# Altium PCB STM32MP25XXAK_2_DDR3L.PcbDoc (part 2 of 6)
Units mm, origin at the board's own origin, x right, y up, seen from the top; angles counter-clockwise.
Board outline 120 x 79.6 mm, 4 copper layers (Top Layer, Signal Layer 1, Signal Layer 2, Bottom Layer), stack 1.614 mm thick; 247 components, 155 nets, 1312 pads, 792 vias.
Unrouted connection lines stored in the file: 6.

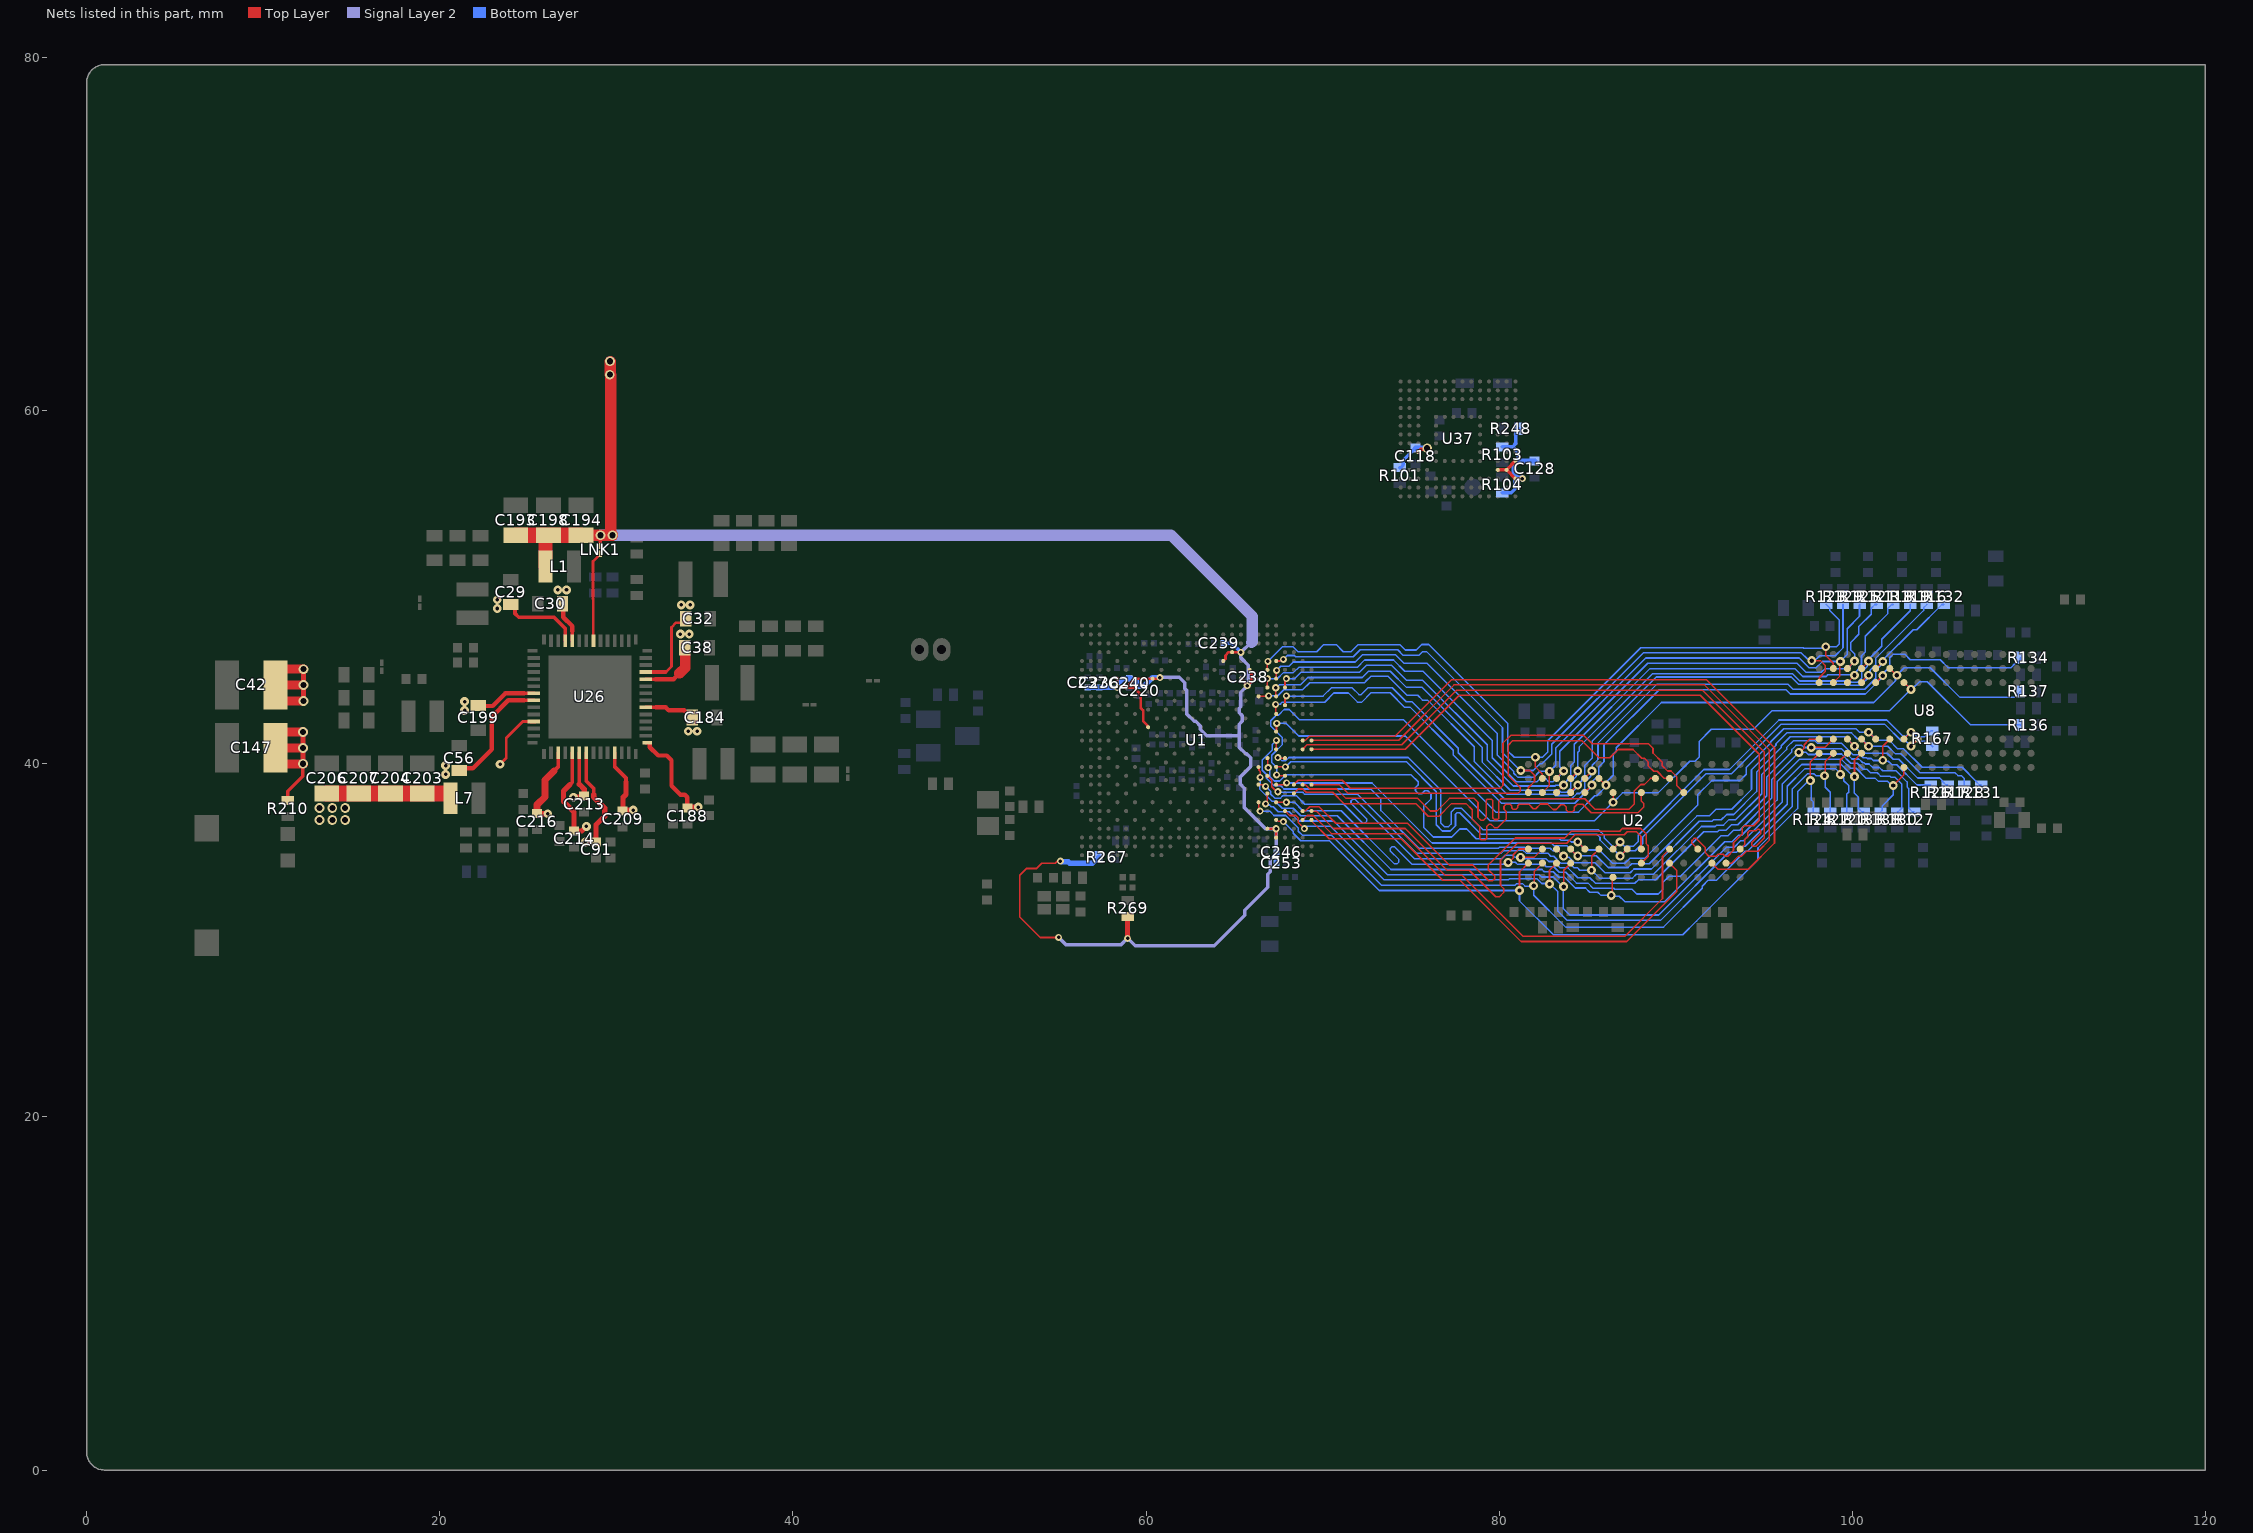
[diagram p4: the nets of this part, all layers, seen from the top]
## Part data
B2: library part MCD-03492, "Switch tactile, SPST-NO, 50mA, 12V, 6x3.8mm", Manufacturer="WURTH ELEKTRONIC", Manufacturer_Part_Number=434121025816, Package=6x3.8mm
C9 C118 C130: library part MCD-00006, "Capacitor, MLCC, 100nF, 16V, X7R, +/-10%, 0402, T=0.5mm", Alternate_Manufacturer=MURATA, Alternate_Manufacturer_Part_Number=GCM155R71C104KA55D, Manufacturer=YAGEO, Manufacturer_Part_Number=CC0402KRX7R7BB104, Package=0402
C22 C23 C24 C26 C27 C28 C34 C35 C36 C37 C41 C183 C200 C202: library part MCD-00100, "Capacitor, MLCC, 22uF, 6V3, X5R, +/-20%, 0603, T=0,8mm", Alternate_Manufacturer=N/A, Manufacturer=MURATA, Manufacturer_Part_Number=GRM188R60J226MEA0J, Package=0603
C29 C30 C32 C38 C56 C184 C199: library part MCD-00099, "Capacitor, MLCC, 10uF, 10V, X5R, +/-10%, 0603, T=0,8mm", Alternate_Manufacturer=N/A, Manufacturer=MURATA, Manufacturer_Part_Number=GRM188R61A106KE69D, Package=0603
C33: library part MCD-00011, "Capacitor, MLCC, 10nF, 16V, X7R, 10%, 0402, T=0.5mm", Manufacturer=YAGEO, Manufacturer_Part_Number=CC0402KRX7R7BB103, Package=C0402
C39 C40: library part MCD-03140, "Capacitor, MLCC, 10uF, 6.3V, X5R, +/-20%, 0402, T=0.5mm", Manufacturer=MURATA, Manufacturer_Part_Number=GRM155R60J106ME05D, Package=0402
C42 C147: library part MCD-01796, "Capacitor, Tantalum, 100uF, 6V3, 40mR, +/-20%,  Type_B (3528 metric), T=1.9mm", Manufacturer=AVX, Manufacturer_Part_Number=TCJB107M006R0040, Package="3528 (metric)"
C43 C188 C213 C216: library part MCD-00095, "Capacitor, MLCC, 1uF, 25V, X5R, +/-10%, 0402, T=0.5mm", Manufacturer=MURATA, Manufacturer_Part_Number=GRM155R61E105KA12, Package=0402
C44 C45 C46 C47 C48 C49 C50 C51 C52 C53 C54 C55 C57 C58 C59 C60 C62 C63 C64 C65 C66 C67 C68 C69 C70 C71 C72 C73 C74 C75 C76 C77 C82 C83: library part MCD-02377, "Capacitor, MLCC, 1uF, 6.3V, X5R, +/-20%, 0201, T=0,3mm", Manufacturer=MURATA, Manufacturer_Part_Number=GRM033R60J105MEA2, Package=0201
C61 C91 C189 C190 C208 C209 C214 C215 C217: library part MCD-01356, "Capacitor, MLCC, 4.7uF, 6V3, X5R, +/-20%, 0402, T=0.5mm", Manufacturer=MURATA, Manufacturer_Part_Number=GRM155R60J475ME47, Package=0402
C81 C86 C90 C92: library part MCD-00674, "Capacitor, MLCC, 6.8pF, 50V, NPO, +-0.25pF, 0402, T=0.5mm", Alternate_Manufacturer=N/A, Manufacturer=YAGEO, Manufacturer_Part_Number=CC0402CRNPO9BN6R8, Package=0402
C87: library part MCD-00006, "Capacitor,100nF,16V,X7R,10%,0402", Alternate_Manufacturer=MURATA, Alternate_Manufacturer_Part_Number=GCM155R71C104KA55D, Manufacturer=YAGEO, Manufacturer_Part_Number=CC0402KRX7R7BB104, Package=0402
C88: library part MCD-01823, "Capacitor, MLCC, 2.2uF, 6V3, X5R,+/-10%, 0402, T=0.5mm", Alternate_Manufacturer=N/A, Manufacturer=MURATA, Manufacturer_Part_Number=GRM155R60J225KE95D, Package=0402
C100 C101 C109 C110: library part MCD-00099, "Capacitor, MLCC, 10uF, 10V, X5R, +/-10%, 0603, T=0.8mm", Alternate_Manufacturer=N/A, Manufacturer=MURATA, Manufacturer_Part_Number=GRM188R61A106KE69D, Package=0603
C102 C103 C104 C105 C106 C107 C108 C111 C112 C113 C114 C115 C116 C119 C120 C121 C122 C125 C126 C127 C129 C131 C132 C133 C134 C135 C136 C137 C138 C139 C140 C146 C167 C177: library part MCD-00006, "Capacitor, MLCC, 100nF, 16V, X7R, +/-10%, 0402, T=0.5mm", Alternate_Manufacturer=MURATA, Alternate_Manufacturer_Part_Number=GCM155R71C104KA55D, Manufacturer=YAGEO, Manufacturer_Part_Number=CC0402KRX7R7BB104, Package=C0402
C117 C128 C148: library part MCD-02606, "Capacitor, MLCC, 2.2uF, 6.3V, X5R, +/-10%, 0402, T=0.5mm", Manufacturer=YAGEO, Manufacturer_Part_Number=CC0402KRX5R5BB225, Package=0402
C123 C124: library part MCD-00100, "Capacitor, MLCC, 22uF, 6V3, X5R, +/-20%, 0603, T=0,8mm", Manufacturer=MURATA, Manufacturer_Part_Number=GRM188R60J226MEA0J, Package=C0603
C151 C250 C252 C260: library part MCD-02377, "Capacitor, MLCC, 1uF, 6.3V, X5R, +/-20%, 0201, T=0,3mm", Alternate_Manufacturer=N/A, Manufacturer=MURATA, Manufacturer_Part_Number=GRM033R60J105MEA2, Package=0201
C185 C186 C187 C193 C194 C198 C203 C204 C206 C207: library part MCD-03139, "Capacitor, MLCC, 22uF, 10V, X5R, +/-20%, 0805, T=1,25mm", Manufacturer=MURATA, Manufacturer_Part_Number=GRM21BR61A226ME51L, Package=0805
C192 C195 C196 C197 C201 C205 C220 C234 C236 C237 C238 C239 C240 C244 C246 C248 C251 C253: library part MCD-01535, "Capacitor, MLCC,100nF, 10V, X7R, +/-10%, 0201, T=0.3mm", Alternate_Manufacturer=N/A, Manufacturer=MURATA, Manufacturer_Part_Number=GRM033R61A104KE15, Package=0201
C219: library part MCD-02198, "Capacitor, MLCC, 10nF, 50V, X7R, +/-10%, 0402, T=0.5mm", Manufacturer=YAGEO, Manufacturer_Part_Number=CC0402KRX7R9BB103, Package=0402
C225: library part MCD-01534, "Capacitor, MLCC, 4,7uF, 6V3, X5R, +/-20%, 0201, T=0.5mm", Alternate_Manufacturer=N/A, Manufacturer=MURATA, Manufacturer_Part_Number=GRM035R60J475ME15, Package=0201
C235: library part MCD-02235, "Capacitor, MLCC, 2.2uF, 10V, X5R,+/-10%, 0201, T=0.5mm", Manufacturer=MURATA, Manufacturer_Part_Number=GRM033R61A225KE47D, Package=0201
CN12: library part MCD-00655, "Header 2 circuits, 1.25mm Pitch ,  Vertical, with Friction Lock", Alternate_Manufacturer=N/A, Manufacturer=MOLEX, Manufacturer_Part_Number=53047-0210
D6: library part MCD-03280, "Diode, Schottky, Dual Common Cathode, 0V3, 300mA, 40V, SOT-23", Manufacturer=STMICROELECTRONICS, Manufacturer_Part_Number=BAT54CFILM, Package=SOT-23
D7: library part MCD-00034, Manufacturer=STMICROELECTRONICS, Manufacturer_HQ_COO=EU
L1 L6: library part MCD-03143, "Inductor, 2.2uH, +/-20%, Itemp= 1700mA, Isat= 2400mA, 0R140, 0806, T=1mm", Manufacturer=MURATA, Manufacturer_Part_Number=DFE201610E-2R2M{}P2, Package=0806
L2 L4: library part MCD-03142, "Inductor, 0.68uH, +/-20%, Itemp= 3900mA, Isat= 5400mA, 0R031, 1008, T=1.2mm", Manufacturer=MURATA, Manufacturer_Part_Number=DFE252012F-R68M{}P2, Package=1008
L3 L5 L7: library part MCD-03141, "Inductor, 0.68uH, +/-20%, Itemp= 3100mA, Isat= 4300mA, 0R043, 0806, T=1mm", Manufacturer=MURATA, Manufacturer_Part_Number=DFE201610E-R68M{}P2, Package=0806
LD11: library part MCD-00588, "LED Green, 0603 SMD, Forward Voltage Typ=2V, Max=2.5V", Alternate_Manufacturer="VISHAY SEMICONDUCTOR OPTO DIVISION", Alternate_Manufacturer_Part_Number=VLMTG1300-GS08, Manufacturer="OSRAM OPTO SEMICONDUCTORS", Manufacturer_Part_Number="LG Q396-PS-35", Package="LED 0603"
LNK1 LNK2 LNK4 LNK7 LNK8 LNK11: library part MCD-02777, "Track link on PCB 200um width for layout routing", Manufacturer=N/A
R1: library part MCD-02253, "Resistor, 240R, 0201, +/-1%, 1/20W", Alternate_Manufacturer=N/A, Manufacturer=YAGEO, Manufacturer_Part_Number=RC0201FR-07240RL, Package=0201
R11: library part MCD-00056, "Resistor, 0R, 0603, +/-5%, 1/10W", Manufacturer=YAGEO, Manufacturer_Part_Number=RC0603JR-070RL, Package=0603
R27 R272: library part MCD-00053, "Resistor,10K,0402,1%,1/16W", Alternate_Manufacturer=N/A, Manufacturer=YAGEO, Manufacturer_Part_Number=RC0402FR-0710KL, Package=0402
R46 R57 R59 R60 R61 R64 R75 R81 R267 R269 R286: library part MCD-00052, "Resistor,0R,0402,5%,1/16W", Alternate_Manufacturer=N/A, Manufacturer=YAGEO, Manufacturer_Part_Number=RC0402JR-070RL, Package=0402
R66: library part MCD-00058, "Resistor, 20R, 0402, +/-1%, 1/16W", Alternate_Manufacturer=N/A, Manufacturer=YAGEO, Manufacturer_Part_Number=RC0402FR-0720RL, Package=0402
R67: library part MCD-00052, "Resistor, 0R, 0402, +/-5%, 1/16W", Manufacturer=YAGEO, Manufacturer_Part_Number=RC0402JR-070RL, Package=0402
R101 R103 R104 R248: library part MCD-00053, "Resistor,10K,0402,1%,1/16W", Manufacturer=YAGEO, Manufacturer_Part_Number=RC0402FR-0710KL, Package=0402
R116 R117 R118 R119 R120 R121 R122 R123 R124 R125 R126 R127 R128 R129 R130 R131 R132 R133 R134 R135 R136 R137 R138 R139 R140: library part MCD-00054, "Resistor, 56R, 0402, +/-1%, 1/16W", Alternate_Manufacturer=N/A, Manufacturer=YAGEO, Manufacturer_Part_Number=RC0402FR-0756RL, Package=0402
R141 R142 R143 R144 R146 R147 R148 R149: library part MCD-00061, "Resistor, 1K, 0402, +/-1%,1/16W", Manufacturer=YAGEO, Manufacturer_Part_Number=RC0402FR-071KL, Package=0402
R145 R150: library part MCD-00120, "Resistor,240R,0402,1%,1/16W", Manufacturer=YAGEO, Manufacturer_Part_Number=RC0402FR-07240RL, Package=R0402
R156: library part MCD-00053, "Resistor,10K,0402,1%,1/16W", Manufacturer=YAGEO, Manufacturer_Part_Number=RC0402FR-0710KL, Package=R0402
R167: library part MCD-01819, "Resistor,100R,0402,0,5%,1/16W,±100ppm/°C", Manufacturer=YAGEO, Manufacturer_Part_Number=RC0402DR-07100RL, Package=R0402
R210: library part MCD-00441, "Resistor,270R,0402,1%,1/16W", Manufacturer=YAGEO, Manufacturer_Part_Number=RC0402FR-07270RL, Package=0402
R260 R261: library part MCD-00068, "Resistor,1K5,0402,1%,1/16W", Manufacturer=YAGEO, Manufacturer_Part_Number=RC0402FR-071K5L, Package=0402
TP21: library part MCD-00074, "Test Point 1mm", Manufacturer=n/a
U1: library part MCD-03375, "MPU , 2xCortex-A35@1.5GHz, Cortex-M33@400MHz, TFBGA 14x14, pitch 0.5, 648KB SRAM, With Crypto", Manufacturer=STMICROELECTRONICS, Package=TFBGA
U2 U8: library part MCD-01811, "Memory,DDR3L,4Gb,256Mbx16,933Mhz,1V35,TFBGA", Manufacturer=NANYA
U26: library part MCD-03000, "STPMIC2", Manufacturer=STMICROELECTRONICS, Package=VQFN
U37: library part MCD-02799, "Memory, eMMC, 4GB, 15nm ,WFBGA , 153 pins", Manufacturer=KIOXIA, Manufacturer_Part_Number=THGBMTG5D1LBAIL, Package=WFBGA153
X1: library part MCD-01479, "Crystal, 32.768kHz, 6pF, +/-20ppm, 80K, 2.05x1.2mm", Manufacturer=NDK, Manufacturer_Part_Number=NX2012SA-32.768KHZ-EXS00A-MU00527, Package=2.05x1.2mm
X2: library part MCD-02344, "Crystal, 40MHz, 6pF, +/-20ppm, 80R, 1.6x1.2mm", Manufacturer=NDK, Manufacturer_Part_Number=NX1612SA-40MHZ-EXS00A-CS13836, Package=1.6x1.2mm

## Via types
v1: diameter 0.55, hole 0.35, Top Layer to Bottom Layer, 275 vias
v2: diameter 0.4, hole 0.2, Top Layer to Bottom Layer, tented both sides, 246 vias
v3: diameter 0.5, hole 0.2, Top Layer to Bottom Layer, 146 vias
v4: diameter 0.5, hole 0.25, Top Layer to Bottom Layer, 125 vias

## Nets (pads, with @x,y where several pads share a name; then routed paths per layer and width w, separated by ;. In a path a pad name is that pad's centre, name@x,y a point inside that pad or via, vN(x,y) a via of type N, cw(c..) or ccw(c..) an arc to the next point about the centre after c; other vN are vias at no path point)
1V8: C118.2 C128.2 C193.2 C194.2 C198.2 C220.2 C236.2 C237.2 C238.2 C239.2 C240.2 C246.2 C253.2 L1.2 LNK1.2 R101.2 R103.2 R104.2 R248.2 R267.2 R269.1 U1.1E1 U1.AD22 U1.AE23 U1.D18 U1.E17 U1.F20 U1.G5 U1.G7 U1.G9 U1.G19 U1.H6 U37.C6 U37.M4 U37.N4 U37.P3 U37.P5 | length 137.4
  Top Layer w0.1: v2(55.049,30.165) 54.012,30.165 52.854,31.323 52.854,33.688 53.244,34.078 53.813,34.078 54.103,34.368 54.86,34.368 54.967,34.474 55.127,34.474 v2(55.146,34.494)
  Top Layer w0.15: U1.G5@58.375,44.825 v2(58.375,44.325) U1.H6@58.875,44.325 ; U1.1E1@60.125,42.075 60.125,42.097 60.085,42.137 60.085,42.17 59.835,42.42 59.835,43.035 59.702,43.168 59.702,43.926 59.304,44.325 U1.H6@58.875,44.325 ; v2@60.792,44.887 v2(60.79,44.885) 60.73,44.825 U1.G9@60.375,44.825 U1.G7@59.375,44.825 U1.H6@58.875,44.325 ; U1.E17@64.375,45.825 64.375,45.828 64.5,45.953 64.5,46.139 64.683,46.322 U1.D18@64.872,46.322 ; U1.D18@64.853,46.325 U1.D18@64.875,46.325 65.372,46.325 v2(65.378,46.319) ; U1.G19@65.378,44.822 65.735,44.465 v2(65.735,44.426) 65.735,44.412 65.973,44.651 65.973,45.205 65.875,45.303 U1.F20@65.875,45.325 ; U1.AD22@66.875,36.325 v2(67.375,36.325) U1.AE23@67.375,35.825 ; U37.P3@80.925,56.155 v2(81.325,56.155)
  Top Layer w0.2: LNK1.2@29.1,52.348 v1(29.1,52.95) ; U37.C6@75.425,57.655 75.602,57.832 75.877,57.832 v1(75.925,57.88) ; U37.M4@79.925,56.655 U37.N4@80.425,56.655 ; U37.P3@80.925,56.155 U37.N4@80.425,56.655 ; U37.P5@80.925,57.155 U37.N4@80.425,56.655
  Top Layer w0.3: R269.1@58.956,31.358 58.956,30.117 v2(58.962,30.112)
  Top Layer w0.64: C194.2@28,52.95 v1(29.1,52.95) v1(29.78,52.95) 29.674,53.056 v1@29.674,62.004 ; v1@29.66,62.075 v1@29.66,62.782
  Top Layer w0.8: L1.2@25.995,51.175 25.995,52.9 26.045,52.95 C198.2@26.15,52.95
  Top Layer w0.9: C193.2@24.3,52.95 C198.2@26.045,52.95 ; C198.2@26.15,52.95 C194.2@28,52.95
  Signal Layer 2 w0.2: v2(55.049,30.165) 55.449,29.766 58.598,29.766 v2@58.944,30.112 ; v2(58.962,30.112) 59.386,29.688 63.861,29.688 65.603,31.43 65.603,31.711 66.9,33.008 66.9,33.754 67.041,33.895 67.041,34.559 67.375,34.893 v2(67.375,36.325) ; v2(60.79,44.885) 60.811,44.906 61.89,44.906 62.2,44.596 62.2,44.264 62.32,44.144 62.32,42.814 62.725,42.409 62.81,42.409 63.077,42.143 ; 63.075,42.156 63.077,42.155 63.077,42.143 ; 65.285,41.575 65.285,40.928 65.64,40.572 65.694,40.572 65.93,40.336 65.93,39.851 65.349,39.271 65.349,38.835 65.569,38.615 65.569,37.527 65.566,37.525 66.77,36.322 v2@67.372,36.322 ; v2@65.674,44.353 65.773,44.452 65.773,44.591 65.794,44.612 65.794,45.583 65.378,45.999 v2(65.378,46.319) 65.927,46.868 65.981,46.868 ; v2@65.734,44.411 65.375,44.053 65.375,43.231 65.284,43.14 65.284,42.894 65.44,42.738 65.44,42.406 65.285,42.251 65.285,41.593 63.445,41.593 63.077,41.961 63.077,42.143
  Signal Layer 2 w0.64: v1@29.1,52.955 v1@29.78,52.955 ; v1(29.78,52.95) 61.405,52.95 ; 61.411,52.956 66.023,48.344 66.023,46.91 65.981,46.868
  Bottom Layer w0.15: v2(67.375,36.325) 67.375,34.827 67.391,34.811
  Bottom Layer w0.2: C239.2@64.4,46.837 64.86,46.837 v2(65.378,46.319) ; v2@65.735,44.411 65.958,44.635 65.958,44.819 C238.2@66.033,44.894 ; R101.2@74.375,56.775 74.425,56.775 74.58,56.93 74.58,57.2 75.08,57.7 75.08,57.725 75.235,57.88 C118.2@75.26,57.88 ; R103.2@80.171,57.961 80.769,57.961 ; R104.2@80.175,55.355 80.69,55.355 80.885,55.55 80.885,55.998 81.061,56.174 ; 81.075,57.136 81.075,57.655 80.769,57.961 ; R248.2@81.107,58.98 80.952,58.825 80.952,58.144 80.769,57.961
  Bottom Layer w0.25: C253.2@67.391,34.385 67.391,34.811 C246.2@67.391,34.986
  Bottom Layer w0.3: v2(55.146,34.494) 55.165,34.474 55.236,34.474 55.259,34.452 55.612,34.452 55.689,34.375 56.975,34.375 57.123,34.523 57.218,34.523 57.323,34.628 R267.2@57.323,34.723 ; C237.2@56.696,44.325 C236.2@57.35,44.325 v2@58.386,44.325 ; v2(58.375,44.325) 58.394,44.344 58.394,44.53 58.689,44.825 59.025,44.825 C240.2@59.025,44.85 ; C240.2@58.984,44.85 59.125,44.85 59.15,44.825 59.19,44.825 59.3,44.715 59.399,44.715 59.54,44.574 59.54,44.475 C220.2@59.609,44.406 59.634,44.431 59.911,44.431 60.372,44.892 60.783,44.892 v2(60.79,44.885) ; C118.2@75.26,57.88 v1(75.925,57.88) ; v2(81.325,56.155) 81.306,56.174 81.061,56.174 80.867,56.368 80.867,56.928 81.075,57.136 81.306,57.136 81.325,57.155 C128.2@82.015,57.155
  other v1: 29.631,62.047 29.642,62.8
1V8_FB: LNK1.1 U26.35 | length 5.1
  Top Layer w0.15: U26.35@28.7,46.97 28.7,49.311 28.675,49.336 28.675,51.473 LNK1.1@29.1,51.898
3V3: C203.2 C204.2 C206.2 C207.2 C216.2 L7.2 U26.3 U26.53 | length 15.3
  Top Layer w0.15: v3(23.41,39.977) 23.762,40.329 23.762,41.465 24.697,42.4 U26.53@25.33,42.4 ; U26.53@25.12,42.369 25.419,42.369 U26.53@25.45,42.4
  Top Layer w0.21: 26.473,39.598 26.7,39.825 U26.3@26.7,40.63
  Top Layer w0.3: C216.2@25.475,37.175 C216.2@25.5,37.175 v3@26.085,37.175
  Top Layer w0.4: C216.2@25.5,37.175 25.514,37.189 25.514,37.685 25.96,38.131 25.96,39.085 26.473,39.598
  Top Layer w0.9: C206.2@13.587,38.323 C203.2@19,38.323 20.362,38.323 L7.2@20.387,38.298
  other v1: 13.187,36.823 13.912,36.823 14.637,36.823 13.187,37.498 13.912,37.498 14.637,37.498
  other v3: 26.11,37.175
5V_HDMI: C91.1 U26.7 | length 6.1
  Top Layer w0.21: U26.7@28.3,40.63 28.3,39.025 28.715,38.61 28.715,38.253
  Top Layer w0.3: v3(28.24,35.58) C91.1@28.85,35.58 ; 28.715,38.253 28.715,38.118 29.335,37.498 29.335,37.035 28.85,36.55 C91.1@28.85,35.73
5V_STLK: C29.2 C30.2 C32.2 C38.2 C42.1 C56.2 C147.1 C184.2 C188.2 C199.2 C209.2 C213.2 R210.1 U26.6 U26.11 U26.15 U26.20 U26.24 U26.25 U26.38 U26.39 U26.49 U26.50 | length 56.6
  Top Layer w0.15: 32.8,45.2 33.125,45.525 33.125,47.731 33.388,47.994 33.819,47.994 C32.2@33.925,48.1
  Top Layer w0.2: R210.1@11.386,37.915 11.386,38.449 12.244,39.307 v1@12.244,39.994
  Top Layer w0.21: C29.2@24.025,49.05 24.262,48.813 24.262,48.513 24.475,48.3 26.464,48.3 27.1,47.664 U26.39@27.1,46.97 ; 24.775,43.6 U26.50@25.33,43.6 ; 24.775,44 U26.49@25.33,44 ; U26.38@27.5,46.97 27.5,47.525 ; 27.9,38.85 U26.6@27.9,40.63 ; U26.11@29.9,40.63 29.9,39.843 30.54,39.203 30.54,38.975 ; U26.15@31.67,41.2 U26.15@31.745,41.2 U26.15@31.785,41.2 ; U26.20@31.67,43.2 32.225,43.2 ; U26.24@31.67,44.8 32.207,44.8 ; U26.25@31.67,45.2 32.8,45.2
  Top Layer w0.25: C56.2@21.1,39.75 21.875,39.75 22.95,40.825 22.95,42.669 23.881,43.6 24.775,43.6 ; C199.2@22.175,43.275 22.991,43.275 23.716,44 24.775,44 ; C30.2@26.925,49.075 26.994,49.006 26.994,48.308 27.5,47.802 27.5,47.525 ; 31.895,41.095 31.895,40.947 32.371,40.472 32.853,40.472 33.125,40.2 33.125,38.759 33.634,38.25 33.879,38.25 34.025,38.104 C188.2@34.025,37.55 ; 32.207,44.8 33.25,44.8 33.575,45.125 ; 32.225,43.2 32.788,43.2 32.963,43.025 33.847,43.025 33.972,42.9 34.05,42.9 34.247,42.703 C184.2@34.247,42.625
  Top Layer w0.3: v1@12.25,40 12.25,40.902 12.25,40.906 v1@12.25,41.8 ; v1@12.275,43.563 12.275,44.463 v1@12.275,45.363 ; v3(27.565,38.11) 28.175,38.11 28.174,38.111 28.174,38.576 27.9,38.85 ; C209.2@30.35,37.38 C209.2@30.375,37.38 ; 30.54,38.975 30.54,38.269 30.375,38.104 C209.2@30.375,37.38 ; v3(30.96,37.38) C209.2@30.375,37.38 ; C188.2@34.025,37.55 v3(34.635,37.55)
  Top Layer w0.5: C147.1@10.686,39.994 12.244,39.994 v1@12.269,39.994 ; C147.1@10.686,40.906 12.25,40.906 v1@12.269,40.906 ; C147.1@10.686,41.806 v1@12.269,41.806 ; C42.1@10.686,43.557 v1@12.269,43.557 ; C42.1@10.686,44.468 v1@12.269,44.468 ; C42.1@10.686,45.368 v1@12.269,45.368
  Top Layer w0.6: 33.575,45.125 33.9,45.45 C38.2@33.9,46.175
  other v1: 12.251,40.002 12.251,40.902 12.251,41.802 12.276,43.565 12.276,44.465 12.276,45.365
  other v3: 20.325,39.4 20.325,39.9 34.075,41.85 34.575,41.85 21.4,43.025 21.4,43.525 33.625,47.35 34.125,47.35 23.25,48.8 33.675,49 34.175,49 23.25,49.3 26.675,49.85 27.175,49.85
5V_VCONN: C214.1 U26.5 | length 5.7
  Top Layer w0.21: 27.378,38.827 27.5,38.95 U26.5@27.5,40.63
  Top Layer w0.3: 27.378,38.827 27.01,38.46 27.01,37.865 27.6,37.275 C214.1@27.6,36.2 28.04,36.2 v3(28.3,36.46)
DDR_A0: R116.1 U1.J21 U2.N3 U8.N3 | length 49.2
  Top Layer w0.09: U1.J21@66.375,43.825 66.387,43.837 66.937,43.837 v2(66.95,43.85) ; U2.N3@84.057,38.377 84.057,38.425 v4@84.442,38.81 ; U8.N3@100.532,44.602 100.532,44.65 v4@100.932,45.05
  Bottom Layer w0.09: v2(66.95,43.85) 67.467,43.85 67.807,44.19 68.871,44.19 69.28,44.6 72.37,44.6 72.477,44.707 72.725,44.954 73.717,44.954 74.79,43.881 75.388,43.881 75.656,43.613 75.944,43.613 78.595,40.963 78.595,40.131 79.028,39.698 80.448,38.278 83.108,38.278 83.176,38.21 83.93,38.21 84.457,38.736 84.457,38.795 84.457,38.816 84.681,39.04 84.681,39.199 84.857,39.375 84.857,39.906 85.278,40.327 85.278,41.29 88.906,44.918 96.55,44.918 96.957,44.511 99.824,44.511 99.893,44.443 100.462,44.443 100.932,44.913 v4(100.932,45.02) 101.01,45.098 101.01,45.301 101.328,45.618 101.328,45.954 101.328,45.971 104.045,48.688 104.045,48.837 R116.1@104.233,49.025
  other v4: 84.459,38.795
DDR_A1: R117.1 U1.R23 U2.P7 U8.P7 | length 50.5
  Top Layer w0.09: U1.R23@67.375,40.825 67.378,40.828 v2@67.378,41.323 ; U2.P7@83.257,35.177 v4@83.657,34.777 ; U8.P7@99.732,41.402 v4(100.132,41)
  Bottom Layer w0.09: v2@67.378,41.327 67.142,41.09 67.142,40.776 66.58,40.215 66.58,39.642 66.817,39.406 66.817,39.202 67.252,38.766 67.628,38.766 67.819,38.575 72.734,38.575 73.309,38 73.309,37.36 75.444,35.225 79.969,35.225 80.03,35.285 81.455,35.285 81.515,35.225 82.903,35.225 83.058,35.07 83.362,35.07 v4(83.657,34.775) 83.721,34.71 83.958,34.71 84.276,34.392 85.431,34.392 85.993,33.83 87.431,33.83 87.644,34.043 88.628,34.043 91.337,36.752 92.064,36.752 92.142,36.831 92.591,36.831 92.893,37.133 93.285,37.133 94.586,38.433 94.586,39.531 95.986,40.931 95.986,41.032 96.494,41.54 99.591,41.54 v4(100.132,41) ; v4@100.131,40.998 100.131,40.979 100.395,40.715 100.626,40.715 100.738,40.602 101.985,40.602 102.328,40.259 102.646,40.259 103.707,39.198 104.958,39.198 105.103,39.053 105.103,39.01 105.313,38.8 R117.1@105.408,38.8
  other v2: 67.381,41.327
DDR_A2: R118.1 U1.H24 U2.P3 U8.P3 | length 46.5
  Top Layer w0.09: U1.H24@67.875,44.325 67.875,44.666 67.95,44.741 v2(67.95,44.825) ; U2.P3@83.257,38.377 83.657,38.776 v4(83.657,38.795) v4@83.657,38.825 ; U8.P3@99.732,44.602 100.132,45.001 v4(100.132,45.02) v4@100.132,45.05
  Bottom Layer w0.09: v2(67.95,44.825) 68.417,44.825 68.781,45.19 72.098,45.19 72.503,45.594 73.897,45.594 74.745,44.746 75.654,44.746 79.323,41.078 79.323,40.223 80.798,38.748 83.169,38.748 83.208,38.787 83.649,38.787 v4(83.657,38.795) ; v4@83.656,38.823 83.656,38.858 84.062,39.263 84.062,39.905 84.256,40.1 84.256,41.104 ; 84.255,41.104 88.549,45.398 96.749,45.398 97.197,44.95 98.53,44.95 98.624,45.044 100.128,45.044 100.128,45.127 100.252,45.251 100.252,45.264 100.373,45.385 100.373,45.484 100.527,45.638 100.527,46.124 ; 100.526,46.124 100.735,46.333 100.735,47.228 102.027,48.52 102.027,48.815 102.237,49.025 R118.1@102.332,49.025
DDR_A3: R119.1 U1.J23 U2.N2 U8.N2 | length 48
  Top Layer w0.09: v2@67.357,44.29 67.357,43.843 U1.J23@67.375,43.825 ; U2.N2@84.064,39.175 84.457,39.568 v4(84.457,39.595) ; U8.N2@100.532,45.402 100.932,45.801 v4@100.932,45.818
  Bottom Layer w0.09: v2(67.35,44.31) 67.388,44.31 67.558,44.48 68.75,44.48 69.16,44.89 72.25,44.89 72.605,45.244 73.837,45.244 73.841,45.241 74.753,44.329 75.637,44.329 ; 75.638,44.329 75.641,44.326 79.028,40.939 79.037,40.931 79.037,40.1 80.629,38.508 83.385,38.508 83.394,38.499 83.494,38.4 83.822,38.4 83.829,38.4 84.064,38.635 84.064,38.986 84.382,39.305 84.382,39.521 v4(84.457,39.595) ; v4@84.459,39.597 84.459,40.652 84.532,40.725 84.532,40.95 88.677,45.095 88.828,45.095 88.831,45.098 90.8,45.098 96.625,45.098 ; 96.625,45.097 96.629,45.095 97.032,44.691 99.899,44.691 ; 99.899,44.691 99.903,44.688 99.969,44.623 100.296,44.623 100.302,44.623 100.534,44.854 100.534,45.192 100.857,45.515 100.857,45.737 v4@100.932,45.811 ; v4@100.936,45.822 100.936,45.931 101.669,46.664 101.669,47.053 103.283,48.668 R119.1@103.283,49.025
  other v4: 100.932,45.82
DDR_A4: R120.1 U1.AB24 U2.P8 U8.P8 | length 44.3
  Top Layer w0.09: U1.AB24@67.875,37.325 67.884,37.325 68.134,37.075 68.48,37.075 68.625,36.93 68.625,36.675 v2(68.976,36.326) ; v4@82.857,33.227 82.857,33.977 U2.P8@83.257,34.377 ; v4@99.332,39.452 99.332,40.202 U8.P8@99.732,40.602
  Bottom Layer w0.09: v2(68.976,36.326) 69.125,36.475 70.443,36.475 73.493,33.425 80.531,33.425 80.606,33.5 82.137,33.5 82.412,33.225 82.857,33.225 83.316,32.765 83.316,31.667 83.834,31.149 89.168,31.149 93.012,34.993 93.45,34.993 93.79,35.333 93.946,35.333 96.326,37.713 96.326,38.725 97.333,39.733 99.057,39.733 99.331,39.458 99.331,39.388 99.529,39.19 99.529,39.04 99.802,38.768 99.802,38.395 99.699,38.292 99.699,37.279 R120.1@99.706,37.273
  other v4: 82.857,33.195 99.332,39.4
DDR_A5: R121.1 U1.H22 U2.P2 U8.P2 | length 47.2
  Top Layer w0.09: U1.H22@66.875,44.325 v2(66.875,44.825) ; U2.P2@83.257,39.175 83.257,39.196 v4(83.657,39.595) ; U8.P2@99.732,45.402 99.734,45.402 v4@100.132,45.8
  Bottom Layer w0.09: v2@66.874,44.823 67.441,44.823 67.788,45.17 68.351,45.17 68.661,45.48 71.978,45.48 72.383,45.884 74.017,45.884 74.655,45.246 75.686,45.246 79.613,41.319 79.613,40.343 80.968,38.988 82.145,38.988 82.395,39.237 82.57,39.237 82.657,39.15 ; 82.655,39.148 82.815,38.988 83.059,38.988 83.657,39.585 v4(83.657,39.595) 83.657,39.617 83.443,39.831 83.443,40.716 88.424,45.698 96.873,45.698 97.381,45.19 98.256,45.19 98.459,45.393 99.727,45.393 100.131,45.798 100.143,45.809 100.147,45.813 100.147,46.22 99.928,46.439 99.928,46.888 100.378,47.339 100.378,47.78 101.077,48.478 101.077,48.815 101.287,49.025 R121.1@101.382,49.025
  other v4: 100.132,45.82
DDR_A6: R122.1 U1.AA21 U2.R8 U8.R8 | length 45.2
  Top Layer w0.09: U1.AA21@66.375,37.825 66.375,37.484 66.45,37.409 v2@66.45,37.325 ; v4(81.957,33.099) 82.003,33.146 82.003,33.913 82.457,34.367 U2.R8@82.457,34.377 ; v4(98.432,39.324) 98.48,39.372 98.48,40.14 98.932,40.592 U8.R8@98.932,40.602
  Bottom Layer w0.09: v2(66.46,37.325) 67.003,37.325 67.253,37.075 67.923,37.075 68.631,36.367 68.631,36.183 68.864,35.95 70.511,35.95 73.336,33.125 80.898,33.125 80.993,33.22 81.32,33.22 81.465,33.075 81.956,33.075 81.956,32.564 83.765,30.756 89.315,30.756 91.506,32.947 91.506,33.07 91.853,33.418 92.326,33.418 93.951,35.043 94.066,35.043 96.616,37.593 96.616,38.593 97.468,39.445 97.825,39.445 97.948,39.322 98.431,39.322 98.476,39.277 98.476,38.678 98.757,38.397 R122.1@98.758,37.275
DDR_A7: R123.1 U1.F22 U2.R2 U8.R2 | length 46
  Top Layer w0.09: U1.F22@66.875,45.325 66.875,45.775 v2(66.9,45.8) ; v4(82.057,40.375) 82.057,39.822 82.451,39.427 82.451,39.18 U2.R2@82.457,39.175 ; v4(98.5,46.631) 98.5,46.137 98.932,45.705 U8.R2@98.932,45.4
  Bottom Layer w0.09: v2(66.9,45.8) 67.735,46.635 68.322,46.635 68.607,46.35 69.668,46.35 70.072,46.754 70.771,46.754 71.175,46.35 71.618,46.35 72.022,46.754 74.378,46.754 74.683,46.449 75.315,46.449 75.626,46.76 76.022,46.76 80.483,42.3 80.483,40.746 80.856,40.373 v4(82.057,40.375) 82.461,40.373 82.756,40.668 82.756,41.302 88.025,46.571 88.056,46.588 97.228,46.588 97.262,46.554 98.422,46.554 v4(98.5,46.631) ; v4@98.491,46.638 99.106,46.638 99.278,46.809 99.278,48.131 98.723,48.685 98.723,48.833 R123.1@98.532,49.025
DDR_A8: R124.1 U1.AC23 U2.T8 U8.T8 | length 43.3
  Top Layer w0.09: U1.AC23@67.375,36.825 67.413,36.825 67.498,36.74 67.77,36.74 v2(67.78,36.73) ; v4(81.157,32.825) 81.157,33.876 U2.T8@81.657,34.377 ; v4(97.632,39.05) 97.632,40.101 U8.T8@98.132,40.602
  Bottom Layer w0.09: v2(67.78,36.73) 68.341,36.169 68.341,36.063 68.762,35.642 70.393,35.642 73.21,32.825 v4(81.157,32.825) ; v4@81.156,32.823 81.156,32.236 83.078,30.315 90.407,30.315 91.188,31.096 94.666,34.574 94.666,35.233 96.906,37.472 96.906,38.426 97.528,39.048 97.631,39.048 v4@97.631,38.951 ; v4@97.635,38.951 97.686,38.9 97.686,37.956 97.807,37.836 R124.1@97.808,37.275
DDR_A9: R125.1 U1.G23 U2.R3 U8.R3 | length 46.5
  Top Layer w0.09: U1.G23@67.375,44.825 67.375,45.275 v2(67.4,45.3) ; U2.R3@82.457,38.377 82.832,38.752 v4@82.832,39.552 ; U8.R3@98.932,44.602 99.307,44.977 v4@99.307,45.777
  Bottom Layer w0.09: v2(67.4,45.3) 67.631,45.531 68.103,45.531 68.341,45.77 71.858,45.77 72.263,46.174 74.137,46.174 74.614,45.698 75.919,45.698 79.903,41.714 79.903,40.506 80.837,39.572 80.837,39.461 81.068,39.23 81.963,39.23 82.308,39.575 v4(82.857,39.575) 83.206,39.924 83.206,40.904 88.3,45.998 96.998,45.998 97.543,45.453 97.973,45.453 98.32,45.8 v4(99.332,45.8) 99.332,45.809 99.721,46.199 99.721,47.659 100.418,48.355 100.418,49.01 R125.1@100.433,49.025
DDR_A10: R126.1 U1.V22 U2.L7 U8.L7 | length 48
  Top Layer w0.09: U1.V22@66.875,39.325 67.125,39.075 67.125,38.708 67.411,38.421 v2(67.471,38.421) ; v4@85.243,33.981 85.243,34.761 U2.L7@85.657,35.175 ; v4(101.732,40.2) 101.732,41 U8.L7@102.132,41.4
  Bottom Layer w0.09: v2(67.471,38.421) 67.493,38.4 67.744,38.4 67.759,38.385 68.88,38.385 68.975,38.289 71.967,38.289 75.331,34.925 80.109,34.925 80.252,35.068 81.043,35.068 81.07,35.095 81.376,35.095 81.547,34.925 82.778,34.925 82.933,34.77 83.096,34.77 83.476,34.39 83.48,34.39 83.493,34.378 83.969,34.378 84.222,34.125 84.426,34.125 84.576,33.975 v4(85.237,33.975) 85.682,33.53 87.555,33.53 87.768,33.743 88.752,33.743 91.462,36.452 92.246,36.452 92.324,36.531 92.715,36.531 93.027,36.843 93.405,36.843 94.876,38.313 94.876,39.397 96.286,40.807 96.286,40.922 96.684,41.32 97.875,41.32 98.037,41.157 99.406,41.157 100.038,40.525 100.452,40.525 100.624,40.353 100.818,40.353 100.869,40.302 101.086,40.302 101.197,40.191 101.723,40.191 v4(101.732,40.2) 101.781,40.151 102.047,40.151 102.252,39.946 102.531,39.946 103.677,38.8 R126.1@104.458,38.8
DDR_A11: R127.1 U1.W21 U2.R7 U8.R7 | length 52.1
  Top Layer w0.09: U1.W21@66.375,38.825 66.392,38.808 66.617,38.808 66.696,38.729 v2(66.78,38.729) ; v4@81.232,34.7 81.252,34.72 82.002,34.72 U2.R7@82.457,35.175 ; U2.R7@82.456,35.175 U2.R7@82.457,35.177 ; v4(97.682,40.925) 97.708,40.951 98.482,40.951 U8.R7@98.932,41.402
  Bottom Layer w0.09: v2(66.78,38.729) 67.073,38.436 67.073,38.279 67.291,38.062 67.62,38.062 67.753,38.195 68.523,38.195 68.999,37.719 71.197,37.719 72.274,36.641 72.398,36.641 72.514,36.757 72.514,36.859 71.611,37.762 71.611,37.894 71.711,37.994 71.845,37.994 75.209,34.63 75.227,34.63 75.232,34.625 80.148,34.625 80.325,34.801 80.326,34.801 80.343,34.818 80.778,34.818 80.896,34.7 v4(81.213,34.7) 81.288,34.625 82.654,34.625 82.809,34.47 83.099,34.47 83.462,34.107 83.903,34.107 84.457,33.553 85.134,33.553 85.457,33.23 87.68,33.23 87.893,33.443 88.876,33.443 91.586,36.152 92.37,36.152 92.449,36.231 92.839,36.231 93.161,36.553 93.526,36.553 95.166,38.193 95.166,39.277 ; 95.173,39.27 96.587,40.683 96.587,40.813 96.818,41.045 97.145,41.045 97.265,40.925 v4(97.682,40.925) 97.749,40.857 99.401,40.857 99.984,40.275 100.381,40.275 100.596,40.06 100.687,40.06 ; 100.687,40.053 100.748,39.993 100.96,39.993 101.16,39.793 101.543,39.793 101.729,39.607 102.477,39.607 103.111,38.974 103.111,38.684 103.206,38.589 103.206,37.485 103.416,37.275 R127.1@103.508,37.275
DDR_A12: R128.1 U1.W23 U2.N7 U8.N7 | length 47.4
  Top Layer w0.09: U1.W23@67.375,38.825 67.383,38.817 67.842,38.817 67.95,38.925 67.959,38.925 v2(67.964,38.92) ; U2.N7@84.057,35.177 84.057,35.152 84.407,34.802 v4@84.457,34.802 ; U8.N7@100.532,41.402 100.532,41.377 100.882,41.027 v4@100.932,41.027
  Bottom Layer w0.09: v2@67.964,38.915 72.803,38.915 76.204,35.515 82.945,35.515 83.09,35.37 83.837,35.37 84.409,34.798 v4@84.456,34.798 ; v4@84.457,34.8 85.509,34.8 86.179,34.13 87.306,34.13 ; 87.306,34.129 87.52,34.343 88.503,34.343 91.213,37.052 91.911,37.052 92.291,37.433 93.175,37.433 94.296,38.554 94.296,39.665 95.686,41.056 95.686,41.142 96.298,41.753 99.96,41.753 100.29,41.423 100.508,41.423 v4(100.932,41) ; v4@100.932,40.998 102.013,40.998 102.448,40.563 102.774,40.563 103.842,39.495 ; 103.845,39.498 105.827,39.498 105.988,39.336 106.185,39.336 106.358,39.163 R128.1@106.358,38.8
  other v4: 84.457,34.79
DDR_A13: R129.1 U1.E23 U2.T3 U8.T3 | length 46.3
  Top Layer w0.09: U1.E23@67.375,45.825 67.606,45.825 67.701,45.92 v2(67.784,45.92) ; v4@81.257,39.625 81.732,39.625 82.007,39.35 82.007,39 81.657,38.65 U2.T3@81.657,38.377 ; v4@97.732,45.85 98.207,45.85 98.482,45.575 98.482,45.225 98.132,44.875 U8.T3@98.132,44.602
  Bottom Layer w0.09: v2(67.784,45.92) 68.001,46.137 68.41,46.137 68.487,46.06 71.738,46.06 72.142,46.464 74.258,46.464 74.562,46.159 75.468,46.159 75.669,46.36 75.887,46.36 80.193,42.054 80.193,40.626 81.194,39.625 v4(81.232,39.625) ; v4@81.232,39.623 81.932,39.623 82.325,40.016 82.438,40.016 82.981,40.559 82.981,41.103 88.176,46.298 97.108,46.298 97.449,45.957 97.489,45.957 97.598,45.848 v4@97.731,45.848 ; v4@97.732,45.849 97.807,45.775 98.162,46.13 99.045,46.13 99.482,46.567 R129.1@99.482,49.025
  other v4: 97.707,45.85
DDR_A14: R130.1 U1.AA23 U2.T7 U8.T7 | length 49.3
  Top Layer w0.09: U1.AA23@67.375,37.825 v2(67.95,37.825) ; v4@80.568,34.427 80.803,34.663 80.803,34.852 81.128,35.177 U2.T7@81.657,35.177 ; v4@97.043,40.652 97.287,40.896 97.287,41.088 97.518,41.32 97.6,41.402 U8.T7@98.132,41.402
  Bottom Layer w0.09: v2(67.95,37.825) 67.959,37.834 68.394,37.834 68.883,37.345 71.059,37.345 74.054,34.35 74.242,34.35 74.326,34.435 74.326,34.576 73.836,35.067 73.836,35.202 73.933,35.299 74.078,35.299 75.052,34.325 80.276,34.325 80.293,34.342 80.429,34.342 v4(80.508,34.42) ; v4@80.508,34.425 80.921,34.425 81.041,34.305 82.521,34.305 82.523,34.303 82.551,34.303 82.679,34.175 83.097,34.175 83.412,33.86 83.769,33.86 84.384,33.246 85.035,33.246 85.324,32.956 86.494,32.956 86.552,32.898 87.531,32.898 87.801,32.628 89.02,32.628 89.262,32.869 89.262,33.262 89.635,33.635 90.278,33.635 92.574,35.931 92.964,35.931 93.275,36.243 93.626,36.243 95.456,38.073 95.456,39.128 96.976,40.648 97.398,40.648 97.518,40.528 97.87,40.528 97.899,40.557 99.399,40.557 99.921,40.035 100.281,40.035 100.623,39.693 100.836,39.693 101.035,39.493 101.419,39.493 101.605,39.307 102.134,39.307 102.198,39.242 102.431,39.242 102.81,38.863 102.81,37.483 102.6,37.273 R130.1@102.556,37.273
  other v4: 96.982,40.65
DDR_A15: R131.1 U1.T22 U2.M7 U8.M7 | length 52.7
  Top Layer w0.09: U1.T22@66.875,40.325 66.9,40.3 66.9,39.81 v2(66.925,39.785) ; v4(84.457,35.577) U2.M7@84.857,35.177 ; v4@100.932,41.775 100.944,41.775 101.317,41.402 U8.M7@101.332,41.402
  Bottom Layer w0.09: v2@66.925,39.783 67.007,39.701 67.007,39.28 67.257,39.03 67.573,39.03 67.916,39.373 75.03,39.373 75.419,38.984 75.419,38.819 75.265,38.666 75.265,38.484 75.438,38.311 75.623,38.311 75.785,38.473 75.963,38.473 76.145,38.291 76.145,38.015 75.725,37.595 75.725,36.404 76.274,35.854 77.315,35.854 77.771,36.311 78.161,36.311 78.707,35.765 83.41,35.765 83.504,35.671 83.983,35.671 84.081,35.573 84.455,35.573 v4(84.457,35.577) 84.913,35.118 85.679,35.118 86.424,34.373 87.125,34.373 87.395,34.643 88.235,34.643 91.258,37.666 91.258,38.26 92.057,39.059 93.643,39.059 93.996,39.413 93.996,39.789 95.386,41.18 95.386,41.252 96.128,41.993 100.212,41.993 100.408,41.798 v4@100.929,41.798 ; v4@100.934,41.795 101.402,41.327 102.109,41.327 102.572,40.863 102.907,40.863 103.968,39.803 106.228,39.803 107.003,39.029 107.003,39.01 107.213,38.8 R131.1@107.304,38.8
  other v4: 100.932,41.795
DDR_BA0: R132.1 U1.K24 U2.M2 U8.M2 | length 48.4
  Top Layer w0.09: U1.K24@67.875,43.325 67.875,43.686 67.95,43.761 v2(67.95,43.845) ; U2.M2@84.857,39.175 84.857,39.196 v4(85.257,39.595) ; U8.M2@101.332,45.402 101.345,45.402 101.732,45.789 v4(101.732,45.8)
  Bottom Layer w0.09: v2(67.95,43.845) 67.957,43.838 70.024,43.838 70.487,44.301 71.683,44.301 72.059,43.925 72.193,43.925 72.578,44.31 73.951,44.31 74.745,43.516 75.062,43.516 77.692,40.887 77.692,40.624 80.296,38.02 84.107,38.02 84.408,38.321 84.57,38.321 84.861,38.612 84.861,38.967 85.191,39.296 85.191,39.529 v4(85.257,39.595) 85.279,39.617 85.279,39.927 85.602,40.25 85.602,41.178 88.921,44.498 96.376,44.498 96.644,44.23 100.709,44.23 101.331,44.851 101.331,45.298 101.732,45.699 v4(101.732,45.8) 101.732,45.883 103.453,47.604 103.666,47.604 105.087,49.025 R132.1@105.182,49.025
DDR_BA1: R133.1 U1.Y22 U2.N8 U8.N8 | length 47
  Top Layer w0.09: v2(66.779,37.729) 66.779,37.813 66.875,37.909 U1.Y22@66.875,38.325 ; v4(83.657,33.05) 83.657,33.976 U2.N8@84.057,34.377 ; v4(100.132,39.275) 100.132,40.201 U8.N8@100.532,40.602
  Bottom Layer w0.09: v2(66.779,37.729) 66.838,37.669 67.001,37.669 67.099,37.571 67.212,37.571 67.493,37.29 68.118,37.29 68.643,36.765 70.633,36.765 73.674,33.725 82.281,33.725 82.416,33.59 83.067,33.59 v4@83.609,33.048 ; v4@83.656,33.048 83.632,33.024 83.632,31.81 84.003,31.439 89.041,31.439 92.885,35.283 93.316,35.283 93.666,35.633 93.836,35.633 96.036,37.833 96.036,38.86 97.139,39.963 99.38,39.963 99.967,39.376 100.03,39.376 v4(100.132,39.275) 100.109,39.252 100.109,38.367 100.352,38.125 100.352,37.485 100.562,37.275 R133.1@100.658,37.275
DDR_BA2: R134.1 U1.L23 U2.M3 U8.M3 | length 53
  Top Layer w0.09: v2(67.343,43.364) 67.359,43.348 67.359,42.841 U1.L23@67.375,42.825 ; U2.M3@84.857,38.375 84.857,38.396 v4(85.257,38.795) ; U8.M3@101.332,44.6 v4(101.733,45)
  Bottom Layer w0.09: v2(67.343,43.364) 67.361,43.382 67.598,43.382 67.708,43.492 70.119,43.492 70.639,44.011 71.466,44.011 71.976,43.501 72.23,43.501 72.749,44.02 73.831,44.02 74.634,43.217 74.951,43.217 77.402,40.766 77.402,40.504 80.136,37.77 84.291,37.77 85.257,38.735 v4(85.257,38.795) 85.257,38.985 85.654,39.381 85.654,39.835 85.94,40.122 85.94,41.078 89.065,44.203 96.247,44.203 96.496,43.955 100.75,43.955 101.733,44.937 v4(101.733,45) 101.733,45.1 102.135,45.502 102.135,46.005 102.348,46.218 102.973,46.218 103.291,45.9 104.986,45.9 ; 104.986,45.897 105.428,45.455 109.004,45.455 109.244,45.695 109.323,45.695 109.533,45.905 R134.1@109.533,46
DDR_CASN: R136.1 U1.N23 U2.K3 U8.K3 | length 50.8
  Top Layer w0.09: U1.N23@67.375,41.825 67.39,41.84 67.39,42.278 v2(67.405,42.293) ; v4@86.457,37.827 U2.K3@86.457,38.376 ; U8.K3@102.931,44.6 102.957,44.6 103.307,44.25 v4@103.332,44.25
  Bottom Layer w0.09: v2@67.405,42.292 67.946,42.292 68.659,41.578 74.686,41.578 79.485,36.78 85.409,36.78 v4(86.457,37.827) 86.466,37.827 86.993,38.354 88.997,38.354 90.798,40.155 91.096,40.155 91.334,40.393 91.334,41.267 92.025,41.957 94.415,41.957 95.462,43.005 102.117,43.005 v4(103.332,44.22) 103.375,44.22 103.808,44.653 104.258,44.653 106.703,42.208 109.323,42.208 R136.1@109.533,42.2
DDR_CKE: R138.1 U1.U21 U2.K9 U8.K9 | length 48.5
  Top Layer w0.09: U1.U21@66.375,39.825 66.402,39.798 66.402,39.632 66.469,39.565 v2(66.469,39.23) ; v4(86.357,32.55) 86.407,32.6 86.407,33.526 U2.K9@86.457,33.577 ; v4(102.332,38.775) 102.932,39.375 U8.K9@102.932,39.802
  Bottom Layer w0.09: v2(66.469,39.23) 66.469,38.906 66.435,38.872 66.435,38.581 67.144,37.872 67.328,37.872 67.72,37.48 68.338,37.48 68.763,37.055 70.833,37.055 73.873,34.015 82.401,34.015 ; 82.401,34.013 82.431,34.013 82.562,33.883 83.071,33.883 83.379,33.575 83.709,33.575 ; 83.709,33.575 84.314,32.97 84.897,32.97 85.137,32.729 85.592,32.729 85.773,32.548 86.356,32.548 86.402,32.502 86.809,32.502 87.113,32.198 89.389,32.198 92.779,35.587 93.196,35.587 93.562,35.953 93.746,35.953 95.746,37.953 95.746,38.994 97.005,40.253 99.398,40.253 99.906,39.745 100.224,39.745 100.773,39.195 101.298,39.195 101.486,39.007 102.009,39.007 102.243,38.773 102.331,38.773 102.331,38.248 101.701,37.617 101.701,37.368 R138.1@101.608,37.275
DDR_CLK_N: R167.2 U1.T24 U2.K7 U8.K7 | length 47.4
  Top Layer w0.09: v2(67.474,40.349) 67.498,40.325 U1.T24@67.875,40.325 ; U2.K7@86.457,35.177 v4(86.857,35.575) ; U8.K7@102.934,41.402 v4@103.332,41.8
  Bottom Layer w0.09: v2(67.474,40.349) 67.517,40.349 67.682,40.184 67.916,40.184 68.094,40.362 74.853,40.362 76.69,38.524 76.69,36.648 76.89,36.449 77.136,36.449 77.283,36.595 77.283,37.254 77.509,37.48 77.874,37.48 79.084,36.27 85.636,36.27 85.968,35.938 85.968,35.791 86.444,35.315 86.597,35.315 v4(86.857,35.575) 87.107,35.325 87.607,35.325 87.881,35.599 87.881,35.96 91.6,39.678 93.049,39.678 95.854,42.483 101.958,42.483 102.887,41.555 103.03,41.555 103.273,41.798 103.421,41.798 103.68,41.539 104.129,41.539 104.252,41.662 104.252,41.665 104.462,41.875 R167.2@104.557,41.875
  other v4: 103.332,41.795
DDR_CLK_P: R167.1 U1.U23 U2.J7 U8.J7 | length 47.1
  Top Layer w0.09: U1.U23@67.381,39.831 v2(67.899,39.831) ; v4@86.857,34.777 U2.J7@87.257,35.177 ; v4@103.332,41 U8.J7@103.732,41.4
  Bottom Layer w0.09: v2(67.899,39.831) 67.916,39.83 68.198,40.112 74.749,40.112 76.44,38.421 76.44,36.545 76.786,36.199 77.239,36.199 77.533,36.492 77.533,37.15 77.612,37.23 77.771,37.23 78.981,36.02 85.533,36.02 85.718,35.835 85.718,35.688 86.34,35.065 86.586,35.065 86.857,34.795 v4(86.857,34.775) 87.157,35.075 87.71,35.075 88.131,35.496 88.131,35.856 91.703,39.428 93.153,39.428 95.958,42.233 101.854,42.233 102.783,41.305 103.024,41.305 103.331,40.998 103.358,40.998 103.648,41.289 104.146,41.289 104.25,41.185 104.347,41.185 R167.1@104.557,40.975
  other v4: 103.332,41.005
DDR_CSN: R137.1 U1.V24 U2.L2 U8.L2 | length 55.6
  Top Layer w0.09: v2(67.4,39.375) 67.45,39.325 U1.V24@67.875,39.325 ; U2.L2@85.657,39.177 v4@86.009,38.825 ; U8.L2@102.132,45.402 v4@102.484,45.05
  Bottom Layer w0.09: v2(67.4,39.375) 67.4,39.798 67.127,40.071 67.127,40.493 67.726,41.092 67.726,41.484 67.06,42.15 67.06,42.436 67.262,42.638 67.264,42.638 67.393,42.768 67.512,42.768 67.823,43.078 68.107,43.078 68.691,42.494 74.591,42.494 79.815,37.27 84.502,37.27 85.425,38.193 85.53,38.193 86.056,38.719 v4(86.057,38.795) 86.056,38.957 86.461,39.362 86.461,40.545 86.631,40.715 86.631,40.913 89.194,43.476 ; 89.195,43.475 101.225,43.475 102.453,44.702 102.453,44.941 v4(102.532,45.02) 102.955,45.443 104.425,45.443 106.106,43.762 109.195,43.762 R137.1@109.533,44.1
DDR_DQ0: U1.AB26 U2.H8 | length 25.5
  Top Layer w0.09: U1.AB26@68.875,37.325 68.889,37.339 69.035,37.339 69.271,37.575 69.799,37.575 70.743,36.63 74.813,36.63 77.173,34.27 78.514,34.27 79.41,33.375 79.633,33.375 79.756,33.498 79.756,33.641 79.388,34.009 79.388,34.27 80.918,35.801 83.712,35.8 84.1,36.188 86.829,36.188 86.979,36.339 88.025,36.339 88.328,36.035 88.328,35.484 88.455,35.358 88.455,34.772 U2.H8@88.057,34.375
DDR_DQ1: U1.AC26 U2.F7 | length 27.2
  Top Layer w0.09: U1.AC26@68.875,36.825 69.125,37.075 69.479,37.075 70.503,36.05 74.572,36.05 76.932,33.69 77.901,33.69 81.365,30.227 87.118,30.227 89.258,32.367 89.258,34.778 U2.F7@89.657,35.177
DDR_DQ2: U1.AB27 U2.H7 | length 24.4
  Top Layer w0.09: U1.AB27@69.375,37.325 69.639,37.325 70.623,36.34 74.692,36.34 77.052,33.98 78.317,33.98 ; 78.317,33.976 79.813,32.48 80.027,32.48 80.256,32.709 80.256,32.942 80.082,33.116 80.082,34.554 81.039,35.51 83.832,35.51 84.302,35.98 87.092,35.98 87.261,36.149 87.79,36.149 88.038,35.9 88.038,35.194 U2.H7@88.057,35.175
DDR_DQ3: U1.AC27 U2.F8 | length 26.5
  Top Layer w0.09: U1.AC27@69.375,36.825 69.375,36.768 70.383,35.76 74.452,35.76 76.812,33.4 77.781,33.4 81.245,29.937 87.238,29.937 90.054,32.752 90.054,33.977 U2.F8@89.657,34.375
DDR_DQ4: U1.W25 U2.E3 | length 26.9
  Top Layer w0.09: U1.W25@68.375,38.825 68.625,39.075 71.113,39.075 71.568,38.62 80.065,38.62 80.222,38.777 80.222,41.178 80.653,41.61 84.8,41.61 85.271,41.139 88.461,41.139 88.72,40.881 88.72,40.61 89.242,40.088 89.242,39.898 89.546,39.593 89.736,39.593 90.075,39.255 90.075,38.76 U2.E3@90.457,38.377
DDR_DQ5: U1.W27 U2.F2 | length 25.6
  Top Layer w0.09: U1.W27@69.375,38.825 70.953,38.825 71.448,38.33 81.074,38.33 81.207,38.464 81.207,38.644 80.512,39.34 80.512,41.058 80.774,41.32 84.68,41.32 85.661,40.339 86.274,40.339 86.75,40.815 87.591,40.815 88.087,40.32 88.235,40.32 88.455,40.1 88.455,39.884 88.762,39.577 88.959,39.577 89.359,39.177 U2.F2@89.657,39.177
DDR_DQ6: U1.W26 U2.G2 | length 26.5
  Top Layer w0.09: U1.W26@68.875,38.825 68.899,38.825 68.912,38.811 69.035,38.811 69.271,38.575 70.793,38.575 71.327,38.04 75.397,38.04 76.108,37.329 76.478,37.329 77.189,38.04 78.597,38.04 78.807,37.831 78.807,36.966 78.973,36.8 79.112,36.8 79.279,36.966 79.279,37.941 79.332,37.994 79.567,37.994 79.642,37.918 79.642,36.947 79.74,36.849 79.914,36.849 79.99,36.925 79.99,37.89 80.116,38.017 84.848,38.017 85.433,37.432 87.356,37.432 87.654,37.73 87.654,38.46 88.024,38.83 88.231,38.83 88.575,39.174 88.856,39.174 U2.G2@88.857,39.175
DDR_DQ7: U1.Y25 U2.H3 | length 26.9
  Top Layer w0.09: U1.Y25@68.375,38.325 68.625,38.575 68.88,38.575 69.07,38.385 70.573,38.385 71.207,37.75 75.277,37.75 75.988,37.039 76.598,37.039 77.309,37.75 78.13,37.75 78.479,37.402 78.479,36.875 78.898,36.457 78.898,35.799 78.99,35.706 79.22,35.706 79.296,35.782 79.296,36.453 79.414,36.571 79.559,36.571 79.738,36.391 79.925,36.391 80.407,36.873 80.407,37.303 80.28,37.43 80.28,37.606 80.378,37.705 80.631,37.705 80.721,37.615 80.721,37.506 80.809,37.419 80.947,37.419 81.053,37.524 81.053,37.621 81.142,37.71 81.689,37.71 81.942,37.457 82.075,37.457 82.345,37.727 82.747,37.727 83.057,37.416 83.234,37.416 83.497,37.679 83.671,37.679 83.812,37.537 83.812,37.385 83.899,37.298 84.177,37.298 84.257,37.378 84.257,37.537 84.431,37.711 84.739,37.711 85.219,37.231 87.869,37.231 88.199,37.561 88.199,37.748 88.057,37.889 U2.H3@88.057,38.375
DDR_DQ8: U1.R27 U2.D7 | length 38.2
  Top Layer w0.09: U1.R27@69.375,40.825 74.68,40.825 77.744,43.89 91.388,43.89 94.732,40.545 94.732,36.806 94.422,36.495 93.895,36.495 93.762,36.363 93.762,36.009 93.279,35.526 93.279,35.1 92.952,34.773 92.795,34.773 92.693,34.874 92.396,34.874 92.294,34.773 91.879,34.773 91.676,34.976 91.676,35.263 91.164,35.775 91.04,35.775 90.912,35.647 90.912,35.521 U2.D7@91.257,35.175
DDR_DQ9: U1.R26 U2.A7 | length 37.8
  Top Layer w0.09: U1.R26@68.875,40.825 69.125,41.075 74.493,41.075 77.598,44.18 91.513,44.18 95.022,40.67 95.022,35.801 94.556,35.335 94.385,35.335 94.302,35.417 94.302,35.535 94.82,36.053 94.82,36.204 94.737,36.288 94.624,36.288 94.542,36.205 94.18,36.205 94.079,36.104 94.079,35.876 93.905,35.702 93.905,35.423 U2.A7@93.657,35.175
DDR_DQ10: U1.P27 U2.B8 | length 36.9
  Top Layer w0.09: U1.P27@69.375,41.325 69.388,41.338 74.314,41.338 77.445,44.47 91.633,44.47 95.312,40.79 95.312,35.681 94.676,35.045 94.018,35.045 93.748,34.775 93.562,34.775 93.162,34.375 U2.B8@92.857,34.375
DDR_DQ11: U1.P26 U2.C8 | length 39.4
  Top Layer w0.09: U1.P26@68.875,41.325 68.894,41.344 69.04,41.344 69.271,41.575 74.125,41.575 77.31,44.76 91.753,44.76 95.602,40.91 95.602,35.511 94.121,34.03 92.402,34.03 U2.C8@92.057,34.375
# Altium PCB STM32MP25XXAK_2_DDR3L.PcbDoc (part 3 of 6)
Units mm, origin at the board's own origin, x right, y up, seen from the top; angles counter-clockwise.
Board outline 120 x 79.6 mm, 4 copper layers (Top Layer, Signal Layer 1, Signal Layer 2, Bottom Layer), stack 1.614 mm thick; 247 components, 155 nets, 1312 pads, 792 vias.
Unrouted connection lines stored in the file: 6.

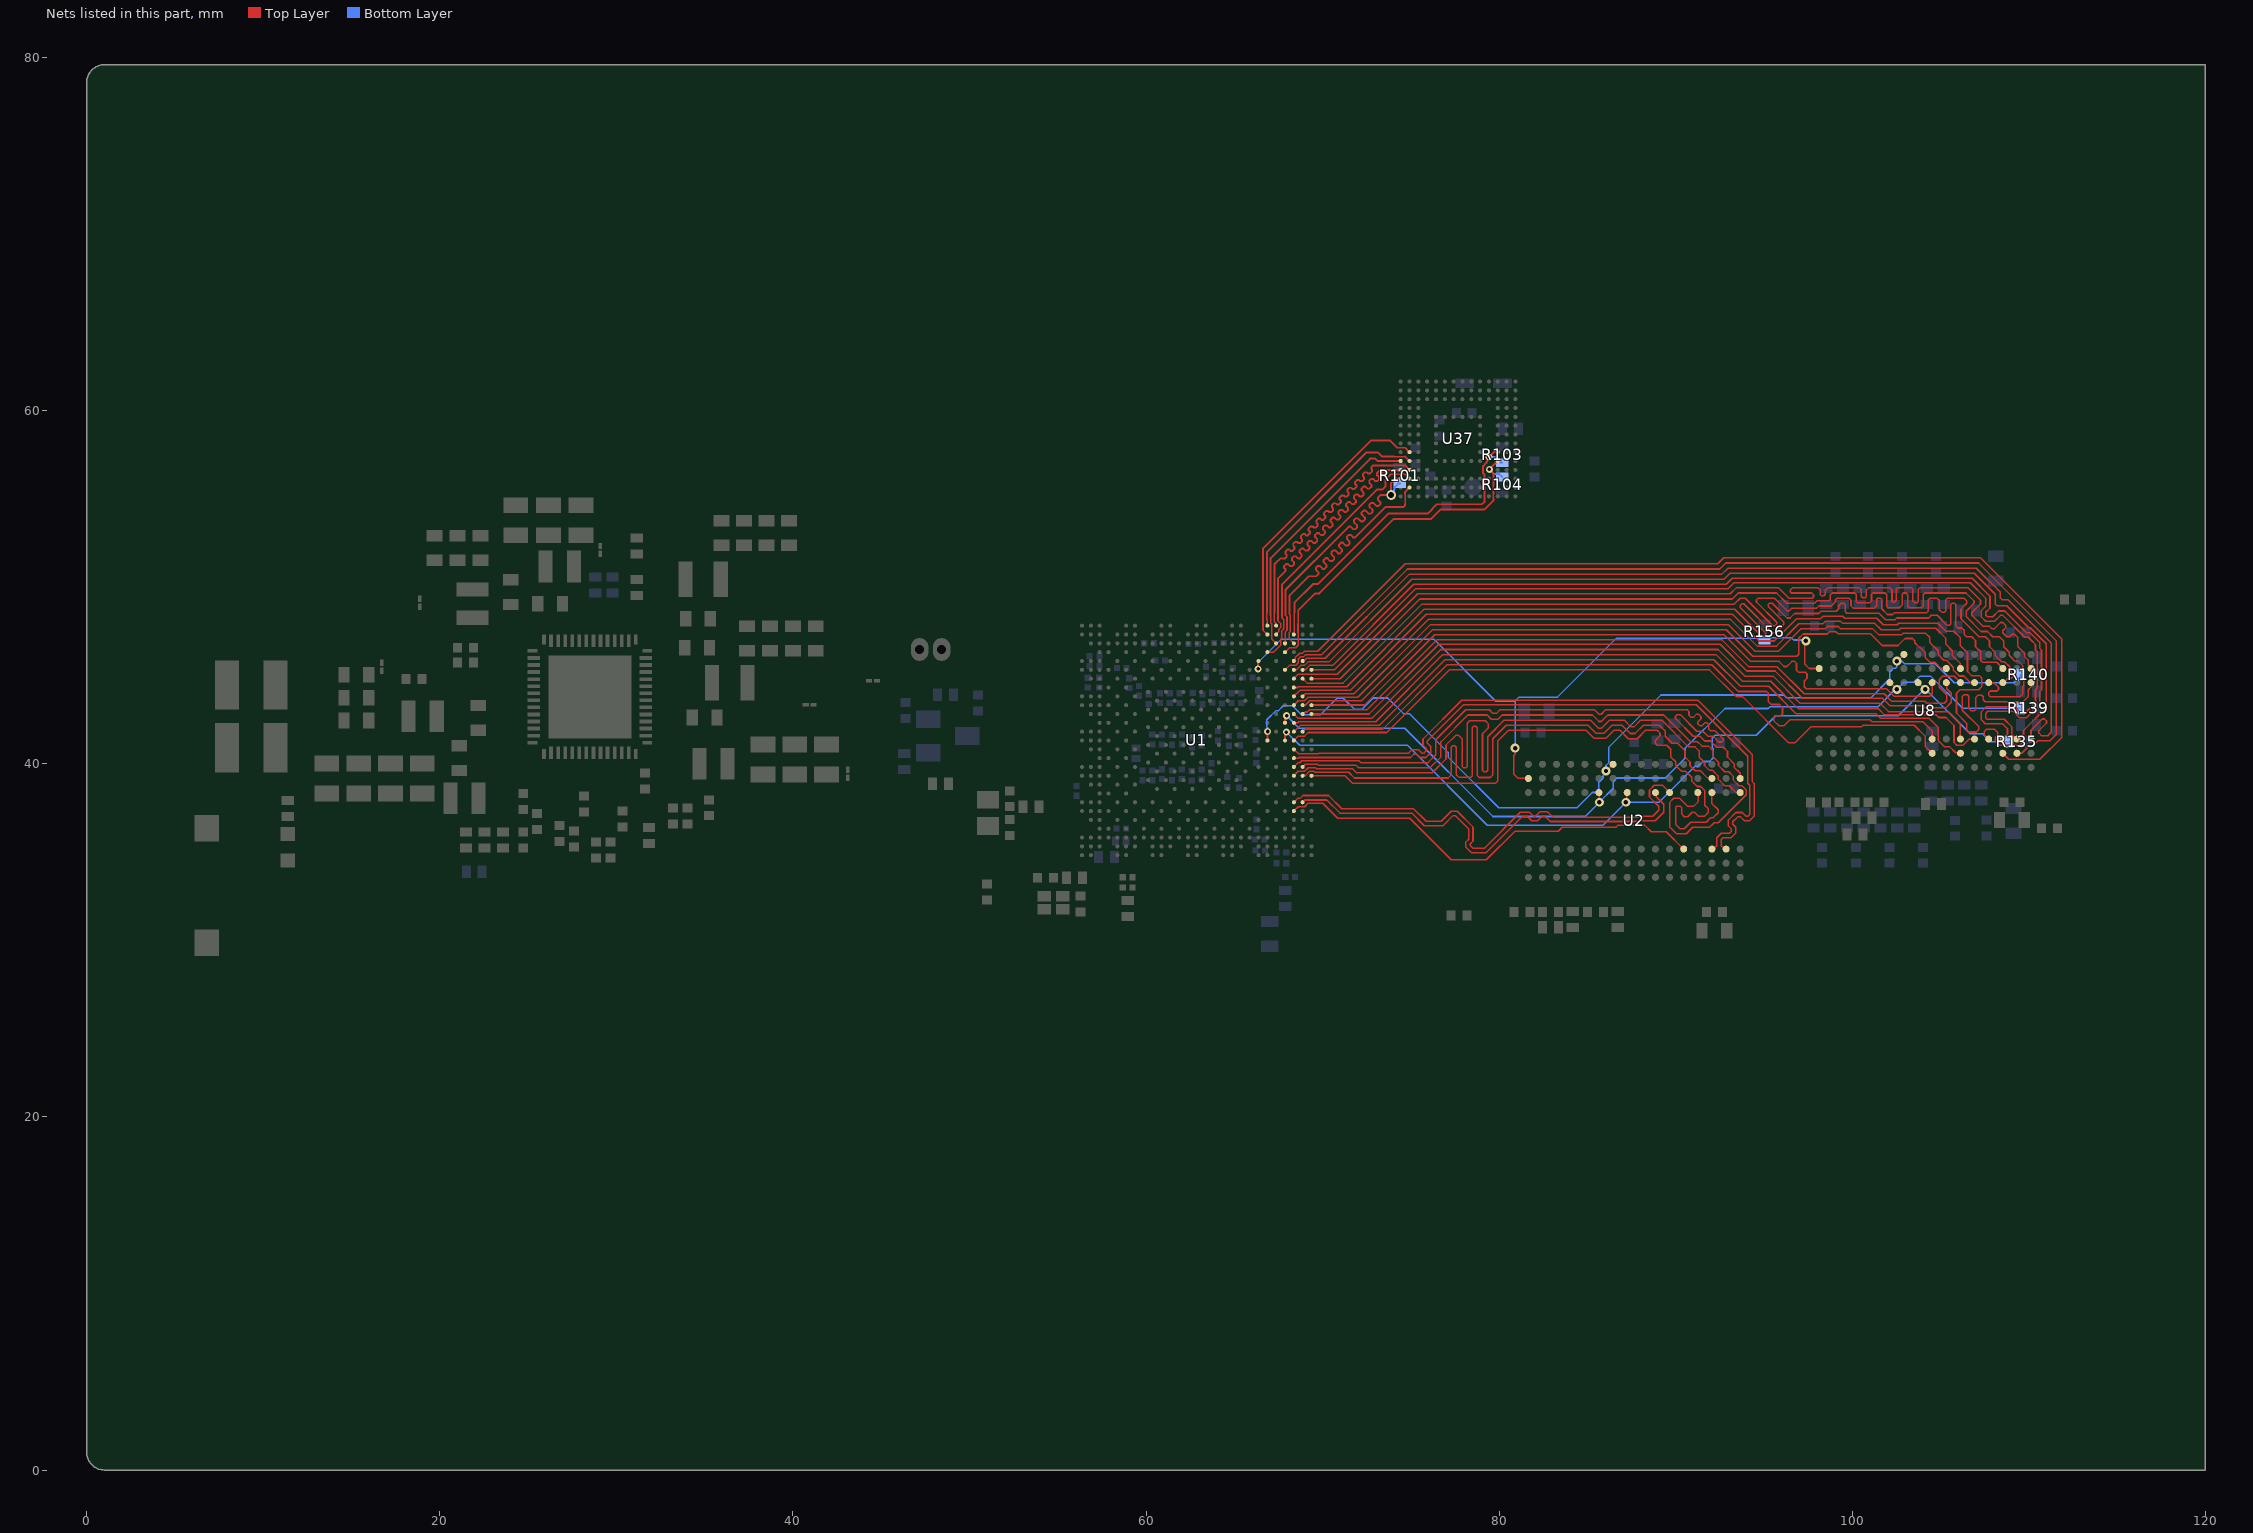
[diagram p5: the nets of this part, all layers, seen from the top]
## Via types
v1: diameter 0.55, hole 0.35, Top Layer to Bottom Layer, 275 vias
v2: diameter 0.4, hole 0.2, Top Layer to Bottom Layer, tented both sides, 246 vias
v3: diameter 0.5, hole 0.2, Top Layer to Bottom Layer, 146 vias
v4: diameter 0.5, hole 0.25, Top Layer to Bottom Layer, 125 vias

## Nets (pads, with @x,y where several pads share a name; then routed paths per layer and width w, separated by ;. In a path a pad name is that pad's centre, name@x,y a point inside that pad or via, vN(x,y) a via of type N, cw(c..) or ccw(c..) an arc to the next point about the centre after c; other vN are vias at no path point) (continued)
DDR_DQ12: U1.V26 U2.C2 | length 37.4
  Top Layer w0.09: U1.V26@68.875,39.325 68.89,39.34 69.033,39.34 69.281,39.589 69.505,39.589 69.567,39.526 69.581,39.526 71.482,39.526 71.808,39.2 77.111,39.2 77.285,39.375 77.285,40.944 77.376,41.035 77.487,41.035 77.575,40.948 77.575,39.388 77.731,39.232 78.405,39.232 78.482,39.309 78.482,42.062 78.557,42.137 78.684,42.137 78.772,42.049 78.772,39.324 78.869,39.227 79.504,39.227 79.642,39.364 79.642,41.418 80.413,42.19 85.041,42.19 85.493,41.738 85.942,41.738 86.394,42.19 86.965,42.19 87.436,41.719 87.703,41.719 88.174,42.19 89.078,42.19 89.406,41.862 89.406,41.567 89.811,41.162 90.106,41.162 90.529,40.739 90.529,40.394 90.815,40.108 90.815,39.891 91.104,39.602 91.404,39.602 91.782,39.224 92.011,39.224 U2.C2@92.057,39.177
DDR_DQ13: U1.V27 U2.C3 | length 37.5
  Top Layer w0.09: U1.V27@69.385,39.335 U1.V27@69.375,39.325 71.273,39.325 71.688,38.91 79.815,38.91 79.932,39.027 79.932,41.298 80.533,41.9 84.92,41.9 85.373,41.448 86.062,41.448 86.514,41.9 86.845,41.9 87.316,41.429 87.823,41.429 88.294,41.9 88.958,41.9 89.116,41.742 89.116,41.586 88.839,41.31 88.839,41.171 88.957,41.053 89.503,41.053 89.729,40.827 89.729,40.394 90.01,40.113 90.01,39.901 90.327,39.585 90.565,39.585 90.912,39.238 90.912,39.032 91.224,38.719 91.422,38.719 91.655,38.486 91.655,37.655 91.858,37.452 91.858,37.259 91.62,37.021 91.308,37.021 91.065,37.264 90.941,37.264 90.681,37.004 90.493,37.004 90.355,37.142 90.355,37.496 90.257,37.595 90.065,37.595 89.996,37.526 89.996,36.58 90.247,36.328 90.484,36.328 90.85,36.695 91.734,36.695 91.996,36.957 92.134,36.957 92.412,37.234 92.412,37.397 92.036,37.774 92.036,38.354 U2.C3@92.057,38.375
DDR_DQ14: U1.V25 U2.A3 | length 39.5
  Top Layer w0.09: U1.V25@68.375,39.325 68.624,39.574 68.771,39.574 68.981,39.575 69.187,39.781 69.595,39.781 69.66,39.716 71.702,39.716 71.928,39.49 76.213,39.49 76.995,40.272 76.995,41.064 77.541,41.61 77.713,41.61 77.902,41.42 77.902,39.854 77.982,39.775 78.119,39.775 78.192,39.848 78.192,42.304 78.325,42.437 79.212,42.437 79.396,42.252 79.396,42.042 79.062,41.708 79.062,39.642 79.152,39.552 79.267,39.552 79.352,39.636 79.352,41.538 80.293,42.48 85.161,42.48 85.613,42.028 85.821,42.028 86.274,42.48 87.086,42.48 87.472,42.093 87.644,42.093 88.03,42.48 89.21,42.48 90.731,40.959 91.098,40.959 91.328,40.729 91.328,40.39 91.398,40.32 91.4,40.32 91.634,40.086 91.634,39.905 91.912,39.627 92.097,39.627 92.405,39.318 92.405,39.139 92.512,39.032 92.714,38.83 92.784,38.76 93.039,38.76 93.424,38.375 U2.A3@93.657,38.375
DDR_DQ15: U1.U25 U2.A2 | length 37.5
  Top Layer w0.09: U1.U25@68.375,39.825 68.61,40.06 68.716,40.06 68.825,40.169 72.069,40.169 72.168,40.07 75.973,40.07 76.415,40.512 76.415,41.368 78.107,43.06 79.445,43.06 79.649,42.856 79.849,42.856 80.053,43.06 85.407,43.06 85.656,42.811 85.785,42.811 86.033,43.06 90.657,43.06 90.756,42.961 90.756,42.749 90.857,42.648 91.01,42.648 91.184,42.821 91.283,42.821 91.437,42.667 91.437,42.556 91.246,42.366 91.246,42.277 91.376,42.147 91.483,42.147 91.668,42.332 91.772,42.332 91.871,42.233 91.871,41.982 91.968,41.884 92.219,41.884 92.69,41.414 92.69,41.317 92.613,41.24 92.447,41.24 92.113,41.574 91.818,41.574 91.537,41.854 91.203,41.854 90.273,42.784 90.075,42.784 89.993,42.701 89.993,42.563 90.999,41.558 91.385,41.558 91.648,41.295 91.977,41.295 92.326,40.945 92.695,40.945 92.936,40.704 92.936,40.385 93.312,40.009 93.312,39.807 93.657,39.462 U2.A2@93.657,39.175
DDR_DQ16: U1.F25 U8.D7 | length 56.7
  Top Layer w0.09: U1.F25@68.375,45.325 68.52,45.325 68.77,45.575 68.981,45.575 69.181,45.775 70.363,45.775 75.047,50.459 92.743,50.459 93.081,50.797 106.915,50.797 108.098,49.613 108.098,49.053 108.204,48.948 108.763,48.948 110.001,47.71 110.084,47.71 110.991,46.803 110.991,43.171 109.704,41.884 109.704,41.277 109.482,41.055 108.354,41.055 108.12,41.289 108.12,41.515 108.249,41.645 108.249,41.77 108.069,41.95 107.596,41.95 107.491,41.845 107.491,41.626 U8.D7@107.741,41.375
DDR_DQ17: U1.E26 U8.A7 | length 55
  Top Layer w0.09: U1.E26@68.875,45.825 68.962,45.825 69.112,45.975 70.153,45.975 74.927,50.749 92.623,50.749 92.961,51.087 107.035,51.087 108.388,49.733 108.388,49.405 108.488,49.305 108.816,49.305 111.281,46.84 111.281,41.796 111.08,41.595 110.75,41.595 ; U8.A7@110.13,41.402 110.13,41.9 110.771,42.541 110.899,42.541 111.006,42.434 111.006,42.315 110.577,41.885 110.577,41.742 110.72,41.599
DDR_DQ18: U1.F24 U8.B8 | length 56.1
  Top Layer w0.09: U1.F24@67.875,45.325 68.125,45.575 68.479,45.575 68.625,45.721 68.625,45.929 68.771,46.075 68.943,46.075 69.043,46.175 69.943,46.175 74.807,51.039 92.503,51.039 92.841,51.377 107.155,51.377 111.571,46.961 111.571,41.676 111.2,41.305 110.524,41.305 110.219,41 110.006,41 109.606,40.6 U8.B8@109.332,40.6
DDR_DQ19: U1.E25 U8.C8 | length 57.4
  Top Layer w0.09: U1.E25@68.375,45.825 68.375,45.863 68.445,45.933 68.445,46.003 68.707,46.265 68.865,46.265 68.975,46.375 69.733,46.375 74.687,51.329 92.383,51.329 92.72,51.667 107.275,51.667 111.861,47.081 111.861,41.486 110.63,40.255 108.876,40.255 U8.C8@108.531,40.6
DDR_DQ20: U1.J25 U8.A3 | length 58.5
  Top Layer w0.09: U1.J25@68.375,43.825 68.725,44.175 71.577,44.175 75.872,48.469 93.226,48.469 94.735,46.961 95.591,46.961 96.858,48.227 98.226,48.227 98.358,48.359 99.46,48.359 99.574,48.244 101.398,48.244 101.761,47.881 102.546,47.881 102.635,47.97 104.852,47.97 105.311,47.511 105.756,47.511 106.116,47.152 106.116,46.704 106.532,46.287 106.532,45.227 106.757,45.002 107.207,45.002 107.332,44.877 107.332,44.367 107.166,44.202 106.108,44.202 105.908,44.002 105.908,42.875 106.482,42.3 106.482,41.913 106.589,41.806 107.032,41.806 107.166,41.941 107.166,42.11 106.24,43.036 106.24,43.813 106.336,43.909 106.517,43.909 106.597,43.829 106.597,43.15 106.749,42.998 106.928,42.998 106.995,43.065 106.995,43.76 107.122,43.888 107.335,43.888 107.425,43.798 107.425,43.633 107.543,43.515 109.68,43.515 109.978,43.812 109.978,44.204 110.132,44.359 U8.A3@110.132,44.6
DDR_DQ21: U1.H25 U8.C2 | length 55.4
  Top Layer w0.09: U1.H25@68.375,44.325 68.592,44.325 68.642,44.375 71.367,44.375 75.751,48.759 93.346,48.759 94.855,47.251 95.015,47.251 95.093,47.328 95.093,47.423 93.655,48.861 93.655,48.967 93.758,49.07 93.857,49.07 95.51,47.417 95.637,47.417 96.124,47.904 96.124,48.038 95.245,48.917 95.245,49.026 95.316,49.097 95.476,49.097 96.311,48.262 96.483,48.262 96.738,48.517 98.106,48.517 98.238,48.649 99.105,48.649 99.245,48.789 99.245,48.962 99.38,49.097 99.531,49.097 99.62,49.008 99.62,48.609 99.694,48.534 101.518,48.534 101.881,48.171 102.426,48.171 102.515,48.26 104.331,48.26 104.482,48.411 104.821,48.411 105.391,47.841 105.5,47.841 105.582,47.923 105.582,49.021 105.658,49.097 105.791,49.097 105.875,49.013 105.875,47.802 105.98,47.697 106.218,47.697 106.351,47.564 106.351,47.326 106.471,47.206 106.771,47.206 106.984,46.993 106.984,46.639 107.279,46.344 107.279,45.855 107.382,45.752 108.182,45.752 U8.C2@108.501,45.433 ; U8.C2@108.501,45.402 U8.C2@108.532,45.402
DDR_DQ22: U1.G26 U8.C3 | length 54.5
  Top Layer w0.09: U1.G26@68.875,44.825 69.125,44.575 71.157,44.575 75.631,49.049 93.327,49.049 93.665,49.387 93.95,49.387 95.509,47.828 95.639,47.828 95.727,47.917 95.727,48.022 94.581,49.169 94.581,49.304 94.664,49.387 95.596,49.387 96.303,48.681 96.453,48.681 96.58,48.807 97.986,48.807 98.118,48.939 98.812,48.939 99.055,49.182 99.055,49.296 99.146,49.387 99.816,49.387 99.931,49.271 99.931,48.944 100.051,48.824 101.253,48.824 101.385,48.956 101.385,49.32 101.452,49.387 101.605,49.387 101.675,49.317 101.675,48.787 102.001,48.461 102.306,48.461 102.395,48.55 104.211,48.55 104.315,48.654 104.315,49.282 104.42,49.387 104.807,49.387 104.933,49.261 104.933,48.726 105.083,48.576 105.227,48.576 105.292,48.641 105.292,49.28 105.398,49.387 106.331,49.387 106.494,49.223 106.494,49.096 106.165,48.767 106.165,48.222 107.181,47.206 107.544,47.206 107.777,46.973 107.777,46.817 cw(c107.382,46.8) 107.777,46.782 107.777,46.642 108.111,46.308 108.111,46.132 108.469,45.774 108.645,45.774 108.924,45.495 108.924,45.286 109.111,45.099 109.111,44.938 109.015,44.842 108.83,44.842 108.588,44.6 U8.C3@108.532,44.6
DDR_DQ23: U1.G25 U8.A2 | length 56.2
  Top Layer w0.09: U1.G25@68.375,44.825 68.375,44.835 68.615,45.075 70.837,45.075 75.391,49.629 93.087,49.629 93.425,49.967 95.837,49.967 96.417,49.387 97.745,49.387 97.811,49.453 97.811,49.587 97.721,49.677 96.552,49.677 96.487,49.742 96.487,49.843 96.612,49.967 98.081,49.967 98.183,49.866 98.183,49.596 98.26,49.519 98.387,49.519 98.474,49.606 98.474,49.826 98.615,49.967 100.4,49.967 100.511,49.856 100.511,49.486 100.593,49.404 100.735,49.404 100.805,49.474 100.805,49.853 100.919,49.967 102.144,49.967 102.255,49.856 102.255,49.197 102.308,49.144 102.382,49.144 102.504,49.266 102.504,49.914 102.557,49.967 103.365,49.967 103.441,49.891 103.441,49.22 103.53,49.13 103.682,49.13 103.735,49.183 103.735,49.87 103.832,49.967 106.571,49.967 107.268,49.27 107.268,49.05 106.777,48.558 106.777,48.43 107.421,47.786 107.784,47.786 107.906,47.664 108.064,47.664 108.407,48.007 108.53,48.007 108.707,47.83 108.707,47.718 108.523,47.534 108.523,47.43 108.756,47.196 108.918,47.196 109.063,47.342 109.195,47.342 109.387,47.15 109.387,46.977 109.387,46.632 109.786,46.233 109.786,46.057 109.963,45.881 109.963,45.608 110.131,45.44 U8.A2@110.132,45.4
DDR_DQ24: U1.J26 U8.F2 | length 42
  Top Layer w0.09: U1.J26@68.875,43.825 69.025,43.975 71.787,43.975 75.992,48.179 93.106,48.179 94.614,46.671 95.712,46.671 96.978,47.937 98.346,47.937 98.478,48.069 99.339,48.069 99.454,47.954 101.278,47.954 101.641,47.591 102.666,47.591 102.755,47.68 104.732,47.68 105.309,47.103 105.309,46.769 105.676,46.402 105.676,46.138 106.132,45.682 U8.F2@106.132,45.4
DDR_DQ25: U1.K25 U8.E3 | length 43.4
  Top Layer w0.09: U1.K25@68.375,43.325 68.625,43.575 68.979,43.575 69.179,43.775 71.997,43.775 76.112,47.889 92.986,47.889 94.494,46.381 95.832,46.381 97.098,47.647 98.466,47.647 98.598,47.779 99.205,47.779 99.32,47.664 101.158,47.664 101.521,47.301 102.787,47.301 102.875,47.39 104.172,47.39 104.392,47.17 104.392,46.878 104.869,46.402 104.869,46.188 105.192,45.865 105.341,45.865 105.729,45.478 105.729,45.315 106.067,44.977 106.322,44.977 106.685,44.613 106.921,44.613 U8.E3@106.932,44.602
DDR_DQ26: U1.K26 U8.G2 | length 41.4
  Top Layer w0.09: U1.K26@68.875,43.325 69.021,43.325 69.271,43.575 72.208,43.575 76.232,47.599 92.866,47.599 94.374,46.091 96.868,46.091 96.982,46.205 96.982,47.121 97.218,47.357 98.586,47.357 98.718,47.489 99.078,47.489 99.192,47.374 101.038,47.374 101.708,46.704 102.599,46.704 102.995,47.1 103.423,47.1 103.55,46.973 103.55,46.861 103.815,46.595 103.858,46.595 104.129,46.325 104.129,46.034 104.399,45.764 104.672,45.764 105.036,45.4 U8.G2@105.332,45.4
DDR_DQ27: U1.K27 U8.H3 | length 40.1
  Top Layer w0.09: U1.K27@69.375,43.325 69.386,43.336 72.379,43.336 76.352,47.309 92.746,47.309 94.254,45.801 95.853,45.801 96.139,45.515 96.301,45.515 96.587,45.801 96.738,45.801 96.849,45.69 96.849,45.298 96.956,45.191 97.348,45.191 97.441,45.098 97.441,44.842 97.279,44.681 97.279,44.375 97.399,44.255 101.938,44.255 102.368,43.825 104.391,43.825 104.531,43.965 U8.H3@104.531,44.599
DDR_DQ28: U1.L25 U8.F7 | length 42.1
  Top Layer w0.09: U1.L25@68.38,42.825 68.63,42.575 72.792,42.575 76.696,46.479 92.402,46.479 93.91,44.971 95.51,44.971 97.055,43.425 101.594,43.425 102.057,42.962 105.409,42.962 106.132,42.239 U8.F7@106.132,41.402
DDR_DQ29: U1.N25 U8.F8 | length 42.1
  Top Layer w0.09: U1.N25@68.375,41.825 68.386,41.825 68.738,42.177 73.214,42.177 76.936,45.899 92.161,45.899 93.67,44.391 95.269,44.391 96.815,42.845 101.354,42.845 101.625,42.574 104.365,42.574 104.879,42.06 104.879,41.317 105.219,40.977 105.511,40.977 105.863,40.625 106.107,40.625 U8.F8@106.132,40.6
DDR_DQ30: U1.N26 U8.H7 | length 41.1
  Top Layer w0.09: U1.N26@68.875,41.825 69.022,41.972 73.419,41.972 77.056,45.609 92.041,45.609 93.55,44.101 95.149,44.101 95.256,43.993 95.256,43.522 95.416,43.363 95.887,43.363 96.052,43.198 96.052,42.832 95.94,42.72 95.637,42.72 95.549,42.632 95.549,42.458 95.852,42.154 96.134,42.154 96.479,42.5 101.008,42.5 101.127,42.38 104.013,42.38 104.531,41.861 U8.H7@104.531,41.4
DDR_DQ31: U1.P25 U8.H8 | length 40.9
  Top Layer w0.09: U1.P25@68.375,41.325 68.627,41.575 68.981,41.575 69.18,41.774 73.631,41.774 77.176,45.319 91.921,45.319 93.43,43.811 93.785,43.811 96.41,41.186 96.746,41.186 97.651,42.09 100.53,42.09 ; 100.532,42.09 100.53,42.09 ; U8.H8@104.531,40.6 104.132,40.999 104.132,41.578 103.52,42.19 100.629,42.19 100.53,42.09
DDR_DQM0: U1.AB25 U2.E7 | length 25
  Top Layer w0.09: U1.AB25@68.375,37.325 68.625,37.575 68.988,37.575 69.178,37.765 70.019,37.765 70.864,36.92 74.933,36.92 77.293,34.56 79.268,34.56 80.897,36.19 83.357,36.19 83.576,36.409 86.611,36.409 86.733,36.531 88.243,36.531 88.62,36.153 89.472,36.153 90.448,35.177 U2.E7@90.457,35.177
DDR_DQM1: U1.U26 U2.D3 | length 39.3
  Top Layer w0.09: U1.U26@68.875,39.825 69.024,39.974 69.711,39.974 69.776,39.909 71.919,39.909 72.048,39.78 76.093,39.78 76.705,40.392 76.705,41.243 78.232,42.77 79.325,42.77 79.563,42.531 79.934,42.531 80.173,42.77 85.287,42.77 85.658,42.399 85.783,42.399 86.153,42.77 89.33,42.77 90.843,41.257 91.239,41.257 91.491,41.005 91.856,41.005 92.132,40.73 92.132,40.388 ; U2.D3@91.257,38.375 91.27,38.361 91.27,37.843 91.014,37.587 90.693,37.587 90.224,38.056 89.901,38.056 89.657,37.812 89.657,36.431 90.049,36.038 90.604,36.038 90.967,36.402 91.919,36.402 92.182,36.664 92.42,36.664 94.002,38.246 94.002,38.518 93.761,38.76 93.585,38.76 93.254,39.091 93.254,39.307 93.002,39.559 92.779,39.559 92.429,39.909 92.429,40.091 92.132,40.388
DDR_DQM2: U1.G27 U8.D3 | length 55.2
  Top Layer w0.09: U1.G27@69.375,44.825 70.997,44.825 75.511,49.339 93.207,49.339 93.545,49.677 95.717,49.677 96.297,49.097 97.865,49.097 97.997,49.229 98.692,49.229 98.765,49.302 98.765,49.578 98.864,49.677 100.141,49.677 100.221,49.596 100.221,49.192 100.299,49.114 100.981,49.114 101.095,49.228 101.095,49.602 101.171,49.677 101.866,49.677 101.965,49.578 101.965,48.908 102.033,48.84 102.674,48.84 102.838,49.004 102.838,49.624 102.891,49.677 103.047,49.677 103.151,49.573 103.151,48.929 103.24,48.84 103.928,48.84 104.025,48.937 104.025,49.584 104.118,49.677 106.451,49.677 106.899,49.229 106.899,49.091 106.455,48.647 106.455,48.342 107.301,47.496 107.664,47.496 107.961,47.199 108.342,47.199 108.587,46.954 108.587,46.636 108.895,46.328 108.895,46.148 109.241,45.802 109.417,45.802 109.673,45.546 109.673,44.817 109.727,44.763 109.727,44.436 109.673,44.382 109.673,43.971 109.508,43.806 107.825,43.805 107.728,43.901 107.728,44.03 107.824,44.126 108.209,44.126 108.291,44.208 108.291,44.337 108.026,44.602 U8.D3@107.732,44.602
DDR_DQM3: U1.M25 U8.E7 | length 43
  Top Layer w0.09: U1.M25@68.375,42.325 68.598,42.325 68.655,42.383 73.01,42.383 76.816,46.189 92.282,46.189 93.79,44.681 95.389,44.681 96.935,43.135 101.474,43.135 101.837,42.772 104.757,42.772 104.904,42.625 105.316,42.625 105.766,42.175 105.766,41.216 105.928,41.053 106.274,41.053 106.62,41.4 U8.E7@106.932,41.4
DDR_DQS0_N: U1.AA26 U2.G3 | length 25.7
  Top Layer w0.09: U1.AA26@68.875,37.825 69.005,37.955 70.239,37.955 70.984,37.21 75.053,37.21 75.764,36.499 76.822,36.499 77.391,37.069 77.522,37.069 78.275,36.316 78.275,35.733 78.121,35.58 78.121,35.272 78.418,34.974 79.269,34.974 79.272,34.975 81.295,36.998 81.626,36.998 81.844,36.78 81.844,36.771 82.177,36.771 82.447,37.041 82.591,37.041 82.895,36.737 87.972,36.737 88.01,36.775 88.839,36.775 89.241,37.177 89.321,37.257 89.321,37.714 88.906,38.129 88.906,38.327 U2.G3@88.857,38.375
DDR_DQS0_P: U1.AA25 U2.F3 | length 27.5
  Top Layer w0.09: U1.AA25@68.375,37.825 U1.AA25@68.375,37.825 68.592,38.04 68.728,38.04 68.893,38.205 70.343,38.205 71.087,37.46 75.156,37.46 75.867,36.749 76.718,36.749 77.287,37.319 77.625,37.319 78.525,36.419 78.525,35.629 78.371,35.476 78.371,35.376 78.522,35.225 79.169,35.225 81.201,37.257 81.722,37.257 81.943,37.036 82.068,37.036 82.323,37.291 82.746,37.291 83.051,36.986 87.936,36.986 87.977,37.027 88.704,37.027 89.048,37.37 89.048,37.6 88.522,38.126 88.522,38.514 88.79,38.782 89.252,38.782 U2.F3@89.657,38.377
DDR_DQS1_N: U1.R25 U2.B7 | length 36.8
  Top Layer w0.09: U1.R25@68.375,40.825 68.633,40.567 69.755,40.567 69.799,40.61 74.879,40.61 75.076,40.808 75.427,40.808 75.625,40.61 75.749,40.61 75.875,40.736 75.875,40.874 75.69,41.058 75.69,41.407 77.883,43.6 91.268,43.6 94.329,40.539 94.329,39.001 94.442,38.887 94.442,37.032 94.196,36.785 93.883,36.785 93.673,36.995 93.515,36.995 93.242,36.722 93.242,36.577 93.41,36.409 93.41,36.083 93.142,35.815 92.686,35.815 92.582,35.711 92.582,35.366 92.774,35.175 U2.B7@92.857,35.175
DDR_DQS1_P: U1.T25 U2.C7 | length 36.3
  Top Layer w0.09: U1.T25@68.375,40.325 68.609,40.325 68.645,40.36 74.982,40.36 75.18,40.558 75.324,40.558 75.521,40.36 75.853,40.36 76.125,40.632 76.125,40.977 75.94,41.162 75.94,41.303 77.987,43.35 91.164,43.35 94.079,40.435 94.079,38.897 94.192,38.784 94.192,37.135 94.092,37.035 93.986,37.035 93.777,37.245 93.411,37.245 92.992,36.826 92.992,36.474 93.16,36.306 93.16,36.187 93.038,36.065 92.583,36.065 92.332,35.815 92.332,35.366 92.141,35.175 U2.C7@92.057,35.175
DDR_DQS2_N: U1.F26 U8.B7 | length 56.5
  Top Layer w0.09: U1.F26@68.875,45.325 68.877,45.327 69.015,45.327 69.262,45.575 70.573,45.575 75.167,50.169 92.863,50.169 93.201,50.507 106.795,50.507 107.808,49.493 107.808,48.826 107.57,48.588 107.57,48.42 107.664,48.326 107.963,48.326 108.295,48.658 108.643,48.658 109.881,47.42 110.074,47.42 110.634,46.86 110.634,46.539 110.726,46.446 110.726,44.192 110.634,44.1 110.634,43.378 109.874,42.618 109.484,42.618 109.128,42.975 107.685,42.975 107.569,42.859 107.569,42.595 107.644,42.52 108.613,42.52 109.047,42.086 109.047,41.687 U8.B7@109.332,41.402
DDR_DQS2_P: U1.F27 U8.C7 | length 55.5
  Top Layer w0.09: U1.F27@69.375,45.325 70.677,45.325 75.271,49.919 92.967,49.919 93.305,50.257 106.691,50.257 107.558,49.39 107.558,48.93 107.32,48.691 107.32,48.317 107.561,48.076 108.066,48.076 108.398,48.408 108.539,48.408 109.778,47.17 109.971,47.17 110.143,46.997 110.384,46.757 110.384,46.435 110.476,46.343 110.476,44.296 110.384,44.203 110.384,43.481 109.771,42.868 109.588,42.868 109.231,43.225 107.582,43.225 107.319,42.962 107.319,42.491 107.54,42.27 108.509,42.27 108.797,41.982 108.797,41.667 U8.C7@108.532,41.402
DDR_DQS3_N: U1.L27 U8.G3 | length 40.7
  Top Layer w0.09: U1.L27@69.375,42.825 72.631,42.825 76.576,46.769 92.522,46.769 94.03,45.261 95.63,45.261 97.176,43.715 101.714,43.715 102.144,43.285 104.029,43.285 104.13,43.184 104.952,43.184 ; 104.952,43.183 105.315,43.183 105.616,43.483 105.616,44.002 105.358,44.26 U8.G3@105.358,44.6
DDR_DQS3_P: U1.L26 U8.F3 | length 42.6
  Top Layer w0.09: U1.L26@68.875,42.825 68.913,42.825 69.027,42.939 69.135,42.939 69.271,43.075 72.528,43.075 76.472,47.019 92.625,47.019 94.134,45.511 95.733,45.511 97.279,43.965 101.818,43.965 102.248,43.535 104.133,43.535 104.233,43.434 105.209,43.434 105.353,43.578 105.353,43.91 104.927,44.336 104.927,44.771 105.112,44.956 105.785,44.956 U8.F3@106.137,44.604
DDR_ODT: R140.1 U1.P22 U2.K1 U8.K1 | length 54.9
  Top Layer w0.09: U1.P22@66.875,41.325 66.883,41.333 66.883,41.824 v2(66.89,41.832) ; v4(86.057,39.595) 86.077,39.595 U2.K1@86.457,39.975 ; v4(102.534,45.82) 102.914,46.2 U8.K1@102.932,46.2
  Bottom Layer w0.09: v2(66.89,41.832) 66.89,42.042 66.844,42.088 66.844,42.494 67.368,43.018 67.503,43.018 67.777,43.292 68.303,43.292 68.811,42.784 69.884,42.784 70.821,43.721 71.175,43.721 71.793,43.103 72.243,43.103 72.869,43.73 73.701,43.73 74.584,42.848 74.91,42.848 77.112,40.646 77.112,40.384 79.975,37.52 84.417,37.52 85.272,38.375 85.458,38.375 85.657,38.574 85.657,38.954 85.887,39.184 85.887,39.337 86.057,39.507 v4(86.057,39.595) 86.057,39.908 86.202,40.053 86.202,40.93 89.17,43.898 96.13,43.898 96.278,43.75 101.064,43.75 102.136,44.822 102.136,45.211 102.338,45.413 102.447,45.413 102.522,45.488 102.522,45.79 102.532,45.8 102.831,45.8 102.962,45.669 104.705,45.669 105.775,44.599 109.165,44.599 109.311,44.745 109.323,44.745 109.533,44.955 R140.1@109.533,45.05
DDR_RASN: R135.1 U1.P24 U2.J3 U8.J3 | length 49.9
  Top Layer w0.09: U1.P24@67.875,41.325 67.875,41.641 67.95,41.716 v2(67.95,41.8) ; v4(87.182,37.827) 87.22,37.865 87.22,38.339 U2.J3@87.257,38.377 ; U8.J3@103.731,44.6 103.757,44.6 v4@104.107,44.25
  Bottom Layer w0.09: v2(67.95,41.8) 68.703,41.047 74.807,41.047 79.335,36.52 85.888,36.52 87.182,37.814 v4(87.182,37.827) ; v4(87.182,37.827) v4(87.182,37.827) ; R135.1@108.883,41.255 107.837,41.255 107.395,41.698 106.681,41.698 104.131,44.248 102.607,42.723 95.67,42.723 94.574,41.628 92.234,41.628 92.072,41.465 92.072,40.927 92.131,40.867 92.131,40.347 91.918,40.134 91.548,40.134 91.273,39.859 91.096,39.859 89.062,37.825 v4(87.182,37.827)
  other v4: 104.132,44.22
DDR_RESETN: R156.2 U1.E21 U2.T2 U8.T2 | length 42.7
  Top Layer w0.09: v2(66.35,45.375) 66.369,45.394 U1.E21@66.369,45.819 ; v4(80.907,40.894) 80.907,40.538 80.833,40.464 80.833,39.429 81.085,39.177 U2.T2@81.657,39.177 ; v4(97.382,46.962) 97.308,46.888 97.308,45.654 97.56,45.402 U8.T2@98.132,45.402
  Bottom Layer w0.09: v2(66.35,45.375) 66.35,45.746 67.67,47.066 76.293,47.066 79.806,43.553 80.906,43.553 81.135,43.781 83.309,43.781 86.651,47.123 R156.2@94.706,47.123 ; v4(80.907,40.894) 80.907,43.553 ; R156.2@94.731,47.148 96.548,47.148 96.68,47.015 97.328,47.015 v4(97.382,46.962)
DDR_WEN: R139.1 U1.M24 U2.L3 U8.L3 | length 50.1
  Top Layer w0.09: U1.M24@67.875,42.325 67.875,42.585 67.964,42.675 v2@67.964,42.725 ; U2.L3@85.657,38.377 85.632,38.352 85.682,38.302 85.67,38.289 85.67,37.839 v4(85.682,37.827) ; U8.L3@102.131,44.6 102.157,44.6 v4@102.507,44.25
  Bottom Layer w0.09: v2(67.97,42.725) 68.671,42.024 74.651,42.024 79.655,37.02 84.879,37.02 85.682,37.823 v4(85.682,37.827) 85.682,37.837 86.461,38.616 86.461,38.986 86.673,39.198 89.415,39.198 90.532,40.314 90.532,40.877 92.792,43.137 95.249,43.137 95.347,43.235 101.46,43.235 102.445,44.22 v4(102.532,44.22) 102.935,44.623 103.495,44.623 103.844,44.972 104.443,44.972 106.267,43.148 R139.1@109.531,43.148
eMMC.SDMMC2_CK: R103.1 U1.B25 U37.M6 | length 19.1
  Top Layer w0.09: U1.B25@68.375,47.325 68.402,47.352 68.402,48.575 ; 79.175,55.037 79.175,55.273 ; 79.175,55.537 79.175,55.773 ; 79.175,56.037 79.175,56.273
  Top Layer w0.11: 68.402,48.575 68.402,49.127 69.459,50.184 69.734,50.184 73.725,54.175 75.95,54.175 76.481,54.706 79.022,54.706 79.175,54.858 79.175,55.037 ; 79.175,55.273 79.175,55.405 ; 79.175,55.407 79.175,55.537 ; 79.175,55.773 79.175,55.905 ; 79.175,55.907 79.175,56.037 ; 79.175,56.273 79.175,56.372 79.095,56.452 79.095,56.87 79.281,57.056 v2(79.425,57.375) 79.705,57.655 U37.M6@79.925,57.655
  Bottom Layer w0.11: v2(79.425,57.375) 79.762,57.375 80.076,57.061 R103.1@80.171,57.061
eMMC.SDMMC2_CMD: R104.1 U1.D24 U37.M5 | length 20
  Top Layer w0.09: U1.D24@67.875,46.325 68.125,46.575 68.479,46.575 68.625,46.721 68.625,47.429 68.615,47.439 68.615,47.453 ; 79.675,55.037 79.675,55.273 ; 79.675,55.537 79.675,55.773 ; 79.675,56.037 79.675,56.273
  Top Layer w0.11: 68.616,47.451 68.615,47.453 68.615,47.933 68.625,47.943 68.625,48.699 69.588,49.662 69.816,49.662 74.029,53.875 76.15,53.875 76.674,54.399 79.162,54.399 79.675,54.911 79.675,55.037 ; 79.675,55.273 79.675,55.405 ; 79.675,55.407 79.675,55.537 ; 79.675,55.773 79.675,55.905 ; 79.675,55.907 79.675,56.037 ; 79.675,56.273 79.675,56.46 v2(79.45,56.685) U37.M5@79.92,57.155
  Bottom Layer w0.11: v2(79.45,56.685) 79.724,56.411 80.019,56.411 R104.1@80.175,56.255
eMMC.SDMMC2_D0: R101.1 U1.C24 U37.A3 | length 16
  Top Layer w0.09: U1.C24@67.875,46.825 67.88,46.83 67.88,47.467 67.985,47.572 67.985,48.335 67.902,48.418 67.902,48.575
  Top Layer w0.11: 67.902,48.575 67.902,49.85 71.229,53.177 71.487,53.435 71.597,53.435 71.743,53.289 71.852,53.289 71.962,53.399 71.962,53.508 71.778,53.692 71.778,53.801 71.888,53.911 71.998,53.911 72.181,53.727 72.291,53.727 72.4,53.837 72.4,53.947 72.217,54.13 72.217,54.24 72.326,54.349 72.436,54.349 72.62,54.166 72.729,54.166 72.839,54.275 72.839,54.385 72.655,54.569 72.655,54.678 72.765,54.788 72.874,54.788 73.058,54.604 73.168,54.604 73.277,54.714 73.277,54.823 73.131,54.969 73.131,55.079 73.279,55.227 v1(73.884,55.227) 73.884,55.909 74.13,56.155 U37.A3@74.425,56.155
  Bottom Layer w0.11: v1(73.884,55.227) 73.884,55.34 74.056,55.512 74.056,55.556 74.08,55.58 74.08,55.675 74.28,55.875 R101.1@74.375,55.875
eMMC.SDMMC2_D1: U1.B23 U37.A4 | length 18.8
  Top Layer w0.09: U1.B23@67.375,47.325 67.375,47.357 67.52,47.502 67.52,47.616 67.625,47.721 67.625,47.952 67.479,48.098 67.479,48.575
  Top Layer w0.11: 67.479,48.575 67.479,50.504 67.856,50.881 67.895,50.92 67.895,51.03 67.824,51.101 67.824,51.21 67.934,51.32 68.044,51.32 68.165,51.199 68.274,51.199 68.384,51.308 68.384,51.418 68.263,51.539 68.263,51.649 68.372,51.758 68.482,51.758 68.603,51.637 68.713,51.637 68.822,51.747 68.822,51.856 68.701,51.977 68.701,52.087 68.811,52.197 68.92,52.197 69.042,52.075 69.151,52.075 69.261,52.185 69.261,52.295 69.14,52.416 69.14,52.525 69.249,52.635 69.359,52.635 69.48,52.514 69.59,52.514 69.699,52.623 69.699,52.733 69.578,52.854 69.578,52.964 69.688,53.073 69.797,53.073 69.918,52.952 70.028,52.952 70.138,53.062 70.138,53.171 70.016,53.293 70.016,53.402 70.126,53.512 70.236,53.512 70.357,53.391 70.466,53.391 70.576,53.5 70.576,53.61 70.455,53.731 70.455,53.841 70.564,53.95 70.674,53.95 70.795,53.829 70.905,53.829 71.014,53.939 71.014,54.048 70.893,54.169 70.893,54.279 71.003,54.389 71.112,54.389 71.234,54.267 71.343,54.267 71.453,54.377 71.453,54.487 71.332,54.608 71.332,54.718 71.441,54.827 71.551,54.827 71.672,54.706 71.782,54.706 71.891,54.815 71.891,54.925 71.77,55.046 71.77,55.156 71.88,55.266 71.989,55.266 72.11,55.144 72.22,55.144 72.33,55.254 72.33,55.363 72.208,55.485 72.208,55.594 72.318,55.704 72.428,55.704 72.549,55.583 72.658,55.583 72.768,55.692 72.768,55.802 72.647,55.923 72.647,56.033 72.756,56.142 72.866,56.142 72.987,56.021 73.097,56.021 73.206,56.131 73.206,56.24 73.085,56.362 73.085,56.471 73.195,56.581 73.304,56.581 73.375,56.51 73.485,56.51 73.536,56.561 73.63,56.655 U37.A4@74.425,56.655
eMMC.SDMMC2_D2: U1.C23 U37.A5 | length 14.7
  Top Layer w0.09: 67.055,48.395 67.055,47.999 67.125,47.929 67.125,47.075 U1.C23@67.375,46.825
  Top Layer w0.11: 67.054,48.395 67.057,48.398 67.057,51.657 72.691,57.291 72.984,57.291 73.12,57.155 74.056,57.155 U37.A5@74.425,57.155
eMMC.SDMMC2_D3: U1.C25 U37.B2 | length 15.5
  Top Layer w0.09: 68.125,48.575 68.125,48.489 68.165,48.449 68.165,47.498 68.125,47.458 68.125,47.075 U1.C25@68.375,46.825 ; 74.675,54.705 74.675,55.273
  Top Layer w0.11: 68.125,48.575 68.125,49.525 69.225,50.625 69.647,50.625 69.723,50.702 69.762,50.741 69.762,50.85 69.621,50.991 69.621,51.101 69.731,51.211 69.84,51.211 70.004,51.046 70.114,51.046 70.224,51.156 70.224,51.266 70.059,51.43 70.059,51.539 70.169,51.649 70.279,51.649 70.443,51.485 70.552,51.485 70.662,51.594 70.662,51.704 70.498,51.868 70.498,51.978 70.607,52.087 70.717,52.087 70.881,51.923 70.991,51.923 71.1,52.033 71.1,52.142 70.936,52.307 70.936,52.416 71.046,52.526 71.155,52.526 71.32,52.362 71.429,52.362 71.539,52.471 71.539,52.581 71.375,52.745 71.375,52.855 71.484,52.964 71.594,52.964 71.735,52.823 71.845,52.823 71.887,52.865 73.582,54.56 74.596,54.56 74.675,54.639 74.675,54.705 ; 74.675,55.273 74.675,55.405 U37.B2@74.925,55.655
eMMC.SDMMC2_D4: U1.D22 U37.B3 | length 14.7
  Top Layer w0.09: U1.D22@66.902,46.352 U1.D22@66.875,46.325 67.229,46.325 67.625,46.721 67.625,47.075 67.7,47.15 67.7,47.541 67.805,47.647 67.805,48.17 67.7,48.275 ; 74.056,56.405 74.543,56.405
  Top Layer w0.11: 67.7,48.275 67.692,48.283 67.692,50.142 73.1,55.55 73.4,55.55 73.575,55.725 73.575,56.125 73.855,56.405 74.056,56.405 ; 74.543,56.405 74.675,56.405 U37.B3@74.925,56.155
eMMC.SDMMC2_D5: U1.A23 U37.B4 | length 17.3
  Top Layer w0.09: 67.267,48.575 67.267,48.055 67.349,47.973 67.349,47.851 U1.A23@67.375,47.825 ; 74.056,56.905 74.543,56.905
  Top Layer w0.11: 67.267,48.575 67.267,51.292 67.362,51.387 67.621,51.646 67.73,51.646 67.75,51.625 67.86,51.625 67.97,51.735 67.97,51.845 67.901,51.913 67.901,52.022 68.011,52.132 68.121,52.132 68.189,52.064 68.298,52.064 68.408,52.173 68.408,52.283 68.34,52.351 68.34,52.461 68.449,52.57 68.559,52.57 68.627,52.502 68.737,52.502 68.846,52.612 68.846,52.721 68.778,52.79 68.778,52.899 68.888,53.009 68.997,53.009 69.066,52.941 69.175,52.941 69.285,53.05 69.285,53.16 69.217,53.228 69.217,53.338 69.326,53.447 69.436,53.447 69.504,53.379 69.614,53.379 69.723,53.489 69.723,53.598 69.655,53.666 69.655,53.776 69.765,53.886 69.874,53.886 69.942,53.817 70.052,53.817 70.162,53.927 70.162,54.037 70.093,54.105 70.093,54.214 70.203,54.324 70.313,54.324 70.381,54.256 70.49,54.256 70.6,54.365 70.6,54.475 70.532,54.543 70.532,54.653 70.641,54.762 70.751,54.762 70.819,54.694 70.929,54.694 71.038,54.804 71.038,54.913 70.97,54.982 70.97,55.091 71.08,55.201 71.189,55.201 71.258,55.133 71.367,55.133 71.477,55.242 71.477,55.352 71.409,55.42 71.409,55.53 71.518,55.639 71.628,55.639 71.696,55.571 71.806,55.571 71.915,55.681 71.915,55.79 71.847,55.858 71.847,55.968 71.957,56.078 72.066,56.078 72.134,56.01 72.244,56.01 72.354,56.119 72.354,56.229 72.285,56.297 72.285,56.406 72.395,56.516 72.505,56.516 72.573,56.448 72.682,56.448 72.792,56.558 72.792,56.667 72.772,56.687 72.772,56.797 72.88,56.905 72.912,56.905 74.056,56.905 ; 74.543,56.905 74.675,56.905 U37.B4@74.925,56.655
eMMC.SDMMC2_D6: U1.A22 U37.B5 | length 14.8
  Top Layer w0.09: 66.847,48.356 66.847,48.176 66.875,48.148 U1.A22@66.875,47.825 ; 74.056,57.405 74.675,57.405
  Top Layer w0.096: 66.847,48.356 66.847,48.575
  Top Layer w0.11: 66.847,48.575 66.847,51.997 72.49,57.64 73.14,57.64 73.375,57.405 74.056,57.405 ; 74.675,57.405 U37.B5@74.925,57.155
eMMC.SDMMC2_D7: U1.B22 U37.B6 | length 16.1
  Top Layer w0.09: 66.625,48.575 66.625,47.575 U1.B22@66.875,47.325 ; 74.307,57.905 74.543,57.905
  Top Layer w0.11: 66.625,48.575 66.625,52.197 72.738,58.31 73.836,58.31 74.241,57.905 74.307,57.905 ; 74.543,57.905 74.675,57.905 U37.B6@74.925,57.655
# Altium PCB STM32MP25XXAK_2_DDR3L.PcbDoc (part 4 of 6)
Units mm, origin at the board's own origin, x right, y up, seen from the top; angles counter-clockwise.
Board outline 120 x 79.6 mm, 4 copper layers (Top Layer, Signal Layer 1, Signal Layer 2, Bottom Layer), stack 1.614 mm thick; 247 components, 155 nets, 1312 pads, 792 vias.
Unrouted connection lines stored in the file: 6.

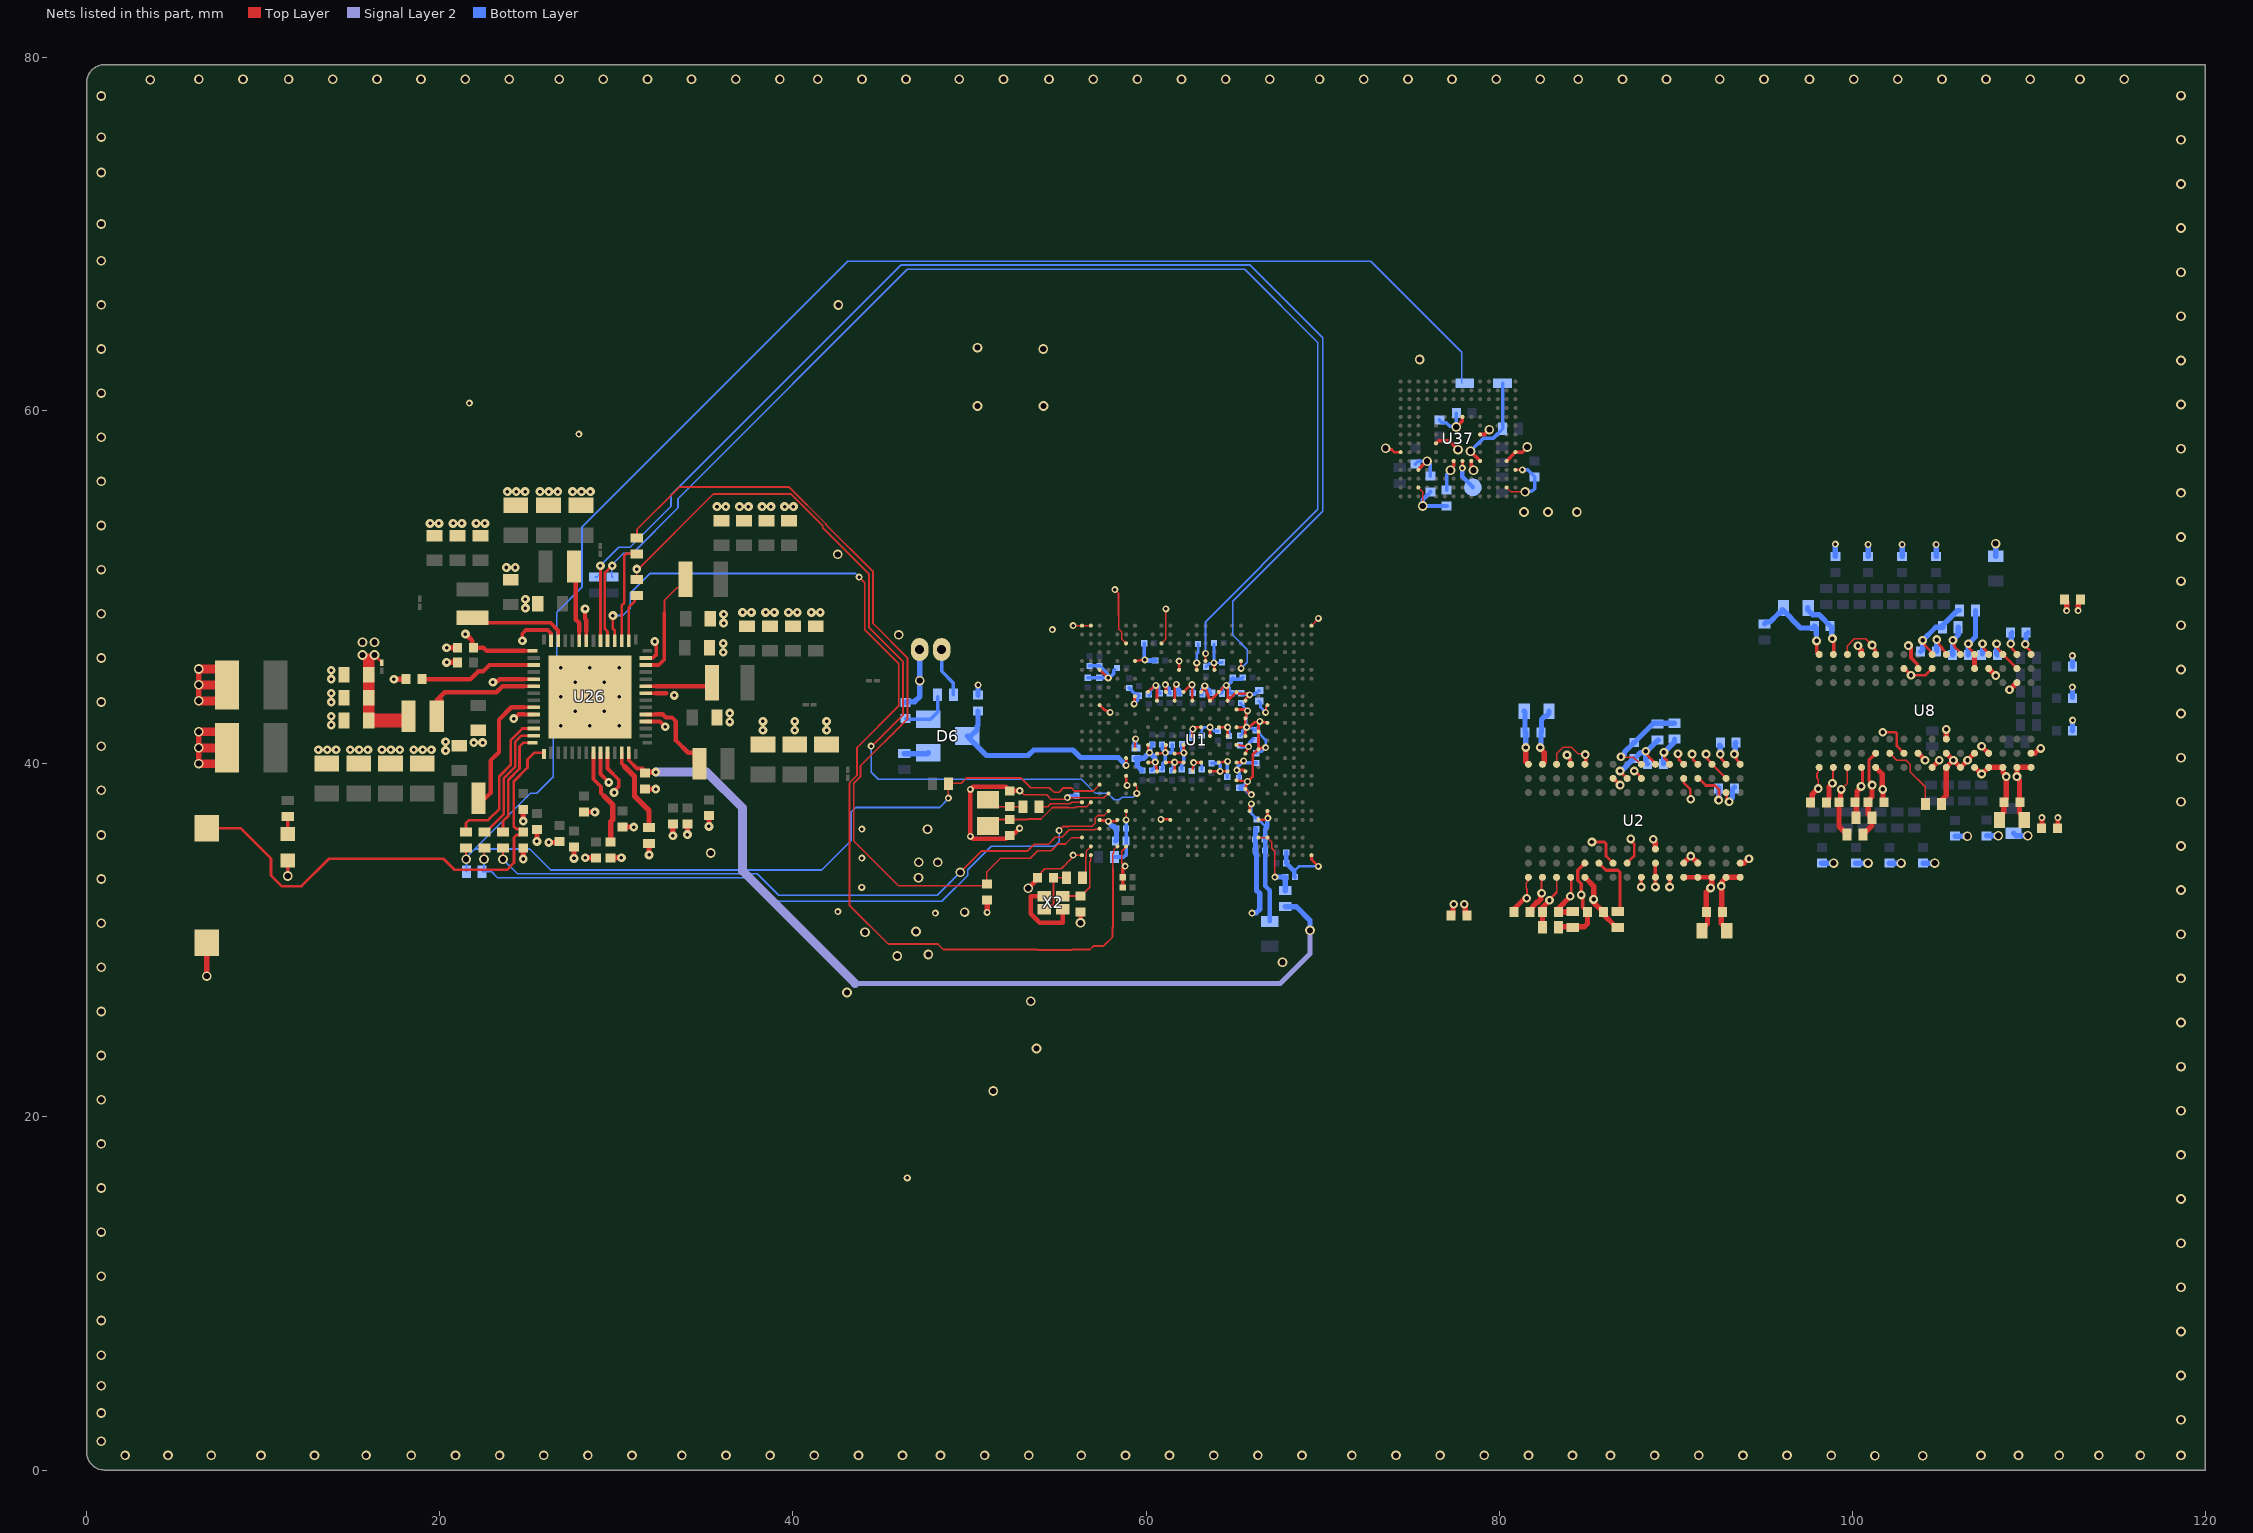
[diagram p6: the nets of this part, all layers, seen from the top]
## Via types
v1: diameter 0.55, hole 0.35, Top Layer to Bottom Layer, 275 vias
v2: diameter 0.4, hole 0.2, Top Layer to Bottom Layer, tented both sides, 246 vias
v3: diameter 0.5, hole 0.2, Top Layer to Bottom Layer, 146 vias
v4: diameter 0.5, hole 0.25, Top Layer to Bottom Layer, 125 vias

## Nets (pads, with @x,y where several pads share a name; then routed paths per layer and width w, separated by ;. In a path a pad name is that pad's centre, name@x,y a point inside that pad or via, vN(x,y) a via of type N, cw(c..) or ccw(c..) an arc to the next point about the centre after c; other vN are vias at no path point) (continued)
GND: B2.1 C9.1 C22.1 C23.1 C24.1 C26.1 C27.1 C28.1 C29.1 C30.1 C32.1 C33.1 C34.1 C35.1 C36.1 C37.1 C38.1 C39.1 C40.1 C41.1 C42.2 C43.1 C44.2 C45.1 C46.1 C47.2 C48.1 C49.1 C50.1 C51.1 C52.1 C53.1 C54.1 C55.1 C56.1 C57.1 C58.1 C59.1 C60.1 C61.1 C62.2 C63.1 C64.1 C65.2 C66.1 C67.1 C68.1 C69.1 C70.2 C71.1 C72.1 C73.2 C74.1 C75.1 C76.1 C77.2 C81.2 C82.1 C83.1 C86.2 C87.1 C88.1 C90.1 C91.2 C92.2 C100.1 C101.1 C102.1 C103.1 C104.1 C105.1 C106.1 C107.1 C108.1 C109.1 C110.1 C111.1 C112.1 C113.1 C114.1 C115.1 C116.1 C117.1 C118.1 C119.1 C120.1 C121.1 C122.1 C123.1 C124.1 C125.1 C126.1 C127.1 C128.1 C129.1 C130.1 C131.1 C132.1 C133.1 C134.1 C135.1 C136.1 C137.1 C138.1 C139.1 C140.1 C146.1 C147.2 C148.1 C151.1 C167.1 C177.1 C183.1 C184.1 C185.1 C186.1 C187.1 C188.1 C189.1 C190.2 C192.1 C193.1 C194.1 C195.1 C196.1 C197.1 C198.1 C199.1 C200.1 C201.1 C202.1 C203.1 C204.1 C205.1 C206.1 C207.1 C208.2 C209.1 C213.1 C214.2 C215.2 C216.1 C217.2 C219.1 C220.1 C225.1 C234.1 C235.1 C236.1 C237.1 C238.1 C239.1 C240.1 C244.1 C246.1 C248.1 C250.1 C251.1 C252.1 C253.1 C260.1 CN12.2 LD11.2 R1.1 R57.1 R142.1 R144.1 R145.1 R147.1 R149.1 R150.1 R156.1 U1.1A1 U1.1A3 U1.1A5 U1.1A7 U1.1A9 U1.1A11 U1.1B2 U1.1B4 U1.1B6 U1.1B8 U1.1B10 U1.1B12 U1.1E7 U1.1E9 U1.1F6 U1.1F8 U1.1F10 U1.1G1 U1.1G3 U1.1G5 U1.1G11 U1.1H2 U1.1H4 U1.1H12 U1.1J1 U1.1J3 U1.1J5 U1.1J7 U1.1J9 U1.1J11 U1.1K2 U1.1K4 U1.1K6 U1.1K8 U1.1K10 U1.1K12 U1.A1 U1.A2 U1.A27 U1.AC3 U1.AC5 U1.AC11 U1.AF6 U1.AG1 U1.AG27 U1.C6 U1.C10 U1.E7 U1.F3 U1.F12 U1.F14 U1.F16 U1.J7 U1.K3 U1.V6 U1.Y4 U2.A9 U2.B1 U2.B3 U2.B9 U2.D1 U2.D8 U2.E1 U2.E2 U2.E8 U2.F9 U2.G1 U2.G8 U2.G9 U2.J2 U2.J8 U2.M1 U2.M9 U2.P1 U2.P9 U2.T1 U2.T9 U8.A9 U8.B1 U8.B3 U8.B9 U8.D1 U8.D8 U8.E1 U8.E2 U8.E8 U8.F9 U8.G1 U8.G8 U8.G9 U8.J2 U8.J8 U8.M1 U8.M9 U8.P1 U8.P9 U8.T1 U8.T9 U26.9 U26.10 U26.18 U26.22 U26.27 U26.36 U26.41 U26.47 U26.52 U26.57 U37.A6 U37.C4 U37.E7 U37.G5 U37.H10 U37.J5 U37.K8 U37.N2 U37.N5 U37.P4 U37.P6 X2.2 X2.4 | length 255.9
  Top Layer w0.09: v2(55.55,38.085) 55.565,38.07 56.266,38.07 56.271,38.075 57.612,38.075 57.862,38.325 U1.Y4@57.875,38.325 ; U1.A1@56.375,47.825 U1.A2@56.875,47.825 ; 58.445,48.418 58.445,47.647 58.625,47.467 58.625,47.075 U1.C6@58.875,46.825 ; v2(58.816,34.213) 58.625,34.404 58.625,35.05 58.875,35.3 U1.AF6@58.875,35.325 ; U1.C10@60.875,46.825 61.125,47.075 v2(61.125,48.775) ; U37.N2@80.425,55.655 80.675,55.405 v1(81.475,55.405) ; 83.25,32.77 82.858,32.377 v4(82.858,32.275) 83.257,32.675 U2.P9@83.257,33.575 ; U2.P1@83.257,39.975 83.257,40.574 83.633,40.95 84.095,40.95 84.472,40.572 84.835,40.572 v4(84.883,40.525) ; U2.B9@92.857,33.575 U2.B9@92.861,33.575 ; v4@99.435,38.602 99.732,38.899 U8.P9@99.732,39.8 ; U8.P1@99.732,46.2 99.732,46.692 100.124,47.084 100.769,47.084 v4(101.13,46.724) ; R150.1@105.032,37.75 R150.1@105.242,37.96 ; U8.B9@109.333,39.802 U8.B9@109.332,39.8
  Top Layer w0.1: v2(52.85,38.475) 52.882,38.475 53.114,38.244 54.372,38.244 54.622,37.994 55.458,37.994 v2(55.55,38.085) ; v1@53.243,33.041 v1(53.329,32.955) ; C92.2@53.859,33.546 53.859,33.648 54.264,34.053 55.189,34.053 55.279,34.144 55.291,34.144 55.496,34.349 55.496,34.361 55.77,34.635 55.77,34.639 55.875,34.744 v2(55.875,34.825) U1.AG1@56.375,34.825 ; v2(55.875,47.825) U1.A1@56.375,47.825 ; v2(58.24,49.865) 58.445,49.66 58.445,48.418 ; U1.A27@69.375,47.825 69.762,48.213 v2(69.762,48.238) ; v4(81.566,32.386) 81.529,32.422 81.582,32.474 81.582,32.909 81.54,32.95 81.54,33.248 81.609,33.317 81.609,33.527 U2.T9@81.657,33.575 ; C111.1@97.658,37.902 C111.1@97.731,37.975 ; v4(98.082,38.6) 98.082,39.109 98.011,39.18 98.011,39.469 98.082,39.54 98.082,39.75 U8.T9@98.132,39.8
  Top Layer w0.15: U1.AC3@57.375,36.825 57.41,36.79 57.795,36.79 57.845,36.74 v2(57.872,36.74) 58.29,36.74 U1.AC5@58.375,36.825 ; U1.K3@57.375,43.325 57.643,43.057 v2(57.966,42.92) ; U1.F3@57.375,45.325 v2(57.862,44.875) ; U1.V6@58.875,39.325 58.875,38.893 58.925,38.843 v2(58.925,38.775) ; v2@59.325,43.275 59.35,43.3 59.35,43.613 ; v2(59.325,43.4) 59.35,43.613 ; U1.E7@59.375,45.825 v2(59.931,45.892) ; U1.J7@59.388,43.812 U1.J7@59.375,43.825 ; U1.1J1@60.125,40.075 v2(60.525,40.1) U1.1K2@60.625,39.575 ; U1.1G1@60.125,41.075 60.125,40.778 60.198,40.705 v2(60.198,40.638) ; U1.1A1@60.125,44.075 60.442,44.392 60.481,44.392 60.531,44.442 v2@60.555,44.442 ; v2(60.558,44.442) v2@60.555,44.442 ; U1.1H2@60.625,40.575 v2(61.092,40.638) U1.1G3@61.125,41.075 ; U1.1B2@60.625,43.575 60.625,44.371 v2@60.555,44.442 ; v2(60.841,36.854) 61.289,36.854 61.303,36.84 61.36,36.84 U1.AC11@61.375,36.825 ; U1.1J3@61.125,40.075 v2(61.625,40.089) ; U1.1A3@61.125,44.075 61.132,44.082 v2@61.132,44.466 ; U1.1K4@61.625,39.575 v2(61.625,40.089) ; U1.1H4@61.625,40.575 v2(62.15,40.625) U1.1G5@62.125,41.075 ; U1.1B4@61.625,43.575 61.625,44.405 v2(61.725,44.505) ; U1.F12@61.875,45.325 v2(61.875,45.825) ; U1.1J5@62.125,40.075 v2(61.625,40.089) ; U1.1A5@62.125,44.075 62.496,44.446 62.571,44.446 62.625,44.5 U1.1B6@62.625,43.575 ; U1.1K6@62.625,39.575 v2(62.7,40.075) U1.1J7@63.125,40.075 ; U1.1F6@62.625,41.575 62.625,41.95 v2(62.65,41.975) ; v2@62.657,41.975 62.718,41.975 62.818,42.075 U1.1E7@63.125,42.075 ; U1.F14@62.875,45.325 v2(62.875,45.725) ; U1.1A7@63.125,44.075 v2(63.328,44.412) U1.1B8@63.625,43.575 U1.1A9@64.125,44.075 64.448,44.398 64.538,44.398 64.586,44.446 64.625,44.407 U1.1B10@64.625,43.575 U1.1A11@65.125,44.075 65.147,44.075 65.25,43.972 65.818,43.972 65.865,43.925 65.865,43.894 65.64,43.669 65.64,43.59 U1.1B12@65.625,43.575 ; U1.1K8@63.625,39.575 v2(64.198,39.575) U1.1K10@64.625,39.575 ; U1.1F8@63.625,41.575 v2(63.625,42.075) ; v2@63.853,45.725 U1.F16@63.875,45.325 ; U1.1E9@64.125,42.075 v2(64.625,42.075) U1.1F10@64.625,41.575 ; U1.1G11@65.125,41.075 v2(65.806,40.972) U1.1H12@65.625,40.575 ; U1.AG27@69.375,34.825 69.375,34.59 v2(69.768,34.197) ; v1(73.575,57.875) 73.646,57.804 73.911,57.804 74.056,57.66 74.42,57.66 U37.A6@74.425,57.655 ; v4@77.982,32 78.002,31.98 78.002,31.58 78.077,31.505 C146.1@78.183,31.4 ; U37.P4@80.925,56.655 v2(81.325,56.655) ; v4@86.857,39.625 v4(86.857,39.595) 86.857,39.577 U2.J2@87.258,39.177 ; U2.J8@87.258,34.377 87.653,34.772 87.653,35.46 87.457,35.655 v4(87.457,35.75) ; v4(88.307,40.715) 88.374,40.648 88.374,40.553 88.387,40.54 88.387,40.506 88.757,40.136 88.757,40.129 88.858,40.028 U2.G1@88.858,39.977 ; v4@90.132,40.55 90.194,40.488 90.194,40.24 U2.E1@90.458,39.977 ; U2.E2@90.458,39.177 90.469,39.165 90.469,38.923 90.833,38.559 90.833,38.049 v4@90.857,38.025 ; v4(90.932,40.55) 90.994,40.488 90.994,40.24 U2.D1@91.258,39.977 ; v4(92.532,40.55) 92.599,40.483 92.599,40.273 92.673,40.199 92.673,40.188 92.857,40.003 U2.B1@92.857,39.975 ; U2.B3@92.858,38.377 92.895,38.339 92.895,38.011 v4@93.032,37.875 ; v4(104.792,47.037) 104.964,46.714 105.089,46.58 105.089,46.511 105.133,46.467 105.308,46.292 U8.G1@105.308,46.202 ; v4@106.582,46.775 106.649,46.708 106.649,46.546 106.932,46.263 U8.E1@106.932,46.2 ; v4@107.382,46.775 107.449,46.708 107.449,46.549 107.732,46.266 U8.D1@107.732,46.2 ; v4@108.982,46.775 109.049,46.708 109.049,46.546 109.332,46.263 U8.B1@109.332,46.2 ; 59.35,43.613 59.35,43.825 U1.J7@59.375,43.825 ; 59.35,43.613 U1.J7@59.375,43.825
  Top Layer w0.16: U1.1J9@64.125,40.075 v2(64.625,40.143) ; U1.1J11@65.125,40.075 65.435,40.075 v2(65.53,40.17) ; v2(65.15,39.65) 65.55,39.65 U1.1K12@65.625,39.575
  Top Layer w0.2: v1@11.386,33.645 LD11.2@11.386,34.522 ; U26.27@31.67,46 32.079,46 32.27,46.191 32.27,46.91 v3@32.316,46.956 ; v3(32.17,46.93) v3@32.227,46.873 ; C248.1@58.683,33.002 C250.1@58.683,33.572 58.683,34.08 v2(58.816,34.213) ; U37.C4@75.425,56.655 75.875,57.105 75.885,57.105 v1(75.925,57.145) ; U37.E7@76.425,58.155 76.575,58.305 77.17,58.305 v1(77.675,57.8) ; v1(77.25,56.63) 77.25,56.718 77.425,56.893 U37.G5@77.425,57.155 ; v1(77.575,59.08) 77.925,59.43 U37.H10@77.925,59.655 ; U37.J5@78.425,57.155 78.425,56.85 78.55,56.725 v1(78.55,56.63) ; U37.K8@78.925,58.655 79.175,58.655 v1(79.45,58.93) ; U37.N5@80.425,57.155 U37.P6@80.925,57.655 81.305,57.655 v1(81.6,57.95) ; U2.M1@84.858,39.977 84.896,40.015 84.896,40.322 84.958,40.384 84.958,40.449 v4@84.883,40.524 ; v4@88.857,33.05 U2.G9@88.857,33.574 ; U2.G9@88.857,33.575 U2.G8@88.858,34.389 ; v4@89.658,33.102 U2.F9@89.658,33.577 ; v4(97.982,46.962) 97.982,46.35 U8.T1@98.132,46.2 ; U8.T1@98.12,46.262 U8.T1@98.134,46.203 ; v4(101.13,46.724) 101.13,46.642 101.303,46.469 101.303,46.231 U8.M1@101.333,46.202 ; v4(103.182,46.7) 103.332,46.55 103.332,46.006 103.693,45.645 103.693,45.438 U8.J2@103.732,45.4
  Top Layer w0.21: v3(24.675,46.975) 24.675,47.375 24.88,47.58 26.109,47.58 26.3,47.389 U26.41@26.3,46.97 ; 24.775,42.8 U26.52@25.33,42.8 ; 24.775,44.8 U26.47@25.33,44.8 ; U26.36@28.3,46.97 28.3,47.525 ; U26.9@29.1,40.63 29.1,39.42 v3(29.568,38.952) ; U26.10@29.5,40.63 29.5,39.734 30.135,39.099 30.135,38.72 29.87,38.456 v3(29.87,38.377) ; U26.18@31.67,42.4 32.472,42.4 v3(32.772,42.1) ; U26.22@31.67,44 32.225,44
  Top Layer w0.25: v3(23.008,44.625) 23.056,44.673 23.257,44.673 23.384,44.8 24.775,44.8 ; v3(24.187,42.563) 24.221,42.563 24.459,42.8 24.775,42.8 ; v3(28.225,48.775) 28.225,48.214 28.3,48.139 28.3,47.525 ; 32.225,44 32.83,44 ; v3@32.757,42.1 v3(32.772,42.1) ; v2(52.841,36.352) 52.569,36.08 52.415,36.08 C86.2@52.285,35.95 52.26,35.95 52.061,35.75 50.196,35.75 v2(50.05,35.897) v2(50.05,38.554) 50.196,38.7 52.06,38.7 C81.2@52.285,38.475 v2(52.85,38.475) ; v1(53.329,32.955) 53.729,33.355 53.729,33.416 C92.2@53.859,33.546 ; X2.2@54.234,32.51 53.467,32.51 53.467,31.513 53.987,30.993 55.284,30.993 X2.4@55.284,31.76 ; v1(56.293,30.993) C90.1@56.293,31.61 ; C167.1@111.633,36.35 111.65,36.368 v2(111.65,36.957)
  Top Layer w0.275: U8.J8@103.732,40.6 v4@104.107,40.225 ; U8.G9@105.333,39.802 v4(105.732,40.2) ; U8.G8@105.333,40.602 U8.G8@105.332,40.6 v4(105.732,40.2) v4(105.732,40.2) U8.F9@106.133,39.802 ; U8.F9@106.133,39.815 106.14,39.815 106.538,40.214 106.538,40.221 U8.E8@106.919,40.602 ; v4@107.307,41 107.319,41 107.73,40.589 U8.D8@107.733,40.589
  Top Layer w0.3: v1@6.347,40.012 v1@6.347,41.812 ; v1@6.347,43.574 v1@6.347,45.374 ; B2.1@6.795,29.854 6.795,27.98 v1(6.8,27.975) ; v3(17.395,44.79) C43.1@18.055,44.79 ; v3(20.385,45.75) C40.1@20.995,45.75 ; v3(20.385,46.575) C39.1@20.995,46.575 ; v3@24.725,36.81 C217.2@24.725,37.42 ; v3@24.727,34.58 C219.1@24.727,35.185 ; v3(25.5,35.61) C216.1@25.5,36.215 ; v3(26.165,35.55) C215.2@26.775,35.55 ; v3@27.6,34.69 C214.2@27.6,35.3 ; C213.1@28.175,37.27 v3(28.785,37.27) ; v3(28.24,34.68) C91.2@28.85,34.68 ; C208.2@29.675,34.68 v3(30.285,34.68) ; C209.1@30.35,36.42 v3(30.985,36.42) ; C61.1@31.625,38.57 v3(32.235,38.57) ; v3(31.85,34.84) R57.1@31.85,35.5 ; v3(33.2,35.93) C189.1@33.2,36.59 ; v3(34.025,35.99) C188.1@34.025,36.59 C188.1@34.025,36.65 ; v3(35.245,36.46) 35.248,36.462 35.248,37.062 C190.2@35.25,37.065 ; v2@50.979,31.565 v2(51,31.586) C33.1@51,32.3 ; v4(78.032,32.048) 78.032,31.994 78.077,31.948 C146.1@78.077,31.505 ; C103.1@80.858,31.6 80.858,31.79 81.453,32.386 v4(81.566,32.386) ; v4(81.507,40.925) 81.507,40.138 81.657,39.988 U2.T1@81.657,39.975 ; R144.1@82.458,30.75 C104.1@82.458,31.6 82.458,31.877 v4(82.858,32.275) v4(82.858,32.275) ; U2.M9@84.858,33.577 U2.M9@84.857,33.575 85.357,33.075 v4(85.357,32.325) ; v4@85.345,32.313 v4(85.357,32.325) ; R145.1@86.73,30.725 86.684,30.771 86.611,30.771 85.907,31.475 C137.1@85.907,31.6 85.357,32.15 v4(85.357,32.325) ; U2.E8@90.457,34.375 v4(90.857,34.775) U2.D8@91.257,34.375 ; C101.1@92.907,30.55 92.907,30.675 92.737,30.845 92.692,30.845 92.582,30.955 92.582,31.675 92.613,31.706 92.613,33.043 92.595,33.062 92.633,33.101 92.633,33.323 92.861,33.552 92.861,33.575 U2.A9@93.657,33.575 ; C111.1@97.731,37.975 97.731,38.273 v4@98.058,38.6 ; C114.1@99.258,37.825 99.258,36.45 R149.1@99.708,36 ; C114.1@99.269,37.913 99.339,37.983 v4@99.339,38.633 ; U8.M9@101.332,39.8 101.333,39.785 101.707,39.411 101.707,38.55 101.744,38.512 C120.1@101.744,38.014 ; C120.1@101.782,37.9 C120.1@101.819,37.862 ; R150.1@105.032,37.825 105.032,37.92 105.332,38.219 U8.G9@105.332,39.8 ; U8.F9@106.133,39.802 U8.F9@106.133,39.815 ; U8.E2@106.932,45.4 U8.E1@106.932,46.178 ; v4(108.91,44.2) 108.931,44.2 U8.B3@109.331,44.6 ; U8.B9@109.333,39.802 U8.B9@109.346,39.802 ; C110.1@109.733,36.877 109.733,37.002 109.73,37.002 109.482,37.25 109.482,39.071 109.332,39.221 v4(109.332,39.275) 109.332,39.8 U8.B9@109.332,39.8 U8.A9@110.132,39.8 ; U8.A9@110.119,39.802 U8.A9@110.133,39.802 ; v2(112.8,48.676) 112.8,48.999 112.82,49.019 112.82,49.2 C177.1@112.925,49.305
  Top Layer w0.5: v1@6.353,40.006 C147.2@7.936,40.006 ; v1@6.353,40.906 C147.2@7.936,40.906 ; v1@6.353,41.818 C147.2@7.936,41.818 ; v1@6.353,43.568 C42.2@7.936,43.568 ; v1@6.353,44.468 C42.2@7.936,44.468 ; v1@6.353,45.38 C42.2@7.936,45.38
  Bottom Layer w0.15: v2(59.931,45.892) v2@59.935,45.896 ; C57.1@62.592,39.603 62.683,39.694 62.683,40.058 v2(62.7,40.075) 63.066,40.075 63.154,39.987 C60.1@63.154,39.672 ; v2(62.875,45.725) 62.875,46.219 62.95,46.294 C195.1@62.95,46.787 ; C52.1@63.162,41.607 63.162,41.944 63.293,42.075 v2(63.625,42.075) 63.844,41.856 C53.1@64.083,41.856 ; C67.1@63.4,45.5 63.586,45.686 63.807,45.686 v2@63.859,45.738 ; v2(63.85,45.725) 64.278,45.725 C69.1@64.305,45.752 ; v2@63.85,45.775 C239.1@63.85,46.787 ; v2(64.625,42.075) 64.706,41.994 C54.1@64.706,41.579 ; 68.39,33.919 68.669,34.197 v2(69.768,34.197) ; C121.1@104.783,46.36 C121.1@104.792,46.369 ; C119.1@107.333,46.17 C119.1@107.382,46.22 ; C122.1@112.475,43.758 112.479,43.754 C122.1@112.483,43.75 ; C125.1@112.475,45.533 112.479,45.529 C125.1@112.483,45.525
  Bottom Layer w0.2: v2(55.55,38.085) 55.663,38.198 C234.1@56.064,38.198 ; C237.1@56.696,44.88 C236.1@57.345,44.88 ; C192.1@56.8,45.55 C201.1@57.375,45.55 57.825,45.1 57.825,44.912 v2(57.862,44.875) 57.862,44.894 57.881,44.914 57.974,44.914 58.163,45.103 58.163,45.282 C197.1@58.216,45.334 ; C236.1@57.35,44.875 v2(57.862,44.875) ; C240.1@59.05,44.3 59.37,43.98 59.484,43.98 59.534,43.93 C220.1@59.534,43.856 ; v2(59.325,43.4) 59.325,43.408 59.534,43.617 59.534,43.781 C220.1@59.609,43.856 C220.1@59.534,43.931 ; v2@59.902,45.948 C205.1@59.902,46.829 ; C45.1@60.173,43.895 60.235,43.957 60.235,44.124 60.248,44.137 60.248,44.139 60.551,44.442 v2(60.558,44.442) ; C71.1@60.34,39.635 60.491,39.786 60.491,40.066 v2(60.525,40.1) ; v2@60.624,44.485 60.726,44.383 60.726,44.075 C51.1@60.813,43.988 ; C72.1@60.905,39.698 60.956,39.749 60.956,40.021 61.092,40.157 v2(61.092,40.638) ; C46.1@60.915,41.105 60.915,40.815 v2(61.092,40.638) ; v2@61.132,44.466 61.132,44.444 61.302,44.274 61.302,44.062 C49.1@61.377,43.987 ; C73.2@61.467,39.624 61.542,39.699 61.542,39.952 61.625,40.035 v2(61.625,40.089) ; C47.2@61.476,41.081 61.476,40.694 61.42,40.638 v2(61.092,40.638) ; C74.1@62.03,39.683 62.03,39.955 62.15,40.075 v2(62.15,40.625) 62.038,40.737 C48.1@62.038,41.107 ; C63.1@62.581,44.08 62.636,44.08 62.636,44.483 v2@62.625,44.494 ; C62.2@63.156,43.924 63.156,44.24 v2(63.328,44.412) 63.366,44.374 63.421,44.374 63.6,44.195 63.6,44.059 C65.2@63.675,43.984 ; C59.1@63.714,40.036 64.111,40.036 64.198,39.949 v2(64.198,39.575) ; C68.1@64.239,43.997 64.314,44.072 64.314,44.284 64.437,44.408 64.548,44.408 v2@64.586,44.446 ; C58.1@64.607,39.247 64.607,40.125 v2(64.625,40.143) ; C66.1@64.915,44.871 C66.1@64.84,44.796 ; C76.1@65.274,39.198 65.274,39.526 v2(65.15,39.65) 65.169,39.669 65.169,39.809 v2(65.53,40.17) 65.557,40.17 65.677,40.05 C77.2@66.25,40.05 ; C82.1@65.352,41.053 65.433,40.972 v2(65.806,40.972) 65.844,41.01 65.844,41.178 C75.1@66.083,41.417 ; C238.1@65.483,44.894 65.385,44.796 C66.1@64.84,44.796 ; R1.1@66.4,44.15 66.275,44.025 66.225,44.025 66.146,43.946 65.886,43.946 65.865,43.925 65.851,43.939 65.436,43.939 65.375,44 C64.1@64.85,44 64.804,44 64.8,43.996 64.725,44.071 64.725,44.307 v2@64.586,44.446 ; C118.1@75.26,56.98 75.425,57.145 v1(75.925,57.145) 76.11,56.96 C148.1@76.11,56.305 ; C9.1@76.615,59.48 76.77,59.325 77.008,59.325 77.208,59.126 77.529,59.126 v1(77.575,59.08) C117.1@77.575,59.864 ; C130.1@77.027,55.505 77.027,56.407 v1(77.25,56.63) ; v2(81.325,56.655) 81.615,56.655 C128.1@82.015,56.255 82.015,55.592 81.858,55.435 81.505,55.435 v1(81.475,55.405) ; v2@64.586,44.446 64.623,44.446 64.84,44.663 C66.1@64.84,44.796
  Bottom Layer w0.25: C253.1@67.941,34.367 68.39,33.919 68.39,33.638 C251.1@68.44,33.588 ; C253.1@67.941,34.385 C246.1@67.941,34.986
  Bottom Layer w0.3: C88.1@46.382,43.465 46.439,43.522 46.897,43.522 47.189,43.814 CN12.2@47.189,46.897 ; C87.1@50.485,43.888 v2(50.485,44.466) ; v2(57.872,36.74) 57.891,36.721 57.891,36.682 58.133,36.44 58.216,36.44 C244.1@58.325,36.331 58.325,35.675 C235.1@58.275,35.625 ; C70.2@59.775,39.625 59.506,39.894 59.506,40.25 59.456,40.3 C225.1@59.425,40.3 59.451,40.326 59.886,40.326 v2(60.198,40.638) ; v2@59.902,45.948 59.931,45.919 v2(59.931,45.892) 59.958,45.892 60,45.85 C196.1@60.525,45.85 ; C44.2@60.351,41.105 60.217,40.971 60.217,40.657 v2(60.198,40.638) ; v2(60.525,40.1) 60.506,40.119 60.506,40.33 v2(60.198,40.638) ; v2(61.725,44.505) 61.725,44.478 61.75,44.453 61.75,44.284 61.875,44.159 61.875,44.025 C50.1@61.9,44 ; C55.1@62.6,41.475 62.604,41.479 62.604,41.901 62.65,41.948 v2(62.65,41.975) ; v2@65.984,31.527 v2(66.003,31.546) 66.023,31.565 66.243,31.565 66.449,31.771 66.449,32.645 66.258,32.836 66.258,34.855 66.2,34.914 C252.1@66.2,36.324 ; v1(75.5,62.9) v1@75.51,62.91 ; C100.1@81.432,42.973 81.469,42.935 81.469,41.835 81.507,41.798 v4@81.507,40.923 ; v4@86.857,39.623 86.895,39.661 86.988,39.661 87.449,40.123 87.457,40.123 87.632,40.298 87.682,40.298 88.018,40.634 88.268,40.634 v4@88.307,40.673 ; C102.1@88.408,40.002 88.307,40.103 v4(88.307,40.715) 88.307,40.725 88.382,40.725 R142.1@89.008,41.35 ; C107.1@92.507,41.05 92.526,41.031 92.526,40.642 92.532,40.637 v4(92.532,40.55) ; v4(93.032,37.85) 93.032,37.902 93.227,38.097 93.227,38.568 C105.1@93.332,38.673 ; R156.1@95.033,47.925 95.138,48.03 95.34,48.03 95.84,48.53 95.938,48.53 96.046,48.638 96.046,48.736 97.082,47.7 97.758,47.7 97.856,47.798 97.943,47.711 97.963,47.67 v4(97.982,46.962) ; C126.1@98.283,34.375 v1(98.95,34.375) ; v2(99.05,52.45) 99.05,51.758 C132.1@99.058,51.75 ; C127.1@100.208,34.375 v1(100.9,34.375) ; v2(100.9,52.425) 100.908,52.417 C133.1@100.908,51.75 ; C139.1@102.108,34.375 v1(102.775,34.375) ; C131.1@102.833,51.75 v2(102.833,52.425) ; C140.1@104.008,34.375 v1(104.675,34.375) ; C129.1@104.758,51.75 v2(104.758,52.425) ; C121.1@104.792,46.369 v4(104.792,47.037) ; C135.1@105.833,35.9 v1(106.525,35.9) ; C113.1@106.583,46.17 v4(106.582,46.8) 106.982,47.2 R147.1@106.982,48.685 ; C119.1@107.382,46.22 v4(107.382,46.8) ; C134.1@107.608,35.925 v1(108.275,35.925) ; v1(108.125,52.475) 108.129,52.471 108.129,51.761 C123.1@108.132,51.758 ; v4@108.981,46.773 109.019,46.81 109.019,47.385 C112.1@109.056,47.423 ; C124.1@109.133,36.075 109.283,35.925 v1(109.95,35.925) ; v2(112.475,44.35) 112.479,44.346 C122.1@112.479,43.754 ; v2(112.475,46.125) 112.479,46.121 C125.1@112.479,45.529 ; C136.1@112.483,41.875 v2(112.483,42.47)
  other v1: 101.286,0.805 104,0.805 2.175,0.83 4.6,0.83 7.05,0.83 9.875,0.83 12.9,0.83 15.825,0.83 18.386,0.83 20.886,0.83 23.386,0.83 25.886,0.83 28.386,0.83 30.886,0.83 33.711,0.83 36.211,0.83 38.711,0.83 41.211,0.83 43.711,0.83 46.211,0.83 48.361,0.83 50.861,0.83 53.361,0.83 56.336,0.83 58.836,0.83 61.336,0.83 63.836,0.83 66.336,0.83 68.836,0.83 71.661,0.83 74.161,0.83 76.661,0.83 79.161,0.83 81.661,0.83 84.161,0.83 86.311,0.83 88.811,0.83 91.311,0.83 93.811,0.83 96.311,0.83 98.811,0.83 107.3,0.83 109.425,0.83 111.725,0.83 113.975,0.83 116.325,0.83 118.625,0.83 0.825,1.625 118.625,2.85 0.825,3.225 0.825,4.775 118.625,5.35 0.825,6.5 118.625,7.85 0.825,8.475 118.625,10.35 0.825,10.975 118.625,12.85 0.825,13.475 118.625,15.35 0.825,15.975 118.625,17.85 0.825,18.475 118.625,20.35 0.825,20.975 51.35,21.475 118.625,22.85 0.825,23.475 53.8,23.875 118.625,25.35 0.825,25.975 53.467,26.55 43.063,27.05 118.625,27.85 0.825,28.475 67.73,28.759 45.909,29.117 47.672,29.202 118.625,30.35 44.087,30.462 46.975,30.5 0.825,30.975 49.725,31.6 118.625,32.85 0.825,33.475 47.112,33.546 11.387,33.648 47.125,34.425 48.2,34.42 35.35,34.945 118.625,35.35 0.825,35.975 47.625,36.3 118.625,37.85 0.825,38.5 6.348,40.014 118.625,40.35 6.348,40.914 0.825,41 6.348,41.814 118.625,42.85 0.825,43.5 6.348,43.576 6.348,44.476 47.189,44.713 118.625,45.35 6.348,45.376 0.825,46 45.995,47.305 118.625,47.85 0.825,48.5 118.625,50.35 0.825,51 42.535,51.865 118.625,52.85 0.825,53.5 81.406,54.265 82.774,54.265 84.406,54.265 118.625,55.35 0.825,56 118.625,57.85 0.825,58.5 50.45,60.275 54.195,60.275 118.625,60.35 0.825,61 118.625,62.85 0.825,63.5 54.175,63.5 50.45,63.575 118.625,65.35 0.825,66 42.575,65.995 118.625,67.85 0.825,68.5 118.625,70.35 0.825,70.575 118.625,72.85 0.825,73.5 118.625,75.35 0.825,75.5 0.825,77.825 118.625,77.85 3.6,78.75 6.35,78.775 8.85,78.775 11.436,78.775 13.936,78.775 16.436,78.775 18.936,78.775 21.436,78.775 23.936,78.775 26.761,78.775 29.261,78.775 31.761,78.775 34.261,78.775 36.761,78.775 39.261,78.775 41.411,78.775 43.911,78.775 46.411,78.775 49.425,78.775 51.925,78.775 54.511,78.775 57.011,78.775 59.511,78.775 62.011,78.775 64.511,78.775 67.011,78.775 69.836,78.775 72.336,78.775 74.836,78.775 77.336,78.775 79.836,78.775 82.336,78.775 84.486,78.775 86.986,78.775 89.486,78.775 92.5,78.775 95,78.775 97.586,78.775 100.086,78.775 102.586,78.775 105.086,78.775 107.586,78.775 110.086,78.775 112.911,78.775 115.411,78.775
  other v2: 46.475,16.55 48.075,31.55 42.551,31.633 43.9,33 43.902,34.655 43.902,36.305 65.87,43.91 64.55,44.448 61.1,44.49 62.606,44.48 54.694,47.6 27.875,58.675 21.675,60.437
  other v3: 24.722,34.61 27.6,34.64 24.725,36.76 20.325,40.75 13.124,40.798 13.625,40.798 14.126,40.798 14.924,40.798 15.425,40.798 15.926,40.798 16.724,40.798 17.225,40.798 17.726,40.798 18.524,40.798 19.025,40.798 19.526,40.798 21.924,41.202 22.425,41.202 20.325,41.25 38.304,41.9 40.104,41.9 41.904,41.9 26.85,42.15 28.5,42.15 30.15,42.15 13.85,42.2 36.42,42.375 38.304,42.401 40.104,42.401 41.904,42.401 13.85,42.7 36.42,42.875 27.675,42.975 29.325,42.975 13.85,43.5 26.85,43.8 28.5,43.8 30.15,43.8 33.28,43.875 13.85,44 27.675,44.625 29.325,44.625 13.85,44.8 13.85,45.3 26.85,45.45 28.5,45.45 30.15,45.45 36.05,46.325 36.05,46.825 36.075,47.975 36.075,48.475 37.15,48.575 37.65,48.575 38.45,48.575 38.95,48.575 39.75,48.575 40.25,48.575 41.05,48.575 41.55,48.575 24.85,48.823 24.85,49.323 23.775,51.123 24.276,51.123 19.45,53.623 19.951,53.623 20.75,53.623 21.251,53.623 22.05,53.623 22.551,53.623 35.7,54.575 36.2,54.575 36.975,54.575 37.475,54.575 38.25,54.575 38.75,54.575 39.525,54.575 40.025,54.575 23.824,55.425 24.325,55.425 24.826,55.425 25.674,55.425 26.175,55.425 26.676,55.425 27.524,55.425 28.025,55.425 28.526,55.425
  other v4: 88.857,33.025 89.657,33.025 92.582,33.075 90.857,37.995 99.382,38.55 101.732,38.55 104.132,40.2 106.532,40.2 90.133,40.575 107.332,41 108.982,46.8
HSE_IN: C90.2 U1.AG2 X2.1 | length 3.6
  Top Layer w0.1: X2.1@55.284,32.51 56.318,32.51 56.814,33.005 56.814,34.464 56.875,34.525 U1.AG2@56.875,34.825
HSE_OUT: R75.2 U1.AF2 | length 2
  Top Layer w0.09: 56.59,34.075 56.59,34.686 56.625,34.721 56.625,35.075 U1.AF2@56.875,35.325
  Top Layer w0.1: R75.2@56.409,33.546 56.59,33.727 56.59,34.075
I2C7.SCL: R261.1 U1.E15 U26.33 | length 74.8
  Top Layer w0.1: U1.E15@63.375,45.825 v2(63.375,46.25)
  Top Layer w0.15: U26.33@29.5,46.97 29.5,47.5 29.35,47.65 29.35,50.812 v3(29.763,51.225)
  Bottom Layer w0.1: R261.1@29.785,50.583 29.743,50.626 29.743,51.265 30.406,51.929 30.917,51.929 33.493,54.505 33.493,55.016 46.487,68.01 65.588,68.01 69.733,63.865 69.733,54.412 63.375,48.054 v2(63.375,46.25)
I2C7.SDA: R260.1 U1.E19 U26.34 | length 76.8
  Top Layer w0.125: U1.E19@65.375,45.825 65.375,45.44 v2@65.39,45.425
  Top Layer w0.15: U26.34@29.1,46.97 v3(29.1,51.225)
  Bottom Layer w0.1: R260.1@28.81,50.583 28.9,50.583 29.08,50.763 v3@29.08,51.228 ; v3@29.093,51.228 30.141,52.275 30.771,52.275 33.099,54.603 33.099,55.234 46.115,68.25 65.899,68.25 70.009,64.14 70.009,54.304 64.91,49.206 64.91,47.299 65.74,46.469 65.74,45.76 v2(65.39,45.41)
MP257_WAKEUP: U1.AF5 U26.32 | length 59.2
  Top Layer w0.09: 58.125,34.075 58.125,34.929 58.165,34.969 58.165,35.115 U1.AF5@58.375,35.325
  Top Layer w0.1: v2(43.751,50.58) 44.063,50.269 44.063,47.604 45.995,45.672 45.995,43.285 43.631,40.921 43.631,39.348 43.2,38.916 43.2,31.993 45.395,29.797 48.212,29.797 48.525,29.485 53.864,29.485 53.889,29.46 55.786,29.46 55.811,29.485 56.828,29.485 57.032,29.69 57.602,29.69 58.106,30.195 58.106,30.747 58.125,30.765 58.125,34.075
  Top Layer w0.15: v3(29.8,48.4) 29.8,47.653 29.9,47.553 U26.32@29.9,46.97
  Bottom Layer w0.1: v3@29.78,48.403 30.361,48.403 30.78,48.823 30.78,49.661 31.898,50.778 43.543,50.778 43.74,50.58 v2(43.751,50.58)
NetB2_2: B2.2 C219.2 U26.1 | length 28.3
  Top Layer w0.15: B2.2@6.795,36.354 8.721,36.354 10.438,34.637 10.438,33.673 11.036,33.075 12.162,33.075 13.713,34.625 20.219,34.625 20.845,33.999 23.799,33.999 24.2,34.4 24.2,35.825 24.347,35.972 24.554,35.972 C219.2@24.727,36.145 24.562,36.31 24.338,36.31 24.187,36.46 24.187,39.008 24.962,39.783 24.962,40.237 25.355,40.63 U26.1@25.9,40.63
NetC43_2: C43.2 U26.45 | length 6.7
  Top Layer w0.21: 24.775,45.6 U26.45@25.33,45.6
  Top Layer w0.25: C43.2@19.015,44.79 21.731,44.79 22.176,45.235 22.451,45.235 22.816,45.6 24.775,45.6
NetC81_1: C81.1 R64.2 X1.1 | length 2.1
  Top Layer w0.1: X1.1@51.059,37.975 51.459,37.575 C81.1@52.285,37.575 R64.2@53.035,37.575
NetC88_2: C88.2 D6.2 R66.2 | length 2.9
  Bottom Layer w0.2: C88.2@46.382,42.565 46.424,42.523 D6.2@47.673,42.523 47.792,42.523 48.192,42.923 R66.2@48.192,43.796
NetC92_1: C92.1 R75.1 X2.3 | length 2.9
  Top Layer w0.1: X2.3@54.234,31.76 54.461,31.987 54.694,31.987 54.759,32.052 C92.1@54.759,33.546 R75.1@55.509,33.546
NetC120_2: C120.2 R148.1 R149.2 U8.M8 | length 5.2
  Top Layer w0.175: v4@101.118,38.785 v4(101.132,38.8) 101.132,38.883 100.944,39.071 100.944,40.213 U8.M8@101.333,40.602
  Top Layer w0.3: R149.2@100.608,36 101.124,36.516 R148.1@101.124,36.946 100.908,37.162 C120.2@100.908,37.825 ; C120.2@100.883,37.902 101.118,38.137 v4@101.118,38.785
NetC121_2: C121.2 R146.1 R147.2 U8.H1 | length 4.6
  Top Layer w0.15: v4(103.992,46.992) 103.992,46.897 104.104,46.785 104.104,46.733 104.434,46.403 104.434,46.365 104.532,46.267 U8.H1@104.532,46.2
  Bottom Layer w0.3: C121.2@103.883,46.36 103.992,46.469 v4(103.992,46.992) 104.735,47.735 R146.1@105.108,47.735 ; R146.1@105.132,47.735 R146.1@105.108,47.735 ; R147.2@106.082,48.685 105.955,48.685 105.108,47.838 R146.1@105.108,47.735
NetC130_2: C130.2 C148.2 U37.C2 | length 3.5
  Top Layer w0.09: U37.C2@75.425,55.655 75.675,55.405 v1(75.675,54.605)
  Bottom Layer w0.25: C148.2@76.11,55.405 75.675,54.97 v1(75.675,54.605) C130.2@77.027,54.605
NetC137_2: C137.2 R143.1 R144.2 U2.M8 | length 5.6
  Top Layer w0.2: R144.2@83.358,30.75 R144.2@83.379,30.771 ; U2.M8@84.857,34.375 84.457,33.975 84.457,33.409 84.657,33.209 v4(84.657,32.575) 84.752,32.48 84.752,31.855 C137.2@85.007,31.6
  Top Layer w0.3: R144.2@83.379,30.771 84.183,30.771 84.835,30.771 85.007,30.943 C137.2@85.007,31.6
NetC138_2: C138.2 R141.1 R142.2 U2.H1 | length 5.2
  Top Layer w0.1: v4@86.907,40.375 87.607,40.375 87.957,40.025 U2.H1@88.058,40.025
  Bottom Layer w0.3: v4@86.907,40.373 87.102,40.568 87.102,40.668 C138.2@87.632,41.198 ; C138.2@87.658,41.2 88.758,42.3 R141.1@89.933,42.3
  other v4: 86.907,40.4
NetC151_2: C151.2 C252.2 C260.2 R11.2 U1.AB20 U1.AB22 U1.AC21 | length 9
  Top Layer w0.15: U1.AB20@65.875,37.325 65.875,37.607 65.95,37.682 v2@65.95,37.75 ; U1.AC21@66.375,36.825 v2@66.732,36.825
  Top Layer w0.16: U1.AB22@66.875,37.325 66.875,36.95 v2(66.9,36.925)
  Bottom Layer w0.15: v2(65.969,37.735) 65.95,37.716 65.95,37.205 66.167,36.988 66.167,36.95 66.367,36.75 66.466,36.75 66.821,36.395
  Bottom Layer w0.25: v2(66.9,36.925) 66.875,36.9 66.875,36.449 66.75,36.324 66.75,35.714 66.75,33.083 67,32.833 R11.2@67,31.075
NetC208_1: C208.1 U26.8 | length 5.4
  Top Layer w0.21: U26.8@28.7,40.63 28.7,39.134 29.125,38.709 29.125,38.345 29.298,38.172
  Top Layer w0.3: 29.298,38.172 29.8,37.67 29.8,36.843 29.675,36.718 C208.1@29.675,35.705
NetC225_2: C225.2 U1.R7 | length 1.1
  Top Layer w0.1: U1.R7@59.375,40.825 v2@59.375,41.41
  Bottom Layer w0.1: C225.2@59.375,40.95 C225.2@59.425,40.9
  Bottom Layer w0.3: C225.2@59.375,40.95 v2@59.375,41.41
  other v2: 59.41,41.41
NetC235_2: C235.2 C244.2 R267.1 U1.AB6 | length 3.2
  Top Layer w0.09: v2(58.875,36.825) U1.AB6@58.875,37.325
  Bottom Layer w0.2: R267.1@58.223,34.723 58.734,34.723 58.875,34.864 C235.2@58.875,35.625 C244.2@58.875,36.331 v2(58.875,36.825)
NetC251_2: C251.2 R286.2 U1.AE21 U1.AE22 | length 4.3
  Top Layer w0.09: U1.AE21@66.375,35.825 U1.AE22@66.875,35.825 ; U1.AE22@66.902,35.798 67.125,35.575 67.125,35.221 67.295,35.052 67.295,33.593 v2(67.3,33.588)
  Top Layer w0.1: U1.AE22@66.875,35.825 U1.AE22@66.902,35.798
  Bottom Layer w0.3: v2(67.3,33.588) C251.2@67.89,33.588 R286.2@67.89,32.815
NetCN12_1: CN12.1 R66.1 | length 3.2
  Bottom Layer w0.2: CN12.1@48.425,46.801 48.425,45.241 49.083,44.583 R66.1@49.083,43.917
NetD6_1: D6.1 R67.1 | length 1.4
  Bottom Layer w0.3: R67.1@46.3,40.575 47.625,40.575 D6.1@47.673,40.623
NetD7_1: D7.1 R248.1 U37.K5 | length 5.7
  Top Layer w0.2: v1(78.375,57.705) U37.K5@78.925,57.155
  Bottom Layer w0.2: v1(78.375,57.705) 79.125,58.455 79.682,58.455 R248.1@80.207,58.98 80.207,61.55 D7.1@80.195,61.563
NetL1_1: L1.1 U26.37 | length 4.2
  Top Layer w0.21: U26.37@27.9,46.97 27.9,47.525
  Top Layer w0.25: L1.1@27.7,51.135 27.7,48.173 27.9,47.973 27.9,47.525
NetL2_1: L2.1 U26.26 | length 6
  Top Layer w0.09: 32.725,48.56 32.725,49.26 33.433,49.968 33.56,49.968 33.915,50.323 L2.1@33.915,50.45
  Top Layer w0.2: U26.26@31.917,45.6 32.4,45.6 32.725,45.925 32.725,48.56
NetL3_1: L3.1 U26.40 | length 5.9
  Top Layer w0.15: L3.1@21.698,48.162 L3.1@21.85,48.01
  Top Layer w0.21: L3.1@21.85,48.275 22.135,47.99 23.91,47.99 26.265,47.99 26.7,47.555 U26.40@26.7,46.97
NetL4_1: L4.1 U26.23 | length 3.8
  Top Layer w0.15: L4.1@35.36,43.885 L4.1@35.36,44.4
  Top Layer w0.21: U26.23@31.67,44.4 32.225,44.4
  Top Layer w0.25: 32.225,44.4 35,44.4
NetL5_1: L5.1 U26.48 | length 7.2
  Top Layer w0.15: L5.1@19.618,42.448 L5.1@19.87,42.7 ; L5.1@20.09,42.585 L5.1@20.09,43.1
  Top Layer w0.21: 24.775,44.4 U26.48@25.33,44.4
  Top Layer w0.25: 19.825,43.6 20.275,44.05 23.2,44.05 23.55,44.4 24.775,44.4 ; L5.1@20.09,43.1 20.09,43.615
NetL6_1: L6.1 U26.19 | length 4.9
  Top Layer w0.21: U26.19@31.67,42.8 32.225,42.8
  Top Layer w0.25: 32.225,42.8 32.623,42.8 32.798,42.625 33.15,42.625 33.375,42.4 33.375,41.325 34.071,40.629 34.425,40.629 34.43,40.624 L6.1@34.43,40.025
NetL7_1: L7.1 U26.51 | length 7.4
  Top Layer w0.21: 24.775,43.2 U26.51@25.33,43.2
  Top Layer w0.25: L7.1@22.425,38.425 L7.1@22.425,38.669 ; L7.1@22.475,37.95 22.875,38.35 22.875,40.184 23.35,40.659 23.35,42.503 24.047,43.2 24.775,43.2
NetLD11_1: LD11.1 R210.2 | length 1
  Top Layer w0.2: LD11.1@11.386,36.022 R210.2@11.386,37.015
NetR1_2: R1.2 U1.K22 | length 1.2
  Top Layer w0.1: v2(66.78,42.92) 66.794,42.934 66.794,43.208 66.875,43.29 U1.K22@66.875,43.325
  Bottom Layer w0.15: R1.2@66.4,43.55 66.487,43.463 66.487,43.213 v2(66.78,42.92)
NetR46_2: R46.2 U26.30 | length 2.8
  Top Layer w0.15: U26.30@30.7,46.97 30.7,48.87 31.032,49.202 31.032,49.43 R46.2@31.15,49.548
NetR57_2: R57.2 U26.12 | length 4.9
  Top Layer w0.21: U26.12@30.3,40.63 30.3,40.016 30.47,39.845
  Top Layer w0.3: 30.47,39.845 31.025,39.291 31.025,38.174 31.85,37.349 R57.2@31.85,36.4
NetR59_2: R59.2 U26.54 | length 8.5
  Top Layer w0.15: R59.2@21.48,36.145 21.48,36.64 21.65,36.81 22.736,36.81 23.375,37.449 23.375,39.298 24.012,39.935 24.012,41.335 24.677,42 U26.54@25.33,42
NetR60_2: R60.2 U26.55 | length 7.1
  Top Layer w0.15: R60.2@22.53,36.145 22.604,36.145 23.625,37.166 23.625,39.194 24.262,39.832 24.262,41.232 24.631,41.6 U26.55@25.33,41.6
NetR61_2: R61.2 U26.56 | length 6.1
  Top Layer w0.15: R61.2@23.58,36.145 23.58,36.76 23.875,37.055 23.875,39.091 24.512,39.728 24.512,40.985 24.727,41.2 U26.56@25.255,41.2
NetR81_2: R81.2 U26.31 | length 5.7
  Top Layer w0.15: U26.31@30.3,46.97 30.3,48.973 30.45,49.123 30.45,51.81 30.538,51.898 R81.2@31.163,51.898
NetR145_2: R145.2 U2.L8 | length 3.8
  Top Layer w0.18: U2.L8@85.658,34.377 86.058,33.977 86.73,33.977 86.85,33.857 R145.2@86.85,31.5
NetR150_2: R150.2 U8.L8 | length 3.9
  Top Layer w0.09: U8.L8@102.132,40.6 102.532,40.2 103.057,40.2 103.282,39.975 103.282,39.55 104.132,38.7 R150.2@104.132,37.825
NetTP21_1: TP21.1 U37.H5 | length 1.7
  Top Layer w0.15: v2(77.925,56.755) U37.H5@77.925,57.155
  Bottom Layer w0.25: v2(77.925,56.755) 77.925,56.256 TP21.1@78.516,55.665
NRST: C33.2 R81.1 U1.AE1 | length 49.7
  Top Layer w0.09: 55.444,35.457 55.812,35.825 U1.AE1@56.375,35.825
  Top Layer w0.1: R81.1@31.163,52.798 31.163,53.273 33.565,55.675 39.786,55.675 41.873,53.588 41.873,53.551 44.541,50.883 44.541,47.949 46.497,45.992 46.497,42.556 43.821,39.879 43.821,39.269 43.443,38.89 43.443,35.633 45.978,33.097 50.897,33.097 C33.2@51,33.2 50.975,33.225 50.975,33.875 51.758,34.658 53.449,34.658 53.863,35.073 54.632,35.073 55.016,35.457 55.444,35.457
NRSTC1MS: D7.2 R27.1 R59.1 R272.1 U1.W3 | length 123.2
  Top Layer w0.09: 56.11,38.46 57.01,38.46 U1.W3@57.375,38.825
  Top Layer w0.1: R59.1@21.48,35.245 21.475,35.24 21.475,34.625 v1@21.49,34.61 ; v2(48.805,38.061) R27.1@48.805,38.872 48.805,38.904 49.542,38.904 49.831,39.194 49.936,39.194 49.938,39.192 50.559,39.192 50.561,39.194 52.93,39.194 53.474,38.65 54.531,38.65 54.787,38.394 55.077,38.394 55.319,38.635 55.764,38.635 55.939,38.46 56.11,38.46
  Bottom Layer w0.1: R272.1@21.505,33.882 21.505,34.595 21.49,34.61 21.49,34.694 21.972,35.176 ; v2(48.805,38.061) 48.805,38.016 48.314,37.526 43.556,37.526 43.288,37.258 43.288,35.651 41.626,33.989 26.279,33.989 25.092,35.176 21.972,35.176 ; D7.2@77.88,61.563 77.88,63.32 72.735,68.465 43.114,68.465 28.049,53.4 28.049,50.003 26.618,48.572 26.618,45.92 26.431,45.733 26.431,39.267 25.501,38.337 25.133,38.337 21.972,35.176
  other v1: 21.49,34.6
OSC32_IN: C86.1 U1.AA2 X1.2 | length 6.4
  Top Layer w0.09: 55.625,37.525 56,37.525 56.05,37.575 56.625,37.575 U1.AA2@56.875,37.825
  Top Layer w0.1: X1.2@51.059,36.475 51.434,36.85 53.271,36.85 53.296,36.875 54.052,36.875 54.702,37.525 55.625,37.525
OSC32_OUT: R64.1 U1.AA1 | length 2.5
  Top Layer w0.09: 56.05,37.825 U1.AA1@56.375,37.825
  Top Layer w0.1: R64.1@53.935,37.575 54.436,37.575 54.597,37.735 55.695,37.735 55.784,37.825 56.05,37.825
PMIC_WAKEUPn: R46.1 U1.W7 | length 46.6
  Top Layer w0.09: U1.W7@59.375,38.825 59.375,38.802 59.475,38.702 v2(59.475,38.325)
  Top Layer w0.1: R46.1@31.15,50.448 31.15,50.942 35.501,55.293 39.879,55.293 41.683,53.488 41.683,53.37 44.316,50.738 44.316,47.708 46.24,45.785 46.24,42.779 44.461,41 v2(44.43,41)
  Bottom Layer w0.09: v2(44.43,41) 44.43,39.527 44.833,39.123 56.341,39.123 57.139,38.325 57.851,38.325 58.206,37.97 58.492,37.97 58.637,38.115 59.265,38.115 v2(59.475,38.325)
  other v3: 31.15,51.033
PWR_CPU_ON: R60.1 R272.2 U1.AB4 | length 40.2
  Top Layer w0.09: 55.627,36.457 56.927,36.457 57.125,36.655 57.125,36.929 57.271,37.075 57.625,37.075 U1.AB4@57.875,37.325
  Top Layer w0.095: 55.57,36.455 55.625,36.455
  Top Layer w0.1: v1(22.5,34.6) 22.514,34.614 22.514,35.229 R60.1@22.53,35.245 ; v2(55.077,36.225) 55.307,36.455 55.57,36.455
  Bottom Layer w0.1: R272.2@22.405,33.882 22.936,33.882 23.265,33.553 37.33,33.553 38.666,32.217 48.438,32.217 49.9,33.679 49.9,34.006 51.228,35.335 54.815,35.335 55.083,35.603 v2@55.083,36.219 ; R272.2@22.471,34.068 22.5,34.097 v1(22.5,34.6)
PWR_ON: R61.1 U1.AD3 | length 36.9
  Top Layer w0.09: 56.084,36.26 57.09,36.26 57.128,36.298 57.348,36.298 U1.AD3@57.375,36.325
  Top Layer w0.1: v1(23.575,34.6) 23.58,34.605 R61.1@23.58,35.245 ; v1(49.475,33.855) 50.678,35.058 53.276,35.058 53.671,35.453 54.474,35.453 54.865,35.844 55.241,35.844 55.659,36.262 56.082,36.262
  Bottom Layer w0.1: v1(23.575,34.6) 24.4,33.775 37.982,33.775 39.197,32.561 48.18,32.561 v1(49.475,33.855)
VBAT: C87.2 D6.3 U1.T6 | length 12.2
  Top Layer w0.15: v2@58.875,39.933 U1.T6@58.875,40.325
  Bottom Layer w0.3: C87.2@50.485,42.988 50.485,42.185 50.423,42.123 50.423,41.923 50.073,41.573 D6.3@49.873,41.573 49.973,41.473 50.976,40.471 53.326,40.471 53.642,40.788 55.87,40.788 56.299,40.358 58.427,40.358 v2@58.864,39.921 ; v2@58.831,39.889 v2@58.864,39.921 ; v2(58.875,39.91) v2@58.864,39.921 ; v2@58.875,39.933 v2@58.864,39.921
VDD3V3_USB: C61.2 R286.1 U26.13 | length 50.7
  Top Layer w0.21: U26.13@30.7,40.63 30.7,40.2 31.163,39.737 31.418,39.737 31.42,39.735 31.49,39.735 31.625,39.6 C61.2@31.625,39.53
  Top Layer w0.3: C61.2@31.625,39.53 v3(32.235,39.53)
  Signal Layer 2 w0.3: 43.518,27.562 67.603,27.562 69.284,29.244 v1(69.284,30.569)
  Signal Layer 2 w0.5: v3(32.235,39.53) 35.12,39.53 37.15,37.5 37.15,33.93 43.518,27.562
  Bottom Layer w0.3: R286.1@67.89,31.915 67.898,31.908 68.514,31.908 69.284,31.138 v1(69.284,30.569)
VDD_DDR: C39.2 C41.2 C75.2 C76.2 C77.1 C82.2 C83.2 C100.2 C101.2 C102.2 C103.2 C104.2 C105.2 C106.2 C107.2 C108.2 C109.2 C110.2 C111.2 C112.2 C113.2 C114.2 C115.2 C116.2 C119.2 C146.2 C167.2 C177.2 C200.2 C202.2 L5.2 LNK8.2 R141.2 R143.2 R146.2 R148.2 U1.1C11 U1.1D12 U1.1E11 U1.1F12 U1.1L11 U1.1M12 U1.M22 U1.N21 U1.R21 U2.A1 U2.A8 U2.B2 U2.C1 U2.C9 U2.D2 U2.D9 U2.E9 U2.F1 U2.G7 U2.H2 U2.H9 U2.K2 U2.K8 U2.N1 U2.N9 U2.R1 U2.R9 U8.A1 U8.A8 U8.B2 U8.C1 U8.C9 U8.D2 U8.D9 U8.E9 U8.F1 U8.G7 U8.H2 U8.H9 U8.K2 U8.K8 U8.N1 U8.N9 U8.R1 U8.R9 U26.43 | length 84.4
  Top Layer w0.1: v4(82.407,32.675) 82.407,33.525 U2.R9@82.457,33.575 ; v4@98.908,38.9 U8.R9@98.908,39.777
  Top Layer w0.125: U2.C1@92.057,39.977 U2.B2@92.858,39.177
  Top Layer w0.15: v1(16.298,46.165) 16.7,45.763 LNK8.2@16.7,45.723 ; U1.1L11@65.125,39.075 v2(65.75,39) U1.1M12@65.625,38.575 65.625,38.565 65.9,38.29 v2@65.9,38.26 ; U1.1E11@65.125,42.075 v2@65.625,42.075 ; U1.1C11@65.125,43.075 65.675,43.075 v2(65.75,43) ; U1.1F12@65.625,41.575 v2@65.625,42.075 ; v2@65.675,42.99 65.675,42.646 65.625,42.597 U1.1D12@65.625,42.575 v2@65.625,42.075 ; v2@66.375,42.274 66.458,42.357 66.137,42.357 65.89,42.111 65.661,42.111 v2@65.625,42.075 ; C146.2@77.282,31.4 77.387,31.505 77.462,31.58 77.462,31.98 v4@77.482,32 ; v4@84.091,32.558 U2.N9@84.091,33.541 ; v4(85.257,35.575) 85.971,35.575 86.059,35.487 86.059,34.773 U2.K8@86.457,34.375 ; v4@87.657,39.625 88.058,39.224 U2.H2@88.058,39.177 ; v4@89.328,40.725 89.333,40.725 89.358,40.7 89.358,40.328 89.657,40.029 U2.F1@89.657,39.975 ; U2.D2@91.258,39.177 91.311,39.177 91.711,38.777 92.218,38.777 92.457,38.538 v4@92.457,38.025 ; v4(91.729,40.55) 91.796,40.483 91.796,40.377 91.799,40.374 91.799,40.287 92.057,40.029 92.057,39.977 U2.C1@92.057,39.975 ; v4(93.332,40.55) 93.332,40.455 93.449,40.338 93.449,40.253 93.582,40.119 93.582,40.117 93.657,40.042 U2.A1@93.657,39.975 ; v4(100.507,38.725) 100.507,38.819 100.582,38.894 U8.N9@100.582,39.75 ; v4@101.732,41.8 102.442,41.8 102.53,41.712 102.53,41.002 U8.K8@102.932,40.6 ; v4@103.332,45.05 103.357,45.025 104.156,45.025 U8.H2@104.533,45.402 ; v4(105.704,47.005) 105.711,46.801 105.808,46.704 105.808,46.628 106.107,46.328 U8.F1@106.107,46.2 ; v4@108.182,46.775 108.249,46.708 108.249,46.512 108.507,46.254 U8.C1@108.507,46.202 ; C110.2@108.333,37.002 108.582,37.251 108.583,37.252 C115.2@108.583,37.927 ; C110.2@108.334,36.857 C110.2@108.334,36.981 ; U8.C1@108.469,46.241 U8.C1@108.507,46.202 ; U8.C1@108.507,46.2 U8.C1@108.507,46.202 ; U8.C1@108.532,46.2 U8.B2@109.332,45.4 ; v4@109.793,46.75 109.793,46.685 110.093,46.385 110.093,46.238 U8.A1@110.132,46.2
  Top Layer w0.16: v2(65.75,39) 66.042,39.292 66.042,40.512 U1.R21@66.32,40.79 ; U1.R21@66.321,40.79 66.363,40.832 66.363,41.813 U1.N21@66.375,41.825 v2@66.375,42.274 ; U1.R21@66.375,40.825 66.394,40.825 66.471,40.902 66.757,40.902 v2@66.78,40.925 ; v2@66.458,42.357 66.843,42.357 U1.M22@66.875,42.325
  Top Layer w0.2: v4(83.849,40.5) 83.849,40.468 84.02,40.297 84.02,40.015 U2.N1@84.058,39.977 ; U2.K2@86.483,39.177 86.835,38.825 v4@86.857,38.825 ; U2.H9@88.02,33.538 88.024,33.538 88.057,33.505 v4@88.057,33.05 ; v4(98.882,47.094) 98.95,46.818 98.95,46.217 U8.R1@98.932,46.2 ; U8.K2@102.958,45.402 103.31,45.05 v4@103.332,45.05
  Top Layer w0.21: 24.775,46.4 U26.43@25.325,46.4
  Top Layer w0.25: 21.695,47.125 21.699,47.125 21.845,46.979 21.845,46.685 C39.2@21.955,46.575 ; C39.2@22.005,46.575 22.475,46.575 22.65,46.4 24.775,46.4
  Top Layer w0.275: U2.E9@90.457,33.575 U2.D9@91.257,33.575 91.259,33.577 91.825,33.577 ; 91.825,33.575 U2.C9@92.057,33.575 ; U8.H9@104.533,39.802 v4(104.933,40.202) ; U8.E9@106.934,39.811 107.319,39.425 v4(107.332,39.425) ; v4@107.332,39.525 107.359,39.498 107.406,39.498 107.67,39.762 107.674,39.762 107.711,39.8 U8.D9@107.732,39.8
  Top Layer w0.3: v3@21.444,47.376 21.695,47.125 ; C146.2@77.387,31.505 77.387,31.949 77.432,31.994 v4(77.432,32.048) ; C103.2@81.758,31.6 81.863,31.705 81.863,31.854 81.963,31.954 81.963,31.979 82.137,32.153 82.182,32.153 82.358,32.329 82.358,32.571 82.407,32.621 v4(82.407,32.675) ; v4(82.332,40.925) 82.332,40.871 82.557,40.646 82.557,40.088 82.457,39.988 U2.R1@82.457,39.975 ; C104.2@83.576,31.625 R143.2@84.183,31.625 84.158,31.6 C104.2@83.358,31.6 83.358,31.808 v4@84.032,32.482 ; v4@88.732,35.7 88.732,35.646 88.848,35.53 88.848,35.184 U2.G7@88.857,35.175 ; C101.2@91.507,30.65 91.807,30.95 91.807,31.675 C108.2@91.763,31.719 ; C108.2@91.732,31.675 91.732,32.721 91.982,32.971 v4(91.982,32.975) 91.982,33.029 92.048,33.094 92.048,33.565 U2.C9@92.057,33.575 ; U2.A8@93.71,34.375 93.856,34.375 94.131,34.65 v4@94.157,34.65 ; C111.2@98.583,37.902 98.688,38.007 98.688,38.705 v4(98.882,38.9) ; C114.2@100.158,37.825 100.224,37.759 R148.2@100.224,36.946 ; C114.2@100.27,37.989 100.27,38.433 100.507,38.671 v4(100.507,38.725) ; v4(100.333,46.689) 100.333,46.635 100.513,46.454 100.513,46.219 U8.N1@100.532,46.2 ; U8.G7@105.332,41.4 v4(105.333,41.95) ; U8.D9@107.732,39.8 108.532,39.8 108.541,39.79 108.541,39.52 108.732,39.329 v4(108.732,39.275) 108.732,38.076 C115.2@108.687,38.031 ; U8.D2@107.732,45.4 v4(108.132,45) ; C110.2@108.333,37.001 C110.2@108.582,37.25 ; C110.2@108.582,37.251 C115.2@108.582,37.9 ; C115.2@108.584,37.927 C115.2@108.687,38.03 ; U8.A8@110.132,40.6 110.343,40.6 v4@110.653,40.91 ; C167.2@110.733,36.35 110.75,36.368 v2(110.75,36.957) ; C177.2@112.025,49.305 112.15,49.18 v2(112.15,48.68)
  Top Layer w0.64: C202.2@15.975,42.45 C41.2@15.975,43.75 C200.2@15.975,45.05 ; 15.975,45.495 15.975,45.925
  Top Layer w0.8: C202.2@16.2,42.45 L5.2@17.975,42.45
  Bottom Layer w0.15: C83.2@65.35,43.425 v2@65.627,43.148 ; C82.2@65.352,41.603 65.452,41.703 65.452,41.862 v2@65.625,42.035 ; v2@65.625,42.075 65.625,42.143 65.675,42.193 v2@65.675,42.99 ; v2@65.673,42.027 66.023,42.027 66.183,41.867 C75.2@66.218,41.867 ; C75.2@66.205,41.9 66.305,41.8 66.34,41.8 66.78,41.36 v2@66.78,40.925
  Bottom Layer w0.16: C75.2@66.175,41.9 66.27,41.995 66.27,42.018 66.404,42.152 66.404,42.354 v2(66.45,42.4) ; C77.1@66.25,40.6 66.332,40.682 66.537,40.682 v2@66.78,40.925
  Bottom Layer w0.2: v2(65.75,39) 65.476,38.726 65.466,38.726 65.463,38.723 65.349,38.723 C76.2@65.274,38.648 65.349,38.573 65.607,38.573 65.92,38.26 v2(65.97,38.26)
  Bottom Layer w0.3: v4@82.332,40.923 82.369,40.96 82.369,41.76 82.407,41.798 82.407,42.502 82.582,42.678 82.662,42.678 82.832,42.848 C100.2@82.832,42.973 ; C102.2@89.308,40.002 89.308,40.605 89.933,41.23 R141.2@89.933,41.4 ; C105.2@92.432,38.673 92.444,38.66 92.444,38.035 v4@92.457,38.023 ; v4(93.332,40.55) 93.369,40.586 93.369,41.161 C107.2@93.407,41.198 ; C109.2@97.481,48.848 97.481,48.723 97.75,48.454 98.125,48.454 C116.2@98.844,47.735 ; C116.2@98.843,47.734 98.843,47.132 v4(98.882,47.094) ; C113.2@105.683,46.17 105.704,46.191 v4(105.704,47.005) 106.008,47.309 R146.2@106.008,47.735 ; v4(108.182,46.8) 108.182,46.22 C119.2@108.233,46.17 ; v4@108.195,46.787 v4@108.219,46.811 ; v4@109.781,46.748 109.781,46.802 109.851,46.872 109.851,47.318 C112.2@109.956,47.423
  other v1: 15.623,46.165 15.623,46.89 16.298,46.89
  other v2: 66.78,40.921 65.7,42.075
  other v3: 21.45,47.348
  other v4: 84.032,32.5 88.057,33.025 94.157,34.625 88.732,35.725 92.432,37.95 86.857,38.795 87.657,39.595 89.333,40.65 110.677,40.875 101.732,41.795 103.332,45.02 109.807,46.775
